VERSION 5.8 ;
BUSBITCHARS "[]" ;
DIVIDERCHAR "/" ;
UNITS
    DATABASE MICRONS 1000 ;
END UNITS

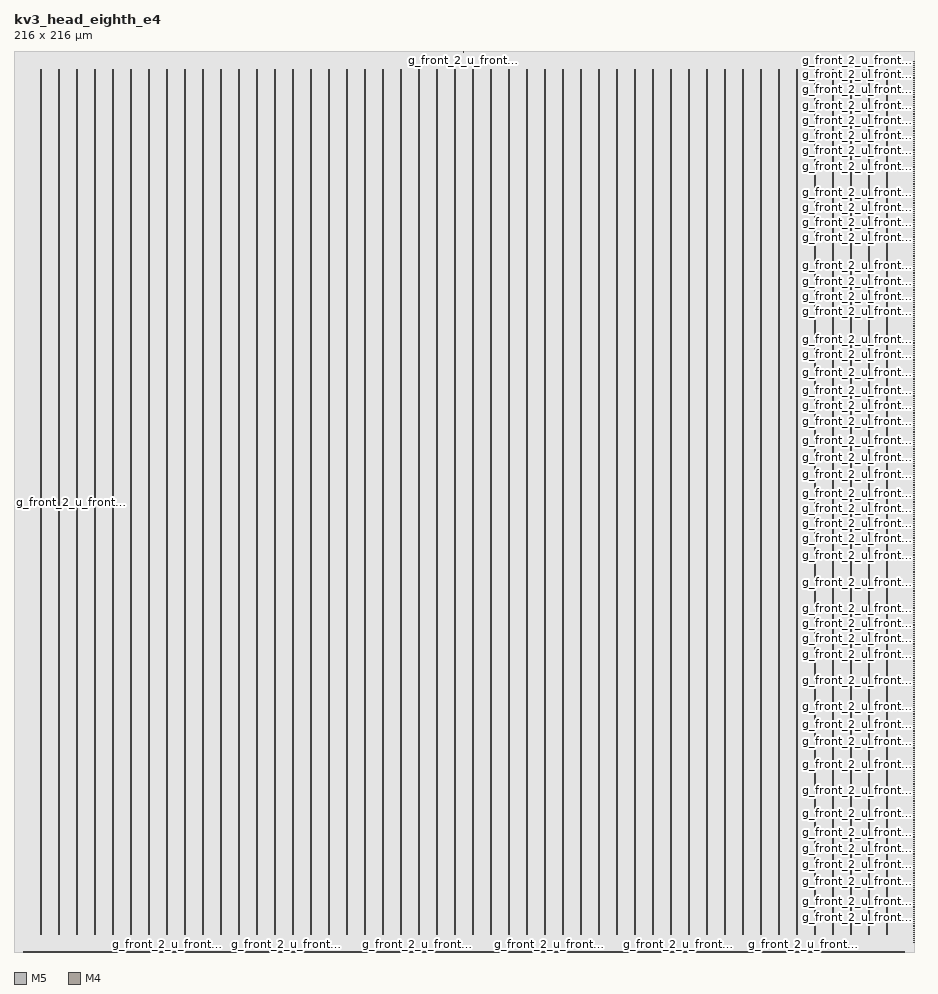
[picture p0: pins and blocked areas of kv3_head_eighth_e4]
MACRO kv3_head_eighth_e4
  FOREIGN kv3_head_eighth_e4 0 0 ;
  CLASS BLOCK ;
  SIZE 216 BY 216 ;
  PIN g_front_2_u_front__c_in[0]
    DIRECTION INPUT ;
    USE SIGNAL ;
    PORT
      LAYER M5 ;
        RECT  2.268 0 2.292 0.192 ;
    END
  END g_front_2_u_front__c_in[0]
  PIN g_front_2_u_front__c_in[1]
    DIRECTION INPUT ;
    USE SIGNAL ;
    PORT
      LAYER M5 ;
        RECT  2.508 0 2.532 0.192 ;
    END
  END g_front_2_u_front__c_in[1]
  PIN g_front_2_u_front__c_in[2]
    DIRECTION INPUT ;
    USE SIGNAL ;
    PORT
      LAYER M5 ;
        RECT  2.748 0 2.772 0.192 ;
    END
  END g_front_2_u_front__c_in[2]
  PIN g_front_2_u_front__c_in[3]
    DIRECTION INPUT ;
    USE SIGNAL ;
    PORT
      LAYER M5 ;
        RECT  2.988 0 3.012 0.192 ;
    END
  END g_front_2_u_front__c_in[3]
  PIN g_front_2_u_front__clk[0]
    DIRECTION INPUT ;
    USE SIGNAL ;
    PORT
      LAYER M5 ;
        RECT  3.228 0 3.252 0.192 ;
    END
  END g_front_2_u_front__clk[0]
  PIN g_front_2_u_front__e_in[0]
    DIRECTION INPUT ;
    USE SIGNAL ;
    PORT
      LAYER M5 ;
        RECT  3.468 0 3.492 0.192 ;
    END
  END g_front_2_u_front__e_in[0]
  PIN g_front_2_u_front__e_in[10]
    DIRECTION INPUT ;
    USE SIGNAL ;
    PORT
      LAYER M5 ;
        RECT  5.82 0 5.844 0.192 ;
    END
  END g_front_2_u_front__e_in[10]
  PIN g_front_2_u_front__e_in[11]
    DIRECTION INPUT ;
    USE SIGNAL ;
    PORT
      LAYER M5 ;
        RECT  6.06 0 6.084 0.192 ;
    END
  END g_front_2_u_front__e_in[11]
  PIN g_front_2_u_front__e_in[12]
    DIRECTION INPUT ;
    USE SIGNAL ;
    PORT
      LAYER M5 ;
        RECT  6.3 0 6.324 0.192 ;
    END
  END g_front_2_u_front__e_in[12]
  PIN g_front_2_u_front__e_in[13]
    DIRECTION INPUT ;
    USE SIGNAL ;
    PORT
      LAYER M5 ;
        RECT  6.54 0 6.564 0.192 ;
    END
  END g_front_2_u_front__e_in[13]
  PIN g_front_2_u_front__e_in[14]
    DIRECTION INPUT ;
    USE SIGNAL ;
    PORT
      LAYER M5 ;
        RECT  6.78 0 6.804 0.192 ;
    END
  END g_front_2_u_front__e_in[14]
  PIN g_front_2_u_front__e_in[15]
    DIRECTION INPUT ;
    USE SIGNAL ;
    PORT
      LAYER M5 ;
        RECT  7.02 0 7.044 0.192 ;
    END
  END g_front_2_u_front__e_in[15]
  PIN g_front_2_u_front__e_in[1]
    DIRECTION INPUT ;
    USE SIGNAL ;
    PORT
      LAYER M5 ;
        RECT  3.708 0 3.732 0.192 ;
    END
  END g_front_2_u_front__e_in[1]
  PIN g_front_2_u_front__e_in[2]
    DIRECTION INPUT ;
    USE SIGNAL ;
    PORT
      LAYER M5 ;
        RECT  3.948 0 3.972 0.192 ;
    END
  END g_front_2_u_front__e_in[2]
  PIN g_front_2_u_front__e_in[3]
    DIRECTION INPUT ;
    USE SIGNAL ;
    PORT
      LAYER M5 ;
        RECT  4.188 0 4.212 0.192 ;
    END
  END g_front_2_u_front__e_in[3]
  PIN g_front_2_u_front__e_in[4]
    DIRECTION INPUT ;
    USE SIGNAL ;
    PORT
      LAYER M5 ;
        RECT  4.428 0 4.452 0.192 ;
    END
  END g_front_2_u_front__e_in[4]
  PIN g_front_2_u_front__e_in[5]
    DIRECTION INPUT ;
    USE SIGNAL ;
    PORT
      LAYER M5 ;
        RECT  4.668 0 4.692 0.192 ;
    END
  END g_front_2_u_front__e_in[5]
  PIN g_front_2_u_front__e_in[6]
    DIRECTION INPUT ;
    USE SIGNAL ;
    PORT
      LAYER M5 ;
        RECT  4.908 0 4.932 0.192 ;
    END
  END g_front_2_u_front__e_in[6]
  PIN g_front_2_u_front__e_in[7]
    DIRECTION INPUT ;
    USE SIGNAL ;
    PORT
      LAYER M5 ;
        RECT  5.148 0 5.172 0.192 ;
    END
  END g_front_2_u_front__e_in[7]
  PIN g_front_2_u_front__e_in[8]
    DIRECTION INPUT ;
    USE SIGNAL ;
    PORT
      LAYER M5 ;
        RECT  5.388 0 5.412 0.192 ;
    END
  END g_front_2_u_front__e_in[8]
  PIN g_front_2_u_front__e_in[9]
    DIRECTION INPUT ;
    USE SIGNAL ;
    PORT
      LAYER M5 ;
        RECT  5.628 0 5.652 0.192 ;
    END
  END g_front_2_u_front__e_in[9]
  PIN g_front_2_u_front__f_t2[0]
    DIRECTION OUTPUT ;
    USE SIGNAL ;
    PORT
      LAYER M4 ;
        RECT  215.808 2.364 216 2.388 ;
    END
  END g_front_2_u_front__f_t2[0]
  PIN g_front_2_u_front__f_t2[100]
    DIRECTION OUTPUT ;
    USE SIGNAL ;
    PORT
      LAYER M4 ;
        RECT  215.808 47.82 216 47.844 ;
    END
  END g_front_2_u_front__f_t2[100]
  PIN g_front_2_u_front__f_t2[101]
    DIRECTION OUTPUT ;
    USE SIGNAL ;
    PORT
      LAYER M4 ;
        RECT  215.808 48.252 216 48.276 ;
    END
  END g_front_2_u_front__f_t2[101]
  PIN g_front_2_u_front__f_t2[102]
    DIRECTION OUTPUT ;
    USE SIGNAL ;
    PORT
      LAYER M4 ;
        RECT  215.808 48.732 216 48.756 ;
    END
  END g_front_2_u_front__f_t2[102]
  PIN g_front_2_u_front__f_t2[103]
    DIRECTION OUTPUT ;
    USE SIGNAL ;
    PORT
      LAYER M4 ;
        RECT  215.808 49.164 216 49.188 ;
    END
  END g_front_2_u_front__f_t2[103]
  PIN g_front_2_u_front__f_t2[104]
    DIRECTION OUTPUT ;
    USE SIGNAL ;
    PORT
      LAYER M4 ;
        RECT  215.808 49.596 216 49.62 ;
    END
  END g_front_2_u_front__f_t2[104]
  PIN g_front_2_u_front__f_t2[105]
    DIRECTION OUTPUT ;
    USE SIGNAL ;
    PORT
      LAYER M4 ;
        RECT  215.808 50.076 216 50.1 ;
    END
  END g_front_2_u_front__f_t2[105]
  PIN g_front_2_u_front__f_t2[106]
    DIRECTION OUTPUT ;
    USE SIGNAL ;
    PORT
      LAYER M4 ;
        RECT  215.808 50.508 216 50.532 ;
    END
  END g_front_2_u_front__f_t2[106]
  PIN g_front_2_u_front__f_t2[107]
    DIRECTION OUTPUT ;
    USE SIGNAL ;
    PORT
      LAYER M4 ;
        RECT  215.808 50.988 216 51.012 ;
    END
  END g_front_2_u_front__f_t2[107]
  PIN g_front_2_u_front__f_t2[108]
    DIRECTION OUTPUT ;
    USE SIGNAL ;
    PORT
      LAYER M4 ;
        RECT  215.808 51.42 216 51.444 ;
    END
  END g_front_2_u_front__f_t2[108]
  PIN g_front_2_u_front__f_t2[109]
    DIRECTION OUTPUT ;
    USE SIGNAL ;
    PORT
      LAYER M4 ;
        RECT  215.808 51.9 216 51.924 ;
    END
  END g_front_2_u_front__f_t2[109]
  PIN g_front_2_u_front__f_t2[10]
    DIRECTION OUTPUT ;
    USE SIGNAL ;
    PORT
      LAYER M4 ;
        RECT  215.808 6.924 216 6.948 ;
    END
  END g_front_2_u_front__f_t2[10]
  PIN g_front_2_u_front__f_t2[110]
    DIRECTION OUTPUT ;
    USE SIGNAL ;
    PORT
      LAYER M4 ;
        RECT  215.808 52.332 216 52.356 ;
    END
  END g_front_2_u_front__f_t2[110]
  PIN g_front_2_u_front__f_t2[111]
    DIRECTION OUTPUT ;
    USE SIGNAL ;
    PORT
      LAYER M4 ;
        RECT  215.808 52.812 216 52.836 ;
    END
  END g_front_2_u_front__f_t2[111]
  PIN g_front_2_u_front__f_t2[112]
    DIRECTION OUTPUT ;
    USE SIGNAL ;
    PORT
      LAYER M4 ;
        RECT  215.808 53.244 216 53.268 ;
    END
  END g_front_2_u_front__f_t2[112]
  PIN g_front_2_u_front__f_t2[113]
    DIRECTION OUTPUT ;
    USE SIGNAL ;
    PORT
      LAYER M4 ;
        RECT  215.808 53.724 216 53.748 ;
    END
  END g_front_2_u_front__f_t2[113]
  PIN g_front_2_u_front__f_t2[114]
    DIRECTION OUTPUT ;
    USE SIGNAL ;
    PORT
      LAYER M4 ;
        RECT  215.808 54.156 216 54.18 ;
    END
  END g_front_2_u_front__f_t2[114]
  PIN g_front_2_u_front__f_t2[115]
    DIRECTION OUTPUT ;
    USE SIGNAL ;
    PORT
      LAYER M4 ;
        RECT  215.808 54.636 216 54.66 ;
    END
  END g_front_2_u_front__f_t2[115]
  PIN g_front_2_u_front__f_t2[116]
    DIRECTION OUTPUT ;
    USE SIGNAL ;
    PORT
      LAYER M4 ;
        RECT  215.808 55.068 216 55.092 ;
    END
  END g_front_2_u_front__f_t2[116]
  PIN g_front_2_u_front__f_t2[117]
    DIRECTION OUTPUT ;
    USE SIGNAL ;
    PORT
      LAYER M4 ;
        RECT  215.808 55.5 216 55.524 ;
    END
  END g_front_2_u_front__f_t2[117]
  PIN g_front_2_u_front__f_t2[118]
    DIRECTION OUTPUT ;
    USE SIGNAL ;
    PORT
      LAYER M4 ;
        RECT  215.808 55.98 216 56.004 ;
    END
  END g_front_2_u_front__f_t2[118]
  PIN g_front_2_u_front__f_t2[119]
    DIRECTION OUTPUT ;
    USE SIGNAL ;
    PORT
      LAYER M4 ;
        RECT  215.808 56.412 216 56.436 ;
    END
  END g_front_2_u_front__f_t2[119]
  PIN g_front_2_u_front__f_t2[11]
    DIRECTION OUTPUT ;
    USE SIGNAL ;
    PORT
      LAYER M4 ;
        RECT  215.808 7.356 216 7.38 ;
    END
  END g_front_2_u_front__f_t2[11]
  PIN g_front_2_u_front__f_t2[120]
    DIRECTION OUTPUT ;
    USE SIGNAL ;
    PORT
      LAYER M4 ;
        RECT  215.808 56.892 216 56.916 ;
    END
  END g_front_2_u_front__f_t2[120]
  PIN g_front_2_u_front__f_t2[121]
    DIRECTION OUTPUT ;
    USE SIGNAL ;
    PORT
      LAYER M4 ;
        RECT  215.808 57.324 216 57.348 ;
    END
  END g_front_2_u_front__f_t2[121]
  PIN g_front_2_u_front__f_t2[122]
    DIRECTION OUTPUT ;
    USE SIGNAL ;
    PORT
      LAYER M4 ;
        RECT  215.808 57.804 216 57.828 ;
    END
  END g_front_2_u_front__f_t2[122]
  PIN g_front_2_u_front__f_t2[123]
    DIRECTION OUTPUT ;
    USE SIGNAL ;
    PORT
      LAYER M4 ;
        RECT  215.808 58.236 216 58.26 ;
    END
  END g_front_2_u_front__f_t2[123]
  PIN g_front_2_u_front__f_t2[124]
    DIRECTION OUTPUT ;
    USE SIGNAL ;
    PORT
      LAYER M4 ;
        RECT  215.808 58.716 216 58.74 ;
    END
  END g_front_2_u_front__f_t2[124]
  PIN g_front_2_u_front__f_t2[125]
    DIRECTION OUTPUT ;
    USE SIGNAL ;
    PORT
      LAYER M4 ;
        RECT  215.808 59.148 216 59.172 ;
    END
  END g_front_2_u_front__f_t2[125]
  PIN g_front_2_u_front__f_t2[126]
    DIRECTION OUTPUT ;
    USE SIGNAL ;
    PORT
      LAYER M4 ;
        RECT  215.808 59.628 216 59.652 ;
    END
  END g_front_2_u_front__f_t2[126]
  PIN g_front_2_u_front__f_t2[127]
    DIRECTION OUTPUT ;
    USE SIGNAL ;
    PORT
      LAYER M4 ;
        RECT  215.808 60.06 216 60.084 ;
    END
  END g_front_2_u_front__f_t2[127]
  PIN g_front_2_u_front__f_t2[128]
    DIRECTION OUTPUT ;
    USE SIGNAL ;
    PORT
      LAYER M4 ;
        RECT  215.808 60.54 216 60.564 ;
    END
  END g_front_2_u_front__f_t2[128]
  PIN g_front_2_u_front__f_t2[129]
    DIRECTION OUTPUT ;
    USE SIGNAL ;
    PORT
      LAYER M4 ;
        RECT  215.808 60.972 216 60.996 ;
    END
  END g_front_2_u_front__f_t2[129]
  PIN g_front_2_u_front__f_t2[12]
    DIRECTION OUTPUT ;
    USE SIGNAL ;
    PORT
      LAYER M4 ;
        RECT  215.808 7.836 216 7.86 ;
    END
  END g_front_2_u_front__f_t2[12]
  PIN g_front_2_u_front__f_t2[130]
    DIRECTION OUTPUT ;
    USE SIGNAL ;
    PORT
      LAYER M4 ;
        RECT  215.808 61.404 216 61.428 ;
    END
  END g_front_2_u_front__f_t2[130]
  PIN g_front_2_u_front__f_t2[131]
    DIRECTION OUTPUT ;
    USE SIGNAL ;
    PORT
      LAYER M4 ;
        RECT  215.808 61.884 216 61.908 ;
    END
  END g_front_2_u_front__f_t2[131]
  PIN g_front_2_u_front__f_t2[132]
    DIRECTION OUTPUT ;
    USE SIGNAL ;
    PORT
      LAYER M4 ;
        RECT  215.808 62.316 216 62.34 ;
    END
  END g_front_2_u_front__f_t2[132]
  PIN g_front_2_u_front__f_t2[133]
    DIRECTION OUTPUT ;
    USE SIGNAL ;
    PORT
      LAYER M4 ;
        RECT  215.808 62.796 216 62.82 ;
    END
  END g_front_2_u_front__f_t2[133]
  PIN g_front_2_u_front__f_t2[134]
    DIRECTION OUTPUT ;
    USE SIGNAL ;
    PORT
      LAYER M4 ;
        RECT  215.808 63.228 216 63.252 ;
    END
  END g_front_2_u_front__f_t2[134]
  PIN g_front_2_u_front__f_t2[135]
    DIRECTION OUTPUT ;
    USE SIGNAL ;
    PORT
      LAYER M4 ;
        RECT  215.808 63.708 216 63.732 ;
    END
  END g_front_2_u_front__f_t2[135]
  PIN g_front_2_u_front__f_t2[136]
    DIRECTION OUTPUT ;
    USE SIGNAL ;
    PORT
      LAYER M4 ;
        RECT  215.808 64.14 216 64.164 ;
    END
  END g_front_2_u_front__f_t2[136]
  PIN g_front_2_u_front__f_t2[137]
    DIRECTION OUTPUT ;
    USE SIGNAL ;
    PORT
      LAYER M4 ;
        RECT  215.808 64.62 216 64.644 ;
    END
  END g_front_2_u_front__f_t2[137]
  PIN g_front_2_u_front__f_t2[138]
    DIRECTION OUTPUT ;
    USE SIGNAL ;
    PORT
      LAYER M4 ;
        RECT  215.808 65.052 216 65.076 ;
    END
  END g_front_2_u_front__f_t2[138]
  PIN g_front_2_u_front__f_t2[139]
    DIRECTION OUTPUT ;
    USE SIGNAL ;
    PORT
      LAYER M4 ;
        RECT  215.808 65.532 216 65.556 ;
    END
  END g_front_2_u_front__f_t2[139]
  PIN g_front_2_u_front__f_t2[13]
    DIRECTION OUTPUT ;
    USE SIGNAL ;
    PORT
      LAYER M4 ;
        RECT  215.808 8.268 216 8.292 ;
    END
  END g_front_2_u_front__f_t2[13]
  PIN g_front_2_u_front__f_t2[140]
    DIRECTION OUTPUT ;
    USE SIGNAL ;
    PORT
      LAYER M4 ;
        RECT  215.808 65.964 216 65.988 ;
    END
  END g_front_2_u_front__f_t2[140]
  PIN g_front_2_u_front__f_t2[141]
    DIRECTION OUTPUT ;
    USE SIGNAL ;
    PORT
      LAYER M4 ;
        RECT  215.808 66.444 216 66.468 ;
    END
  END g_front_2_u_front__f_t2[141]
  PIN g_front_2_u_front__f_t2[142]
    DIRECTION OUTPUT ;
    USE SIGNAL ;
    PORT
      LAYER M4 ;
        RECT  215.808 66.876 216 66.9 ;
    END
  END g_front_2_u_front__f_t2[142]
  PIN g_front_2_u_front__f_t2[143]
    DIRECTION OUTPUT ;
    USE SIGNAL ;
    PORT
      LAYER M4 ;
        RECT  215.808 67.356 216 67.38 ;
    END
  END g_front_2_u_front__f_t2[143]
  PIN g_front_2_u_front__f_t2[144]
    DIRECTION OUTPUT ;
    USE SIGNAL ;
    PORT
      LAYER M4 ;
        RECT  215.808 67.788 216 67.812 ;
    END
  END g_front_2_u_front__f_t2[144]
  PIN g_front_2_u_front__f_t2[145]
    DIRECTION OUTPUT ;
    USE SIGNAL ;
    PORT
      LAYER M4 ;
        RECT  215.808 68.22 216 68.244 ;
    END
  END g_front_2_u_front__f_t2[145]
  PIN g_front_2_u_front__f_t2[146]
    DIRECTION OUTPUT ;
    USE SIGNAL ;
    PORT
      LAYER M4 ;
        RECT  215.808 68.7 216 68.724 ;
    END
  END g_front_2_u_front__f_t2[146]
  PIN g_front_2_u_front__f_t2[147]
    DIRECTION OUTPUT ;
    USE SIGNAL ;
    PORT
      LAYER M4 ;
        RECT  215.808 69.132 216 69.156 ;
    END
  END g_front_2_u_front__f_t2[147]
  PIN g_front_2_u_front__f_t2[148]
    DIRECTION OUTPUT ;
    USE SIGNAL ;
    PORT
      LAYER M4 ;
        RECT  215.808 69.612 216 69.636 ;
    END
  END g_front_2_u_front__f_t2[148]
  PIN g_front_2_u_front__f_t2[149]
    DIRECTION OUTPUT ;
    USE SIGNAL ;
    PORT
      LAYER M4 ;
        RECT  215.808 70.044 216 70.068 ;
    END
  END g_front_2_u_front__f_t2[149]
  PIN g_front_2_u_front__f_t2[14]
    DIRECTION OUTPUT ;
    USE SIGNAL ;
    PORT
      LAYER M4 ;
        RECT  215.808 8.748 216 8.772 ;
    END
  END g_front_2_u_front__f_t2[14]
  PIN g_front_2_u_front__f_t2[150]
    DIRECTION OUTPUT ;
    USE SIGNAL ;
    PORT
      LAYER M4 ;
        RECT  215.808 70.524 216 70.548 ;
    END
  END g_front_2_u_front__f_t2[150]
  PIN g_front_2_u_front__f_t2[151]
    DIRECTION OUTPUT ;
    USE SIGNAL ;
    PORT
      LAYER M4 ;
        RECT  215.808 70.956 216 70.98 ;
    END
  END g_front_2_u_front__f_t2[151]
  PIN g_front_2_u_front__f_t2[152]
    DIRECTION OUTPUT ;
    USE SIGNAL ;
    PORT
      LAYER M4 ;
        RECT  215.808 71.436 216 71.46 ;
    END
  END g_front_2_u_front__f_t2[152]
  PIN g_front_2_u_front__f_t2[153]
    DIRECTION OUTPUT ;
    USE SIGNAL ;
    PORT
      LAYER M4 ;
        RECT  215.808 71.868 216 71.892 ;
    END
  END g_front_2_u_front__f_t2[153]
  PIN g_front_2_u_front__f_t2[154]
    DIRECTION OUTPUT ;
    USE SIGNAL ;
    PORT
      LAYER M4 ;
        RECT  215.808 72.348 216 72.372 ;
    END
  END g_front_2_u_front__f_t2[154]
  PIN g_front_2_u_front__f_t2[155]
    DIRECTION OUTPUT ;
    USE SIGNAL ;
    PORT
      LAYER M4 ;
        RECT  215.808 72.78 216 72.804 ;
    END
  END g_front_2_u_front__f_t2[155]
  PIN g_front_2_u_front__f_t2[156]
    DIRECTION OUTPUT ;
    USE SIGNAL ;
    PORT
      LAYER M4 ;
        RECT  215.808 73.26 216 73.284 ;
    END
  END g_front_2_u_front__f_t2[156]
  PIN g_front_2_u_front__f_t2[157]
    DIRECTION OUTPUT ;
    USE SIGNAL ;
    PORT
      LAYER M4 ;
        RECT  215.808 73.692 216 73.716 ;
    END
  END g_front_2_u_front__f_t2[157]
  PIN g_front_2_u_front__f_t2[158]
    DIRECTION OUTPUT ;
    USE SIGNAL ;
    PORT
      LAYER M4 ;
        RECT  215.808 74.124 216 74.148 ;
    END
  END g_front_2_u_front__f_t2[158]
  PIN g_front_2_u_front__f_t2[159]
    DIRECTION OUTPUT ;
    USE SIGNAL ;
    PORT
      LAYER M4 ;
        RECT  215.808 74.604 216 74.628 ;
    END
  END g_front_2_u_front__f_t2[159]
  PIN g_front_2_u_front__f_t2[15]
    DIRECTION OUTPUT ;
    USE SIGNAL ;
    PORT
      LAYER M4 ;
        RECT  215.808 9.18 216 9.204 ;
    END
  END g_front_2_u_front__f_t2[15]
  PIN g_front_2_u_front__f_t2[160]
    DIRECTION OUTPUT ;
    USE SIGNAL ;
    PORT
      LAYER M4 ;
        RECT  215.808 75.036 216 75.06 ;
    END
  END g_front_2_u_front__f_t2[160]
  PIN g_front_2_u_front__f_t2[161]
    DIRECTION OUTPUT ;
    USE SIGNAL ;
    PORT
      LAYER M4 ;
        RECT  215.808 75.516 216 75.54 ;
    END
  END g_front_2_u_front__f_t2[161]
  PIN g_front_2_u_front__f_t2[162]
    DIRECTION OUTPUT ;
    USE SIGNAL ;
    PORT
      LAYER M4 ;
        RECT  215.808 75.948 216 75.972 ;
    END
  END g_front_2_u_front__f_t2[162]
  PIN g_front_2_u_front__f_t2[163]
    DIRECTION OUTPUT ;
    USE SIGNAL ;
    PORT
      LAYER M4 ;
        RECT  215.808 76.428 216 76.452 ;
    END
  END g_front_2_u_front__f_t2[163]
  PIN g_front_2_u_front__f_t2[164]
    DIRECTION OUTPUT ;
    USE SIGNAL ;
    PORT
      LAYER M4 ;
        RECT  215.808 76.86 216 76.884 ;
    END
  END g_front_2_u_front__f_t2[164]
  PIN g_front_2_u_front__f_t2[165]
    DIRECTION OUTPUT ;
    USE SIGNAL ;
    PORT
      LAYER M4 ;
        RECT  215.808 77.34 216 77.364 ;
    END
  END g_front_2_u_front__f_t2[165]
  PIN g_front_2_u_front__f_t2[166]
    DIRECTION OUTPUT ;
    USE SIGNAL ;
    PORT
      LAYER M4 ;
        RECT  215.808 77.772 216 77.796 ;
    END
  END g_front_2_u_front__f_t2[166]
  PIN g_front_2_u_front__f_t2[167]
    DIRECTION OUTPUT ;
    USE SIGNAL ;
    PORT
      LAYER M4 ;
        RECT  215.808 78.252 216 78.276 ;
    END
  END g_front_2_u_front__f_t2[167]
  PIN g_front_2_u_front__f_t2[168]
    DIRECTION OUTPUT ;
    USE SIGNAL ;
    PORT
      LAYER M4 ;
        RECT  215.808 78.684 216 78.708 ;
    END
  END g_front_2_u_front__f_t2[168]
  PIN g_front_2_u_front__f_t2[169]
    DIRECTION OUTPUT ;
    USE SIGNAL ;
    PORT
      LAYER M4 ;
        RECT  215.808 79.164 216 79.188 ;
    END
  END g_front_2_u_front__f_t2[169]
  PIN g_front_2_u_front__f_t2[16]
    DIRECTION OUTPUT ;
    USE SIGNAL ;
    PORT
      LAYER M4 ;
        RECT  215.808 9.66 216 9.684 ;
    END
  END g_front_2_u_front__f_t2[16]
  PIN g_front_2_u_front__f_t2[170]
    DIRECTION OUTPUT ;
    USE SIGNAL ;
    PORT
      LAYER M4 ;
        RECT  215.808 79.596 216 79.62 ;
    END
  END g_front_2_u_front__f_t2[170]
  PIN g_front_2_u_front__f_t2[171]
    DIRECTION OUTPUT ;
    USE SIGNAL ;
    PORT
      LAYER M4 ;
        RECT  215.808 80.028 216 80.052 ;
    END
  END g_front_2_u_front__f_t2[171]
  PIN g_front_2_u_front__f_t2[172]
    DIRECTION OUTPUT ;
    USE SIGNAL ;
    PORT
      LAYER M4 ;
        RECT  215.808 80.508 216 80.532 ;
    END
  END g_front_2_u_front__f_t2[172]
  PIN g_front_2_u_front__f_t2[173]
    DIRECTION OUTPUT ;
    USE SIGNAL ;
    PORT
      LAYER M4 ;
        RECT  215.808 80.94 216 80.964 ;
    END
  END g_front_2_u_front__f_t2[173]
  PIN g_front_2_u_front__f_t2[174]
    DIRECTION OUTPUT ;
    USE SIGNAL ;
    PORT
      LAYER M4 ;
        RECT  215.808 81.42 216 81.444 ;
    END
  END g_front_2_u_front__f_t2[174]
  PIN g_front_2_u_front__f_t2[175]
    DIRECTION OUTPUT ;
    USE SIGNAL ;
    PORT
      LAYER M4 ;
        RECT  215.808 81.852 216 81.876 ;
    END
  END g_front_2_u_front__f_t2[175]
  PIN g_front_2_u_front__f_t2[176]
    DIRECTION OUTPUT ;
    USE SIGNAL ;
    PORT
      LAYER M4 ;
        RECT  215.808 82.332 216 82.356 ;
    END
  END g_front_2_u_front__f_t2[176]
  PIN g_front_2_u_front__f_t2[177]
    DIRECTION OUTPUT ;
    USE SIGNAL ;
    PORT
      LAYER M4 ;
        RECT  215.808 82.764 216 82.788 ;
    END
  END g_front_2_u_front__f_t2[177]
  PIN g_front_2_u_front__f_t2[178]
    DIRECTION OUTPUT ;
    USE SIGNAL ;
    PORT
      LAYER M4 ;
        RECT  215.808 83.244 216 83.268 ;
    END
  END g_front_2_u_front__f_t2[178]
  PIN g_front_2_u_front__f_t2[179]
    DIRECTION OUTPUT ;
    USE SIGNAL ;
    PORT
      LAYER M4 ;
        RECT  215.808 83.676 216 83.7 ;
    END
  END g_front_2_u_front__f_t2[179]
  PIN g_front_2_u_front__f_t2[17]
    DIRECTION OUTPUT ;
    USE SIGNAL ;
    PORT
      LAYER M4 ;
        RECT  215.808 10.092 216 10.116 ;
    END
  END g_front_2_u_front__f_t2[17]
  PIN g_front_2_u_front__f_t2[180]
    DIRECTION OUTPUT ;
    USE SIGNAL ;
    PORT
      LAYER M4 ;
        RECT  215.808 84.156 216 84.18 ;
    END
  END g_front_2_u_front__f_t2[180]
  PIN g_front_2_u_front__f_t2[181]
    DIRECTION OUTPUT ;
    USE SIGNAL ;
    PORT
      LAYER M4 ;
        RECT  215.808 84.588 216 84.612 ;
    END
  END g_front_2_u_front__f_t2[181]
  PIN g_front_2_u_front__f_t2[182]
    DIRECTION OUTPUT ;
    USE SIGNAL ;
    PORT
      LAYER M4 ;
        RECT  215.808 85.068 216 85.092 ;
    END
  END g_front_2_u_front__f_t2[182]
  PIN g_front_2_u_front__f_t2[183]
    DIRECTION OUTPUT ;
    USE SIGNAL ;
    PORT
      LAYER M4 ;
        RECT  215.808 85.5 216 85.524 ;
    END
  END g_front_2_u_front__f_t2[183]
  PIN g_front_2_u_front__f_t2[184]
    DIRECTION OUTPUT ;
    USE SIGNAL ;
    PORT
      LAYER M4 ;
        RECT  215.808 85.98 216 86.004 ;
    END
  END g_front_2_u_front__f_t2[184]
  PIN g_front_2_u_front__f_t2[185]
    DIRECTION OUTPUT ;
    USE SIGNAL ;
    PORT
      LAYER M4 ;
        RECT  215.808 86.412 216 86.436 ;
    END
  END g_front_2_u_front__f_t2[185]
  PIN g_front_2_u_front__f_t2[186]
    DIRECTION OUTPUT ;
    USE SIGNAL ;
    PORT
      LAYER M4 ;
        RECT  215.808 86.844 216 86.868 ;
    END
  END g_front_2_u_front__f_t2[186]
  PIN g_front_2_u_front__f_t2[187]
    DIRECTION OUTPUT ;
    USE SIGNAL ;
    PORT
      LAYER M4 ;
        RECT  215.808 87.324 216 87.348 ;
    END
  END g_front_2_u_front__f_t2[187]
  PIN g_front_2_u_front__f_t2[188]
    DIRECTION OUTPUT ;
    USE SIGNAL ;
    PORT
      LAYER M4 ;
        RECT  215.808 87.756 216 87.78 ;
    END
  END g_front_2_u_front__f_t2[188]
  PIN g_front_2_u_front__f_t2[189]
    DIRECTION OUTPUT ;
    USE SIGNAL ;
    PORT
      LAYER M4 ;
        RECT  215.808 88.236 216 88.26 ;
    END
  END g_front_2_u_front__f_t2[189]
  PIN g_front_2_u_front__f_t2[18]
    DIRECTION OUTPUT ;
    USE SIGNAL ;
    PORT
      LAYER M4 ;
        RECT  215.808 10.572 216 10.596 ;
    END
  END g_front_2_u_front__f_t2[18]
  PIN g_front_2_u_front__f_t2[190]
    DIRECTION OUTPUT ;
    USE SIGNAL ;
    PORT
      LAYER M4 ;
        RECT  215.808 88.668 216 88.692 ;
    END
  END g_front_2_u_front__f_t2[190]
  PIN g_front_2_u_front__f_t2[191]
    DIRECTION OUTPUT ;
    USE SIGNAL ;
    PORT
      LAYER M4 ;
        RECT  215.808 89.148 216 89.172 ;
    END
  END g_front_2_u_front__f_t2[191]
  PIN g_front_2_u_front__f_t2[192]
    DIRECTION OUTPUT ;
    USE SIGNAL ;
    PORT
      LAYER M4 ;
        RECT  215.808 89.58 216 89.604 ;
    END
  END g_front_2_u_front__f_t2[192]
  PIN g_front_2_u_front__f_t2[193]
    DIRECTION OUTPUT ;
    USE SIGNAL ;
    PORT
      LAYER M4 ;
        RECT  215.808 90.06 216 90.084 ;
    END
  END g_front_2_u_front__f_t2[193]
  PIN g_front_2_u_front__f_t2[194]
    DIRECTION OUTPUT ;
    USE SIGNAL ;
    PORT
      LAYER M4 ;
        RECT  215.808 90.492 216 90.516 ;
    END
  END g_front_2_u_front__f_t2[194]
  PIN g_front_2_u_front__f_t2[195]
    DIRECTION OUTPUT ;
    USE SIGNAL ;
    PORT
      LAYER M4 ;
        RECT  215.808 90.972 216 90.996 ;
    END
  END g_front_2_u_front__f_t2[195]
  PIN g_front_2_u_front__f_t2[196]
    DIRECTION OUTPUT ;
    USE SIGNAL ;
    PORT
      LAYER M4 ;
        RECT  215.808 91.404 216 91.428 ;
    END
  END g_front_2_u_front__f_t2[196]
  PIN g_front_2_u_front__f_t2[197]
    DIRECTION OUTPUT ;
    USE SIGNAL ;
    PORT
      LAYER M4 ;
        RECT  215.808 91.884 216 91.908 ;
    END
  END g_front_2_u_front__f_t2[197]
  PIN g_front_2_u_front__f_t2[198]
    DIRECTION OUTPUT ;
    USE SIGNAL ;
    PORT
      LAYER M4 ;
        RECT  215.808 92.316 216 92.34 ;
    END
  END g_front_2_u_front__f_t2[198]
  PIN g_front_2_u_front__f_t2[199]
    DIRECTION OUTPUT ;
    USE SIGNAL ;
    PORT
      LAYER M4 ;
        RECT  215.808 92.748 216 92.772 ;
    END
  END g_front_2_u_front__f_t2[199]
  PIN g_front_2_u_front__f_t2[19]
    DIRECTION OUTPUT ;
    USE SIGNAL ;
    PORT
      LAYER M4 ;
        RECT  215.808 11.004 216 11.028 ;
    END
  END g_front_2_u_front__f_t2[19]
  PIN g_front_2_u_front__f_t2[1]
    DIRECTION OUTPUT ;
    USE SIGNAL ;
    PORT
      LAYER M4 ;
        RECT  215.808 2.844 216 2.868 ;
    END
  END g_front_2_u_front__f_t2[1]
  PIN g_front_2_u_front__f_t2[200]
    DIRECTION OUTPUT ;
    USE SIGNAL ;
    PORT
      LAYER M4 ;
        RECT  215.808 93.228 216 93.252 ;
    END
  END g_front_2_u_front__f_t2[200]
  PIN g_front_2_u_front__f_t2[201]
    DIRECTION OUTPUT ;
    USE SIGNAL ;
    PORT
      LAYER M4 ;
        RECT  215.808 93.66 216 93.684 ;
    END
  END g_front_2_u_front__f_t2[201]
  PIN g_front_2_u_front__f_t2[202]
    DIRECTION OUTPUT ;
    USE SIGNAL ;
    PORT
      LAYER M4 ;
        RECT  215.808 94.14 216 94.164 ;
    END
  END g_front_2_u_front__f_t2[202]
  PIN g_front_2_u_front__f_t2[203]
    DIRECTION OUTPUT ;
    USE SIGNAL ;
    PORT
      LAYER M4 ;
        RECT  215.808 94.572 216 94.596 ;
    END
  END g_front_2_u_front__f_t2[203]
  PIN g_front_2_u_front__f_t2[204]
    DIRECTION OUTPUT ;
    USE SIGNAL ;
    PORT
      LAYER M4 ;
        RECT  215.808 95.052 216 95.076 ;
    END
  END g_front_2_u_front__f_t2[204]
  PIN g_front_2_u_front__f_t2[205]
    DIRECTION OUTPUT ;
    USE SIGNAL ;
    PORT
      LAYER M4 ;
        RECT  215.808 95.484 216 95.508 ;
    END
  END g_front_2_u_front__f_t2[205]
  PIN g_front_2_u_front__f_t2[206]
    DIRECTION OUTPUT ;
    USE SIGNAL ;
    PORT
      LAYER M4 ;
        RECT  215.808 95.964 216 95.988 ;
    END
  END g_front_2_u_front__f_t2[206]
  PIN g_front_2_u_front__f_t2[207]
    DIRECTION OUTPUT ;
    USE SIGNAL ;
    PORT
      LAYER M4 ;
        RECT  215.808 96.396 216 96.42 ;
    END
  END g_front_2_u_front__f_t2[207]
  PIN g_front_2_u_front__f_t2[208]
    DIRECTION OUTPUT ;
    USE SIGNAL ;
    PORT
      LAYER M4 ;
        RECT  215.808 96.876 216 96.9 ;
    END
  END g_front_2_u_front__f_t2[208]
  PIN g_front_2_u_front__f_t2[209]
    DIRECTION OUTPUT ;
    USE SIGNAL ;
    PORT
      LAYER M4 ;
        RECT  215.808 97.308 216 97.332 ;
    END
  END g_front_2_u_front__f_t2[209]
  PIN g_front_2_u_front__f_t2[20]
    DIRECTION OUTPUT ;
    USE SIGNAL ;
    PORT
      LAYER M4 ;
        RECT  215.808 11.484 216 11.508 ;
    END
  END g_front_2_u_front__f_t2[20]
  PIN g_front_2_u_front__f_t2[210]
    DIRECTION OUTPUT ;
    USE SIGNAL ;
    PORT
      LAYER M4 ;
        RECT  215.808 97.788 216 97.812 ;
    END
  END g_front_2_u_front__f_t2[210]
  PIN g_front_2_u_front__f_t2[211]
    DIRECTION OUTPUT ;
    USE SIGNAL ;
    PORT
      LAYER M4 ;
        RECT  215.808 98.22 216 98.244 ;
    END
  END g_front_2_u_front__f_t2[211]
  PIN g_front_2_u_front__f_t2[212]
    DIRECTION OUTPUT ;
    USE SIGNAL ;
    PORT
      LAYER M4 ;
        RECT  215.808 98.652 216 98.676 ;
    END
  END g_front_2_u_front__f_t2[212]
  PIN g_front_2_u_front__f_t2[213]
    DIRECTION OUTPUT ;
    USE SIGNAL ;
    PORT
      LAYER M4 ;
        RECT  215.808 99.132 216 99.156 ;
    END
  END g_front_2_u_front__f_t2[213]
  PIN g_front_2_u_front__f_t2[214]
    DIRECTION OUTPUT ;
    USE SIGNAL ;
    PORT
      LAYER M4 ;
        RECT  215.808 99.564 216 99.588 ;
    END
  END g_front_2_u_front__f_t2[214]
  PIN g_front_2_u_front__f_t2[215]
    DIRECTION OUTPUT ;
    USE SIGNAL ;
    PORT
      LAYER M4 ;
        RECT  215.808 100.044 216 100.068 ;
    END
  END g_front_2_u_front__f_t2[215]
  PIN g_front_2_u_front__f_t2[216]
    DIRECTION OUTPUT ;
    USE SIGNAL ;
    PORT
      LAYER M4 ;
        RECT  215.808 100.476 216 100.5 ;
    END
  END g_front_2_u_front__f_t2[216]
  PIN g_front_2_u_front__f_t2[217]
    DIRECTION OUTPUT ;
    USE SIGNAL ;
    PORT
      LAYER M4 ;
        RECT  215.808 100.956 216 100.98 ;
    END
  END g_front_2_u_front__f_t2[217]
  PIN g_front_2_u_front__f_t2[218]
    DIRECTION OUTPUT ;
    USE SIGNAL ;
    PORT
      LAYER M4 ;
        RECT  215.808 101.388 216 101.412 ;
    END
  END g_front_2_u_front__f_t2[218]
  PIN g_front_2_u_front__f_t2[219]
    DIRECTION OUTPUT ;
    USE SIGNAL ;
    PORT
      LAYER M4 ;
        RECT  215.808 101.868 216 101.892 ;
    END
  END g_front_2_u_front__f_t2[219]
  PIN g_front_2_u_front__f_t2[21]
    DIRECTION OUTPUT ;
    USE SIGNAL ;
    PORT
      LAYER M4 ;
        RECT  215.808 11.916 216 11.94 ;
    END
  END g_front_2_u_front__f_t2[21]
  PIN g_front_2_u_front__f_t2[220]
    DIRECTION OUTPUT ;
    USE SIGNAL ;
    PORT
      LAYER M4 ;
        RECT  215.808 102.3 216 102.324 ;
    END
  END g_front_2_u_front__f_t2[220]
  PIN g_front_2_u_front__f_t2[221]
    DIRECTION OUTPUT ;
    USE SIGNAL ;
    PORT
      LAYER M4 ;
        RECT  215.808 102.78 216 102.804 ;
    END
  END g_front_2_u_front__f_t2[221]
  PIN g_front_2_u_front__f_t2[222]
    DIRECTION OUTPUT ;
    USE SIGNAL ;
    PORT
      LAYER M4 ;
        RECT  215.808 103.212 216 103.236 ;
    END
  END g_front_2_u_front__f_t2[222]
  PIN g_front_2_u_front__f_t2[223]
    DIRECTION OUTPUT ;
    USE SIGNAL ;
    PORT
      LAYER M4 ;
        RECT  215.808 103.692 216 103.716 ;
    END
  END g_front_2_u_front__f_t2[223]
  PIN g_front_2_u_front__f_t2[224]
    DIRECTION OUTPUT ;
    USE SIGNAL ;
    PORT
      LAYER M4 ;
        RECT  215.808 104.124 216 104.148 ;
    END
  END g_front_2_u_front__f_t2[224]
  PIN g_front_2_u_front__f_t2[225]
    DIRECTION OUTPUT ;
    USE SIGNAL ;
    PORT
      LAYER M4 ;
        RECT  215.808 104.604 216 104.628 ;
    END
  END g_front_2_u_front__f_t2[225]
  PIN g_front_2_u_front__f_t2[226]
    DIRECTION OUTPUT ;
    USE SIGNAL ;
    PORT
      LAYER M4 ;
        RECT  215.808 105.036 216 105.06 ;
    END
  END g_front_2_u_front__f_t2[226]
  PIN g_front_2_u_front__f_t2[227]
    DIRECTION OUTPUT ;
    USE SIGNAL ;
    PORT
      LAYER M4 ;
        RECT  215.808 105.468 216 105.492 ;
    END
  END g_front_2_u_front__f_t2[227]
  PIN g_front_2_u_front__f_t2[228]
    DIRECTION OUTPUT ;
    USE SIGNAL ;
    PORT
      LAYER M4 ;
        RECT  215.808 105.948 216 105.972 ;
    END
  END g_front_2_u_front__f_t2[228]
  PIN g_front_2_u_front__f_t2[229]
    DIRECTION OUTPUT ;
    USE SIGNAL ;
    PORT
      LAYER M4 ;
        RECT  215.808 106.38 216 106.404 ;
    END
  END g_front_2_u_front__f_t2[229]
  PIN g_front_2_u_front__f_t2[22]
    DIRECTION OUTPUT ;
    USE SIGNAL ;
    PORT
      LAYER M4 ;
        RECT  215.808 12.348 216 12.372 ;
    END
  END g_front_2_u_front__f_t2[22]
  PIN g_front_2_u_front__f_t2[230]
    DIRECTION OUTPUT ;
    USE SIGNAL ;
    PORT
      LAYER M4 ;
        RECT  215.808 106.86 216 106.884 ;
    END
  END g_front_2_u_front__f_t2[230]
  PIN g_front_2_u_front__f_t2[231]
    DIRECTION OUTPUT ;
    USE SIGNAL ;
    PORT
      LAYER M4 ;
        RECT  215.808 107.292 216 107.316 ;
    END
  END g_front_2_u_front__f_t2[231]
  PIN g_front_2_u_front__f_t2[232]
    DIRECTION OUTPUT ;
    USE SIGNAL ;
    PORT
      LAYER M4 ;
        RECT  215.808 107.772 216 107.796 ;
    END
  END g_front_2_u_front__f_t2[232]
  PIN g_front_2_u_front__f_t2[23]
    DIRECTION OUTPUT ;
    USE SIGNAL ;
    PORT
      LAYER M4 ;
        RECT  215.808 12.828 216 12.852 ;
    END
  END g_front_2_u_front__f_t2[23]
  PIN g_front_2_u_front__f_t2[24]
    DIRECTION OUTPUT ;
    USE SIGNAL ;
    PORT
      LAYER M4 ;
        RECT  215.808 13.26 216 13.284 ;
    END
  END g_front_2_u_front__f_t2[24]
  PIN g_front_2_u_front__f_t2[25]
    DIRECTION OUTPUT ;
    USE SIGNAL ;
    PORT
      LAYER M4 ;
        RECT  215.808 13.74 216 13.764 ;
    END
  END g_front_2_u_front__f_t2[25]
  PIN g_front_2_u_front__f_t2[26]
    DIRECTION OUTPUT ;
    USE SIGNAL ;
    PORT
      LAYER M4 ;
        RECT  215.808 14.172 216 14.196 ;
    END
  END g_front_2_u_front__f_t2[26]
  PIN g_front_2_u_front__f_t2[27]
    DIRECTION OUTPUT ;
    USE SIGNAL ;
    PORT
      LAYER M4 ;
        RECT  215.808 14.652 216 14.676 ;
    END
  END g_front_2_u_front__f_t2[27]
  PIN g_front_2_u_front__f_t2[28]
    DIRECTION OUTPUT ;
    USE SIGNAL ;
    PORT
      LAYER M4 ;
        RECT  215.808 15.084 216 15.108 ;
    END
  END g_front_2_u_front__f_t2[28]
  PIN g_front_2_u_front__f_t2[29]
    DIRECTION OUTPUT ;
    USE SIGNAL ;
    PORT
      LAYER M4 ;
        RECT  215.808 15.564 216 15.588 ;
    END
  END g_front_2_u_front__f_t2[29]
  PIN g_front_2_u_front__f_t2[2]
    DIRECTION OUTPUT ;
    USE SIGNAL ;
    PORT
      LAYER M4 ;
        RECT  215.808 3.276 216 3.3 ;
    END
  END g_front_2_u_front__f_t2[2]
  PIN g_front_2_u_front__f_t2[30]
    DIRECTION OUTPUT ;
    USE SIGNAL ;
    PORT
      LAYER M4 ;
        RECT  215.808 15.996 216 16.02 ;
    END
  END g_front_2_u_front__f_t2[30]
  PIN g_front_2_u_front__f_t2[31]
    DIRECTION OUTPUT ;
    USE SIGNAL ;
    PORT
      LAYER M4 ;
        RECT  215.808 16.476 216 16.5 ;
    END
  END g_front_2_u_front__f_t2[31]
  PIN g_front_2_u_front__f_t2[32]
    DIRECTION OUTPUT ;
    USE SIGNAL ;
    PORT
      LAYER M4 ;
        RECT  215.808 16.908 216 16.932 ;
    END
  END g_front_2_u_front__f_t2[32]
  PIN g_front_2_u_front__f_t2[33]
    DIRECTION OUTPUT ;
    USE SIGNAL ;
    PORT
      LAYER M4 ;
        RECT  215.808 17.388 216 17.412 ;
    END
  END g_front_2_u_front__f_t2[33]
  PIN g_front_2_u_front__f_t2[34]
    DIRECTION OUTPUT ;
    USE SIGNAL ;
    PORT
      LAYER M4 ;
        RECT  215.808 17.82 216 17.844 ;
    END
  END g_front_2_u_front__f_t2[34]
  PIN g_front_2_u_front__f_t2[35]
    DIRECTION OUTPUT ;
    USE SIGNAL ;
    PORT
      LAYER M4 ;
        RECT  215.808 18.252 216 18.276 ;
    END
  END g_front_2_u_front__f_t2[35]
  PIN g_front_2_u_front__f_t2[36]
    DIRECTION OUTPUT ;
    USE SIGNAL ;
    PORT
      LAYER M4 ;
        RECT  215.808 18.732 216 18.756 ;
    END
  END g_front_2_u_front__f_t2[36]
  PIN g_front_2_u_front__f_t2[37]
    DIRECTION OUTPUT ;
    USE SIGNAL ;
    PORT
      LAYER M4 ;
        RECT  215.808 19.164 216 19.188 ;
    END
  END g_front_2_u_front__f_t2[37]
  PIN g_front_2_u_front__f_t2[38]
    DIRECTION OUTPUT ;
    USE SIGNAL ;
    PORT
      LAYER M4 ;
        RECT  215.808 19.644 216 19.668 ;
    END
  END g_front_2_u_front__f_t2[38]
  PIN g_front_2_u_front__f_t2[39]
    DIRECTION OUTPUT ;
    USE SIGNAL ;
    PORT
      LAYER M4 ;
        RECT  215.808 20.076 216 20.1 ;
    END
  END g_front_2_u_front__f_t2[39]
  PIN g_front_2_u_front__f_t2[3]
    DIRECTION OUTPUT ;
    USE SIGNAL ;
    PORT
      LAYER M4 ;
        RECT  215.808 3.756 216 3.78 ;
    END
  END g_front_2_u_front__f_t2[3]
  PIN g_front_2_u_front__f_t2[40]
    DIRECTION OUTPUT ;
    USE SIGNAL ;
    PORT
      LAYER M4 ;
        RECT  215.808 20.556 216 20.58 ;
    END
  END g_front_2_u_front__f_t2[40]
  PIN g_front_2_u_front__f_t2[41]
    DIRECTION OUTPUT ;
    USE SIGNAL ;
    PORT
      LAYER M4 ;
        RECT  215.808 20.988 216 21.012 ;
    END
  END g_front_2_u_front__f_t2[41]
  PIN g_front_2_u_front__f_t2[42]
    DIRECTION OUTPUT ;
    USE SIGNAL ;
    PORT
      LAYER M4 ;
        RECT  215.808 21.468 216 21.492 ;
    END
  END g_front_2_u_front__f_t2[42]
  PIN g_front_2_u_front__f_t2[43]
    DIRECTION OUTPUT ;
    USE SIGNAL ;
    PORT
      LAYER M4 ;
        RECT  215.808 21.9 216 21.924 ;
    END
  END g_front_2_u_front__f_t2[43]
  PIN g_front_2_u_front__f_t2[44]
    DIRECTION OUTPUT ;
    USE SIGNAL ;
    PORT
      LAYER M4 ;
        RECT  215.808 22.38 216 22.404 ;
    END
  END g_front_2_u_front__f_t2[44]
  PIN g_front_2_u_front__f_t2[45]
    DIRECTION OUTPUT ;
    USE SIGNAL ;
    PORT
      LAYER M4 ;
        RECT  215.808 22.812 216 22.836 ;
    END
  END g_front_2_u_front__f_t2[45]
  PIN g_front_2_u_front__f_t2[46]
    DIRECTION OUTPUT ;
    USE SIGNAL ;
    PORT
      LAYER M4 ;
        RECT  215.808 23.292 216 23.316 ;
    END
  END g_front_2_u_front__f_t2[46]
  PIN g_front_2_u_front__f_t2[47]
    DIRECTION OUTPUT ;
    USE SIGNAL ;
    PORT
      LAYER M4 ;
        RECT  215.808 23.724 216 23.748 ;
    END
  END g_front_2_u_front__f_t2[47]
  PIN g_front_2_u_front__f_t2[48]
    DIRECTION OUTPUT ;
    USE SIGNAL ;
    PORT
      LAYER M4 ;
        RECT  215.808 24.156 216 24.18 ;
    END
  END g_front_2_u_front__f_t2[48]
  PIN g_front_2_u_front__f_t2[49]
    DIRECTION OUTPUT ;
    USE SIGNAL ;
    PORT
      LAYER M4 ;
        RECT  215.808 24.636 216 24.66 ;
    END
  END g_front_2_u_front__f_t2[49]
  PIN g_front_2_u_front__f_t2[4]
    DIRECTION OUTPUT ;
    USE SIGNAL ;
    PORT
      LAYER M4 ;
        RECT  215.808 4.188 216 4.212 ;
    END
  END g_front_2_u_front__f_t2[4]
  PIN g_front_2_u_front__f_t2[50]
    DIRECTION OUTPUT ;
    USE SIGNAL ;
    PORT
      LAYER M4 ;
        RECT  215.808 25.068 216 25.092 ;
    END
  END g_front_2_u_front__f_t2[50]
  PIN g_front_2_u_front__f_t2[51]
    DIRECTION OUTPUT ;
    USE SIGNAL ;
    PORT
      LAYER M4 ;
        RECT  215.808 25.548 216 25.572 ;
    END
  END g_front_2_u_front__f_t2[51]
  PIN g_front_2_u_front__f_t2[52]
    DIRECTION OUTPUT ;
    USE SIGNAL ;
    PORT
      LAYER M4 ;
        RECT  215.808 25.98 216 26.004 ;
    END
  END g_front_2_u_front__f_t2[52]
  PIN g_front_2_u_front__f_t2[53]
    DIRECTION OUTPUT ;
    USE SIGNAL ;
    PORT
      LAYER M4 ;
        RECT  215.808 26.46 216 26.484 ;
    END
  END g_front_2_u_front__f_t2[53]
  PIN g_front_2_u_front__f_t2[54]
    DIRECTION OUTPUT ;
    USE SIGNAL ;
    PORT
      LAYER M4 ;
        RECT  215.808 26.892 216 26.916 ;
    END
  END g_front_2_u_front__f_t2[54]
  PIN g_front_2_u_front__f_t2[55]
    DIRECTION OUTPUT ;
    USE SIGNAL ;
    PORT
      LAYER M4 ;
        RECT  215.808 27.372 216 27.396 ;
    END
  END g_front_2_u_front__f_t2[55]
  PIN g_front_2_u_front__f_t2[56]
    DIRECTION OUTPUT ;
    USE SIGNAL ;
    PORT
      LAYER M4 ;
        RECT  215.808 27.804 216 27.828 ;
    END
  END g_front_2_u_front__f_t2[56]
  PIN g_front_2_u_front__f_t2[57]
    DIRECTION OUTPUT ;
    USE SIGNAL ;
    PORT
      LAYER M4 ;
        RECT  215.808 28.284 216 28.308 ;
    END
  END g_front_2_u_front__f_t2[57]
  PIN g_front_2_u_front__f_t2[58]
    DIRECTION OUTPUT ;
    USE SIGNAL ;
    PORT
      LAYER M4 ;
        RECT  215.808 28.716 216 28.74 ;
    END
  END g_front_2_u_front__f_t2[58]
  PIN g_front_2_u_front__f_t2[59]
    DIRECTION OUTPUT ;
    USE SIGNAL ;
    PORT
      LAYER M4 ;
        RECT  215.808 29.196 216 29.22 ;
    END
  END g_front_2_u_front__f_t2[59]
  PIN g_front_2_u_front__f_t2[5]
    DIRECTION OUTPUT ;
    USE SIGNAL ;
    PORT
      LAYER M4 ;
        RECT  215.808 4.668 216 4.692 ;
    END
  END g_front_2_u_front__f_t2[5]
  PIN g_front_2_u_front__f_t2[60]
    DIRECTION OUTPUT ;
    USE SIGNAL ;
    PORT
      LAYER M4 ;
        RECT  215.808 29.628 216 29.652 ;
    END
  END g_front_2_u_front__f_t2[60]
  PIN g_front_2_u_front__f_t2[61]
    DIRECTION OUTPUT ;
    USE SIGNAL ;
    PORT
      LAYER M4 ;
        RECT  215.808 30.108 216 30.132 ;
    END
  END g_front_2_u_front__f_t2[61]
  PIN g_front_2_u_front__f_t2[62]
    DIRECTION OUTPUT ;
    USE SIGNAL ;
    PORT
      LAYER M4 ;
        RECT  215.808 30.54 216 30.564 ;
    END
  END g_front_2_u_front__f_t2[62]
  PIN g_front_2_u_front__f_t2[63]
    DIRECTION OUTPUT ;
    USE SIGNAL ;
    PORT
      LAYER M4 ;
        RECT  215.808 30.972 216 30.996 ;
    END
  END g_front_2_u_front__f_t2[63]
  PIN g_front_2_u_front__f_t2[64]
    DIRECTION OUTPUT ;
    USE SIGNAL ;
    PORT
      LAYER M4 ;
        RECT  215.808 31.452 216 31.476 ;
    END
  END g_front_2_u_front__f_t2[64]
  PIN g_front_2_u_front__f_t2[65]
    DIRECTION OUTPUT ;
    USE SIGNAL ;
    PORT
      LAYER M4 ;
        RECT  215.808 31.884 216 31.908 ;
    END
  END g_front_2_u_front__f_t2[65]
  PIN g_front_2_u_front__f_t2[66]
    DIRECTION OUTPUT ;
    USE SIGNAL ;
    PORT
      LAYER M4 ;
        RECT  215.808 32.364 216 32.388 ;
    END
  END g_front_2_u_front__f_t2[66]
  PIN g_front_2_u_front__f_t2[67]
    DIRECTION OUTPUT ;
    USE SIGNAL ;
    PORT
      LAYER M4 ;
        RECT  215.808 32.796 216 32.82 ;
    END
  END g_front_2_u_front__f_t2[67]
  PIN g_front_2_u_front__f_t2[68]
    DIRECTION OUTPUT ;
    USE SIGNAL ;
    PORT
      LAYER M4 ;
        RECT  215.808 33.276 216 33.3 ;
    END
  END g_front_2_u_front__f_t2[68]
  PIN g_front_2_u_front__f_t2[69]
    DIRECTION OUTPUT ;
    USE SIGNAL ;
    PORT
      LAYER M4 ;
        RECT  215.808 33.708 216 33.732 ;
    END
  END g_front_2_u_front__f_t2[69]
  PIN g_front_2_u_front__f_t2[6]
    DIRECTION OUTPUT ;
    USE SIGNAL ;
    PORT
      LAYER M4 ;
        RECT  215.808 5.1 216 5.124 ;
    END
  END g_front_2_u_front__f_t2[6]
  PIN g_front_2_u_front__f_t2[70]
    DIRECTION OUTPUT ;
    USE SIGNAL ;
    PORT
      LAYER M4 ;
        RECT  215.808 34.188 216 34.212 ;
    END
  END g_front_2_u_front__f_t2[70]
  PIN g_front_2_u_front__f_t2[71]
    DIRECTION OUTPUT ;
    USE SIGNAL ;
    PORT
      LAYER M4 ;
        RECT  215.808 34.62 216 34.644 ;
    END
  END g_front_2_u_front__f_t2[71]
  PIN g_front_2_u_front__f_t2[72]
    DIRECTION OUTPUT ;
    USE SIGNAL ;
    PORT
      LAYER M4 ;
        RECT  215.808 35.1 216 35.124 ;
    END
  END g_front_2_u_front__f_t2[72]
  PIN g_front_2_u_front__f_t2[73]
    DIRECTION OUTPUT ;
    USE SIGNAL ;
    PORT
      LAYER M4 ;
        RECT  215.808 35.532 216 35.556 ;
    END
  END g_front_2_u_front__f_t2[73]
  PIN g_front_2_u_front__f_t2[74]
    DIRECTION OUTPUT ;
    USE SIGNAL ;
    PORT
      LAYER M4 ;
        RECT  215.808 36.012 216 36.036 ;
    END
  END g_front_2_u_front__f_t2[74]
  PIN g_front_2_u_front__f_t2[75]
    DIRECTION OUTPUT ;
    USE SIGNAL ;
    PORT
      LAYER M4 ;
        RECT  215.808 36.444 216 36.468 ;
    END
  END g_front_2_u_front__f_t2[75]
  PIN g_front_2_u_front__f_t2[76]
    DIRECTION OUTPUT ;
    USE SIGNAL ;
    PORT
      LAYER M4 ;
        RECT  215.808 36.876 216 36.9 ;
    END
  END g_front_2_u_front__f_t2[76]
  PIN g_front_2_u_front__f_t2[77]
    DIRECTION OUTPUT ;
    USE SIGNAL ;
    PORT
      LAYER M4 ;
        RECT  215.808 37.356 216 37.38 ;
    END
  END g_front_2_u_front__f_t2[77]
  PIN g_front_2_u_front__f_t2[78]
    DIRECTION OUTPUT ;
    USE SIGNAL ;
    PORT
      LAYER M4 ;
        RECT  215.808 37.788 216 37.812 ;
    END
  END g_front_2_u_front__f_t2[78]
  PIN g_front_2_u_front__f_t2[79]
    DIRECTION OUTPUT ;
    USE SIGNAL ;
    PORT
      LAYER M4 ;
        RECT  215.808 38.268 216 38.292 ;
    END
  END g_front_2_u_front__f_t2[79]
  PIN g_front_2_u_front__f_t2[7]
    DIRECTION OUTPUT ;
    USE SIGNAL ;
    PORT
      LAYER M4 ;
        RECT  215.808 5.532 216 5.556 ;
    END
  END g_front_2_u_front__f_t2[7]
  PIN g_front_2_u_front__f_t2[80]
    DIRECTION OUTPUT ;
    USE SIGNAL ;
    PORT
      LAYER M4 ;
        RECT  215.808 38.7 216 38.724 ;
    END
  END g_front_2_u_front__f_t2[80]
  PIN g_front_2_u_front__f_t2[81]
    DIRECTION OUTPUT ;
    USE SIGNAL ;
    PORT
      LAYER M4 ;
        RECT  215.808 39.18 216 39.204 ;
    END
  END g_front_2_u_front__f_t2[81]
  PIN g_front_2_u_front__f_t2[82]
    DIRECTION OUTPUT ;
    USE SIGNAL ;
    PORT
      LAYER M4 ;
        RECT  215.808 39.612 216 39.636 ;
    END
  END g_front_2_u_front__f_t2[82]
  PIN g_front_2_u_front__f_t2[83]
    DIRECTION OUTPUT ;
    USE SIGNAL ;
    PORT
      LAYER M4 ;
        RECT  215.808 40.092 216 40.116 ;
    END
  END g_front_2_u_front__f_t2[83]
  PIN g_front_2_u_front__f_t2[84]
    DIRECTION OUTPUT ;
    USE SIGNAL ;
    PORT
      LAYER M4 ;
        RECT  215.808 40.524 216 40.548 ;
    END
  END g_front_2_u_front__f_t2[84]
  PIN g_front_2_u_front__f_t2[85]
    DIRECTION OUTPUT ;
    USE SIGNAL ;
    PORT
      LAYER M4 ;
        RECT  215.808 41.004 216 41.028 ;
    END
  END g_front_2_u_front__f_t2[85]
  PIN g_front_2_u_front__f_t2[86]
    DIRECTION OUTPUT ;
    USE SIGNAL ;
    PORT
      LAYER M4 ;
        RECT  215.808 41.436 216 41.46 ;
    END
  END g_front_2_u_front__f_t2[86]
  PIN g_front_2_u_front__f_t2[87]
    DIRECTION OUTPUT ;
    USE SIGNAL ;
    PORT
      LAYER M4 ;
        RECT  215.808 41.916 216 41.94 ;
    END
  END g_front_2_u_front__f_t2[87]
  PIN g_front_2_u_front__f_t2[88]
    DIRECTION OUTPUT ;
    USE SIGNAL ;
    PORT
      LAYER M4 ;
        RECT  215.808 42.348 216 42.372 ;
    END
  END g_front_2_u_front__f_t2[88]
  PIN g_front_2_u_front__f_t2[89]
    DIRECTION OUTPUT ;
    USE SIGNAL ;
    PORT
      LAYER M4 ;
        RECT  215.808 42.78 216 42.804 ;
    END
  END g_front_2_u_front__f_t2[89]
  PIN g_front_2_u_front__f_t2[8]
    DIRECTION OUTPUT ;
    USE SIGNAL ;
    PORT
      LAYER M4 ;
        RECT  215.808 6.012 216 6.036 ;
    END
  END g_front_2_u_front__f_t2[8]
  PIN g_front_2_u_front__f_t2[90]
    DIRECTION OUTPUT ;
    USE SIGNAL ;
    PORT
      LAYER M4 ;
        RECT  215.808 43.26 216 43.284 ;
    END
  END g_front_2_u_front__f_t2[90]
  PIN g_front_2_u_front__f_t2[91]
    DIRECTION OUTPUT ;
    USE SIGNAL ;
    PORT
      LAYER M4 ;
        RECT  215.808 43.692 216 43.716 ;
    END
  END g_front_2_u_front__f_t2[91]
  PIN g_front_2_u_front__f_t2[92]
    DIRECTION OUTPUT ;
    USE SIGNAL ;
    PORT
      LAYER M4 ;
        RECT  215.808 44.172 216 44.196 ;
    END
  END g_front_2_u_front__f_t2[92]
  PIN g_front_2_u_front__f_t2[93]
    DIRECTION OUTPUT ;
    USE SIGNAL ;
    PORT
      LAYER M4 ;
        RECT  215.808 44.604 216 44.628 ;
    END
  END g_front_2_u_front__f_t2[93]
  PIN g_front_2_u_front__f_t2[94]
    DIRECTION OUTPUT ;
    USE SIGNAL ;
    PORT
      LAYER M4 ;
        RECT  215.808 45.084 216 45.108 ;
    END
  END g_front_2_u_front__f_t2[94]
  PIN g_front_2_u_front__f_t2[95]
    DIRECTION OUTPUT ;
    USE SIGNAL ;
    PORT
      LAYER M4 ;
        RECT  215.808 45.516 216 45.54 ;
    END
  END g_front_2_u_front__f_t2[95]
  PIN g_front_2_u_front__f_t2[96]
    DIRECTION OUTPUT ;
    USE SIGNAL ;
    PORT
      LAYER M4 ;
        RECT  215.808 45.996 216 46.02 ;
    END
  END g_front_2_u_front__f_t2[96]
  PIN g_front_2_u_front__f_t2[97]
    DIRECTION OUTPUT ;
    USE SIGNAL ;
    PORT
      LAYER M4 ;
        RECT  215.808 46.428 216 46.452 ;
    END
  END g_front_2_u_front__f_t2[97]
  PIN g_front_2_u_front__f_t2[98]
    DIRECTION OUTPUT ;
    USE SIGNAL ;
    PORT
      LAYER M4 ;
        RECT  215.808 46.908 216 46.932 ;
    END
  END g_front_2_u_front__f_t2[98]
  PIN g_front_2_u_front__f_t2[99]
    DIRECTION OUTPUT ;
    USE SIGNAL ;
    PORT
      LAYER M4 ;
        RECT  215.808 47.34 216 47.364 ;
    END
  END g_front_2_u_front__f_t2[99]
  PIN g_front_2_u_front__f_t2[9]
    DIRECTION OUTPUT ;
    USE SIGNAL ;
    PORT
      LAYER M4 ;
        RECT  215.808 6.444 216 6.468 ;
    END
  END g_front_2_u_front__f_t2[9]
  PIN g_front_2_u_front__f_t3[0]
    DIRECTION OUTPUT ;
    USE SIGNAL ;
    PORT
      LAYER M4 ;
        RECT  215.808 108.204 216 108.228 ;
    END
  END g_front_2_u_front__f_t3[0]
  PIN g_front_2_u_front__f_t3[100]
    DIRECTION OUTPUT ;
    USE SIGNAL ;
    PORT
      LAYER M4 ;
        RECT  215.808 153.66 216 153.684 ;
    END
  END g_front_2_u_front__f_t3[100]
  PIN g_front_2_u_front__f_t3[101]
    DIRECTION OUTPUT ;
    USE SIGNAL ;
    PORT
      LAYER M4 ;
        RECT  215.808 154.092 216 154.116 ;
    END
  END g_front_2_u_front__f_t3[101]
  PIN g_front_2_u_front__f_t3[102]
    DIRECTION OUTPUT ;
    USE SIGNAL ;
    PORT
      LAYER M4 ;
        RECT  215.808 154.572 216 154.596 ;
    END
  END g_front_2_u_front__f_t3[102]
  PIN g_front_2_u_front__f_t3[103]
    DIRECTION OUTPUT ;
    USE SIGNAL ;
    PORT
      LAYER M4 ;
        RECT  215.808 155.004 216 155.028 ;
    END
  END g_front_2_u_front__f_t3[103]
  PIN g_front_2_u_front__f_t3[104]
    DIRECTION OUTPUT ;
    USE SIGNAL ;
    PORT
      LAYER M4 ;
        RECT  215.808 155.436 216 155.46 ;
    END
  END g_front_2_u_front__f_t3[104]
  PIN g_front_2_u_front__f_t3[105]
    DIRECTION OUTPUT ;
    USE SIGNAL ;
    PORT
      LAYER M4 ;
        RECT  215.808 155.916 216 155.94 ;
    END
  END g_front_2_u_front__f_t3[105]
  PIN g_front_2_u_front__f_t3[106]
    DIRECTION OUTPUT ;
    USE SIGNAL ;
    PORT
      LAYER M4 ;
        RECT  215.808 156.348 216 156.372 ;
    END
  END g_front_2_u_front__f_t3[106]
  PIN g_front_2_u_front__f_t3[107]
    DIRECTION OUTPUT ;
    USE SIGNAL ;
    PORT
      LAYER M4 ;
        RECT  215.808 156.828 216 156.852 ;
    END
  END g_front_2_u_front__f_t3[107]
  PIN g_front_2_u_front__f_t3[108]
    DIRECTION OUTPUT ;
    USE SIGNAL ;
    PORT
      LAYER M4 ;
        RECT  215.808 157.26 216 157.284 ;
    END
  END g_front_2_u_front__f_t3[108]
  PIN g_front_2_u_front__f_t3[109]
    DIRECTION OUTPUT ;
    USE SIGNAL ;
    PORT
      LAYER M4 ;
        RECT  215.808 157.74 216 157.764 ;
    END
  END g_front_2_u_front__f_t3[109]
  PIN g_front_2_u_front__f_t3[10]
    DIRECTION OUTPUT ;
    USE SIGNAL ;
    PORT
      LAYER M4 ;
        RECT  215.808 112.764 216 112.788 ;
    END
  END g_front_2_u_front__f_t3[10]
  PIN g_front_2_u_front__f_t3[110]
    DIRECTION OUTPUT ;
    USE SIGNAL ;
    PORT
      LAYER M4 ;
        RECT  215.808 158.172 216 158.196 ;
    END
  END g_front_2_u_front__f_t3[110]
  PIN g_front_2_u_front__f_t3[111]
    DIRECTION OUTPUT ;
    USE SIGNAL ;
    PORT
      LAYER M4 ;
        RECT  215.808 158.652 216 158.676 ;
    END
  END g_front_2_u_front__f_t3[111]
  PIN g_front_2_u_front__f_t3[112]
    DIRECTION OUTPUT ;
    USE SIGNAL ;
    PORT
      LAYER M4 ;
        RECT  215.808 159.084 216 159.108 ;
    END
  END g_front_2_u_front__f_t3[112]
  PIN g_front_2_u_front__f_t3[113]
    DIRECTION OUTPUT ;
    USE SIGNAL ;
    PORT
      LAYER M4 ;
        RECT  215.808 159.564 216 159.588 ;
    END
  END g_front_2_u_front__f_t3[113]
  PIN g_front_2_u_front__f_t3[114]
    DIRECTION OUTPUT ;
    USE SIGNAL ;
    PORT
      LAYER M4 ;
        RECT  215.808 159.996 216 160.02 ;
    END
  END g_front_2_u_front__f_t3[114]
  PIN g_front_2_u_front__f_t3[115]
    DIRECTION OUTPUT ;
    USE SIGNAL ;
    PORT
      LAYER M4 ;
        RECT  215.808 160.476 216 160.5 ;
    END
  END g_front_2_u_front__f_t3[115]
  PIN g_front_2_u_front__f_t3[116]
    DIRECTION OUTPUT ;
    USE SIGNAL ;
    PORT
      LAYER M4 ;
        RECT  215.808 160.908 216 160.932 ;
    END
  END g_front_2_u_front__f_t3[116]
  PIN g_front_2_u_front__f_t3[117]
    DIRECTION OUTPUT ;
    USE SIGNAL ;
    PORT
      LAYER M4 ;
        RECT  215.808 161.34 216 161.364 ;
    END
  END g_front_2_u_front__f_t3[117]
  PIN g_front_2_u_front__f_t3[118]
    DIRECTION OUTPUT ;
    USE SIGNAL ;
    PORT
      LAYER M4 ;
        RECT  215.808 161.82 216 161.844 ;
    END
  END g_front_2_u_front__f_t3[118]
  PIN g_front_2_u_front__f_t3[119]
    DIRECTION OUTPUT ;
    USE SIGNAL ;
    PORT
      LAYER M4 ;
        RECT  215.808 162.252 216 162.276 ;
    END
  END g_front_2_u_front__f_t3[119]
  PIN g_front_2_u_front__f_t3[11]
    DIRECTION OUTPUT ;
    USE SIGNAL ;
    PORT
      LAYER M4 ;
        RECT  215.808 113.196 216 113.22 ;
    END
  END g_front_2_u_front__f_t3[11]
  PIN g_front_2_u_front__f_t3[120]
    DIRECTION OUTPUT ;
    USE SIGNAL ;
    PORT
      LAYER M4 ;
        RECT  215.808 162.732 216 162.756 ;
    END
  END g_front_2_u_front__f_t3[120]
  PIN g_front_2_u_front__f_t3[121]
    DIRECTION OUTPUT ;
    USE SIGNAL ;
    PORT
      LAYER M4 ;
        RECT  215.808 163.164 216 163.188 ;
    END
  END g_front_2_u_front__f_t3[121]
  PIN g_front_2_u_front__f_t3[122]
    DIRECTION OUTPUT ;
    USE SIGNAL ;
    PORT
      LAYER M4 ;
        RECT  215.808 163.644 216 163.668 ;
    END
  END g_front_2_u_front__f_t3[122]
  PIN g_front_2_u_front__f_t3[123]
    DIRECTION OUTPUT ;
    USE SIGNAL ;
    PORT
      LAYER M4 ;
        RECT  215.808 164.076 216 164.1 ;
    END
  END g_front_2_u_front__f_t3[123]
  PIN g_front_2_u_front__f_t3[124]
    DIRECTION OUTPUT ;
    USE SIGNAL ;
    PORT
      LAYER M4 ;
        RECT  215.808 164.556 216 164.58 ;
    END
  END g_front_2_u_front__f_t3[124]
  PIN g_front_2_u_front__f_t3[125]
    DIRECTION OUTPUT ;
    USE SIGNAL ;
    PORT
      LAYER M4 ;
        RECT  215.808 164.988 216 165.012 ;
    END
  END g_front_2_u_front__f_t3[125]
  PIN g_front_2_u_front__f_t3[126]
    DIRECTION OUTPUT ;
    USE SIGNAL ;
    PORT
      LAYER M4 ;
        RECT  215.808 165.468 216 165.492 ;
    END
  END g_front_2_u_front__f_t3[126]
  PIN g_front_2_u_front__f_t3[127]
    DIRECTION OUTPUT ;
    USE SIGNAL ;
    PORT
      LAYER M4 ;
        RECT  215.808 165.9 216 165.924 ;
    END
  END g_front_2_u_front__f_t3[127]
  PIN g_front_2_u_front__f_t3[128]
    DIRECTION OUTPUT ;
    USE SIGNAL ;
    PORT
      LAYER M4 ;
        RECT  215.808 166.38 216 166.404 ;
    END
  END g_front_2_u_front__f_t3[128]
  PIN g_front_2_u_front__f_t3[129]
    DIRECTION OUTPUT ;
    USE SIGNAL ;
    PORT
      LAYER M4 ;
        RECT  215.808 166.812 216 166.836 ;
    END
  END g_front_2_u_front__f_t3[129]
  PIN g_front_2_u_front__f_t3[12]
    DIRECTION OUTPUT ;
    USE SIGNAL ;
    PORT
      LAYER M4 ;
        RECT  215.808 113.676 216 113.7 ;
    END
  END g_front_2_u_front__f_t3[12]
  PIN g_front_2_u_front__f_t3[130]
    DIRECTION OUTPUT ;
    USE SIGNAL ;
    PORT
      LAYER M4 ;
        RECT  215.808 167.244 216 167.268 ;
    END
  END g_front_2_u_front__f_t3[130]
  PIN g_front_2_u_front__f_t3[131]
    DIRECTION OUTPUT ;
    USE SIGNAL ;
    PORT
      LAYER M4 ;
        RECT  215.808 167.724 216 167.748 ;
    END
  END g_front_2_u_front__f_t3[131]
  PIN g_front_2_u_front__f_t3[132]
    DIRECTION OUTPUT ;
    USE SIGNAL ;
    PORT
      LAYER M4 ;
        RECT  215.808 168.156 216 168.18 ;
    END
  END g_front_2_u_front__f_t3[132]
  PIN g_front_2_u_front__f_t3[133]
    DIRECTION OUTPUT ;
    USE SIGNAL ;
    PORT
      LAYER M4 ;
        RECT  215.808 168.636 216 168.66 ;
    END
  END g_front_2_u_front__f_t3[133]
  PIN g_front_2_u_front__f_t3[134]
    DIRECTION OUTPUT ;
    USE SIGNAL ;
    PORT
      LAYER M4 ;
        RECT  215.808 169.068 216 169.092 ;
    END
  END g_front_2_u_front__f_t3[134]
  PIN g_front_2_u_front__f_t3[135]
    DIRECTION OUTPUT ;
    USE SIGNAL ;
    PORT
      LAYER M4 ;
        RECT  215.808 169.548 216 169.572 ;
    END
  END g_front_2_u_front__f_t3[135]
  PIN g_front_2_u_front__f_t3[136]
    DIRECTION OUTPUT ;
    USE SIGNAL ;
    PORT
      LAYER M4 ;
        RECT  215.808 169.98 216 170.004 ;
    END
  END g_front_2_u_front__f_t3[136]
  PIN g_front_2_u_front__f_t3[137]
    DIRECTION OUTPUT ;
    USE SIGNAL ;
    PORT
      LAYER M4 ;
        RECT  215.808 170.46 216 170.484 ;
    END
  END g_front_2_u_front__f_t3[137]
  PIN g_front_2_u_front__f_t3[138]
    DIRECTION OUTPUT ;
    USE SIGNAL ;
    PORT
      LAYER M4 ;
        RECT  215.808 170.892 216 170.916 ;
    END
  END g_front_2_u_front__f_t3[138]
  PIN g_front_2_u_front__f_t3[139]
    DIRECTION OUTPUT ;
    USE SIGNAL ;
    PORT
      LAYER M4 ;
        RECT  215.808 171.372 216 171.396 ;
    END
  END g_front_2_u_front__f_t3[139]
  PIN g_front_2_u_front__f_t3[13]
    DIRECTION OUTPUT ;
    USE SIGNAL ;
    PORT
      LAYER M4 ;
        RECT  215.808 114.108 216 114.132 ;
    END
  END g_front_2_u_front__f_t3[13]
  PIN g_front_2_u_front__f_t3[140]
    DIRECTION OUTPUT ;
    USE SIGNAL ;
    PORT
      LAYER M4 ;
        RECT  215.808 171.804 216 171.828 ;
    END
  END g_front_2_u_front__f_t3[140]
  PIN g_front_2_u_front__f_t3[141]
    DIRECTION OUTPUT ;
    USE SIGNAL ;
    PORT
      LAYER M4 ;
        RECT  215.808 172.284 216 172.308 ;
    END
  END g_front_2_u_front__f_t3[141]
  PIN g_front_2_u_front__f_t3[142]
    DIRECTION OUTPUT ;
    USE SIGNAL ;
    PORT
      LAYER M4 ;
        RECT  215.808 172.716 216 172.74 ;
    END
  END g_front_2_u_front__f_t3[142]
  PIN g_front_2_u_front__f_t3[143]
    DIRECTION OUTPUT ;
    USE SIGNAL ;
    PORT
      LAYER M4 ;
        RECT  215.808 173.196 216 173.22 ;
    END
  END g_front_2_u_front__f_t3[143]
  PIN g_front_2_u_front__f_t3[144]
    DIRECTION OUTPUT ;
    USE SIGNAL ;
    PORT
      LAYER M4 ;
        RECT  215.808 173.628 216 173.652 ;
    END
  END g_front_2_u_front__f_t3[144]
  PIN g_front_2_u_front__f_t3[145]
    DIRECTION OUTPUT ;
    USE SIGNAL ;
    PORT
      LAYER M4 ;
        RECT  215.808 174.06 216 174.084 ;
    END
  END g_front_2_u_front__f_t3[145]
  PIN g_front_2_u_front__f_t3[146]
    DIRECTION OUTPUT ;
    USE SIGNAL ;
    PORT
      LAYER M4 ;
        RECT  215.808 174.54 216 174.564 ;
    END
  END g_front_2_u_front__f_t3[146]
  PIN g_front_2_u_front__f_t3[147]
    DIRECTION OUTPUT ;
    USE SIGNAL ;
    PORT
      LAYER M4 ;
        RECT  215.808 174.972 216 174.996 ;
    END
  END g_front_2_u_front__f_t3[147]
  PIN g_front_2_u_front__f_t3[148]
    DIRECTION OUTPUT ;
    USE SIGNAL ;
    PORT
      LAYER M4 ;
        RECT  215.808 175.452 216 175.476 ;
    END
  END g_front_2_u_front__f_t3[148]
  PIN g_front_2_u_front__f_t3[149]
    DIRECTION OUTPUT ;
    USE SIGNAL ;
    PORT
      LAYER M4 ;
        RECT  215.808 175.884 216 175.908 ;
    END
  END g_front_2_u_front__f_t3[149]
  PIN g_front_2_u_front__f_t3[14]
    DIRECTION OUTPUT ;
    USE SIGNAL ;
    PORT
      LAYER M4 ;
        RECT  215.808 114.588 216 114.612 ;
    END
  END g_front_2_u_front__f_t3[14]
  PIN g_front_2_u_front__f_t3[150]
    DIRECTION OUTPUT ;
    USE SIGNAL ;
    PORT
      LAYER M4 ;
        RECT  215.808 176.364 216 176.388 ;
    END
  END g_front_2_u_front__f_t3[150]
  PIN g_front_2_u_front__f_t3[151]
    DIRECTION OUTPUT ;
    USE SIGNAL ;
    PORT
      LAYER M4 ;
        RECT  215.808 176.796 216 176.82 ;
    END
  END g_front_2_u_front__f_t3[151]
  PIN g_front_2_u_front__f_t3[152]
    DIRECTION OUTPUT ;
    USE SIGNAL ;
    PORT
      LAYER M4 ;
        RECT  215.808 177.276 216 177.3 ;
    END
  END g_front_2_u_front__f_t3[152]
  PIN g_front_2_u_front__f_t3[153]
    DIRECTION OUTPUT ;
    USE SIGNAL ;
    PORT
      LAYER M4 ;
        RECT  215.808 177.708 216 177.732 ;
    END
  END g_front_2_u_front__f_t3[153]
  PIN g_front_2_u_front__f_t3[154]
    DIRECTION OUTPUT ;
    USE SIGNAL ;
    PORT
      LAYER M4 ;
        RECT  215.808 178.188 216 178.212 ;
    END
  END g_front_2_u_front__f_t3[154]
  PIN g_front_2_u_front__f_t3[155]
    DIRECTION OUTPUT ;
    USE SIGNAL ;
    PORT
      LAYER M4 ;
        RECT  215.808 178.62 216 178.644 ;
    END
  END g_front_2_u_front__f_t3[155]
  PIN g_front_2_u_front__f_t3[156]
    DIRECTION OUTPUT ;
    USE SIGNAL ;
    PORT
      LAYER M4 ;
        RECT  215.808 179.1 216 179.124 ;
    END
  END g_front_2_u_front__f_t3[156]
  PIN g_front_2_u_front__f_t3[157]
    DIRECTION OUTPUT ;
    USE SIGNAL ;
    PORT
      LAYER M4 ;
        RECT  215.808 179.532 216 179.556 ;
    END
  END g_front_2_u_front__f_t3[157]
  PIN g_front_2_u_front__f_t3[158]
    DIRECTION OUTPUT ;
    USE SIGNAL ;
    PORT
      LAYER M4 ;
        RECT  215.808 179.964 216 179.988 ;
    END
  END g_front_2_u_front__f_t3[158]
  PIN g_front_2_u_front__f_t3[159]
    DIRECTION OUTPUT ;
    USE SIGNAL ;
    PORT
      LAYER M4 ;
        RECT  215.808 180.444 216 180.468 ;
    END
  END g_front_2_u_front__f_t3[159]
  PIN g_front_2_u_front__f_t3[15]
    DIRECTION OUTPUT ;
    USE SIGNAL ;
    PORT
      LAYER M4 ;
        RECT  215.808 115.02 216 115.044 ;
    END
  END g_front_2_u_front__f_t3[15]
  PIN g_front_2_u_front__f_t3[160]
    DIRECTION OUTPUT ;
    USE SIGNAL ;
    PORT
      LAYER M4 ;
        RECT  215.808 180.876 216 180.9 ;
    END
  END g_front_2_u_front__f_t3[160]
  PIN g_front_2_u_front__f_t3[161]
    DIRECTION OUTPUT ;
    USE SIGNAL ;
    PORT
      LAYER M4 ;
        RECT  215.808 181.356 216 181.38 ;
    END
  END g_front_2_u_front__f_t3[161]
  PIN g_front_2_u_front__f_t3[162]
    DIRECTION OUTPUT ;
    USE SIGNAL ;
    PORT
      LAYER M4 ;
        RECT  215.808 181.788 216 181.812 ;
    END
  END g_front_2_u_front__f_t3[162]
  PIN g_front_2_u_front__f_t3[163]
    DIRECTION OUTPUT ;
    USE SIGNAL ;
    PORT
      LAYER M4 ;
        RECT  215.808 182.268 216 182.292 ;
    END
  END g_front_2_u_front__f_t3[163]
  PIN g_front_2_u_front__f_t3[164]
    DIRECTION OUTPUT ;
    USE SIGNAL ;
    PORT
      LAYER M4 ;
        RECT  215.808 182.7 216 182.724 ;
    END
  END g_front_2_u_front__f_t3[164]
  PIN g_front_2_u_front__f_t3[165]
    DIRECTION OUTPUT ;
    USE SIGNAL ;
    PORT
      LAYER M4 ;
        RECT  215.808 183.18 216 183.204 ;
    END
  END g_front_2_u_front__f_t3[165]
  PIN g_front_2_u_front__f_t3[166]
    DIRECTION OUTPUT ;
    USE SIGNAL ;
    PORT
      LAYER M4 ;
        RECT  215.808 183.612 216 183.636 ;
    END
  END g_front_2_u_front__f_t3[166]
  PIN g_front_2_u_front__f_t3[167]
    DIRECTION OUTPUT ;
    USE SIGNAL ;
    PORT
      LAYER M4 ;
        RECT  215.808 184.092 216 184.116 ;
    END
  END g_front_2_u_front__f_t3[167]
  PIN g_front_2_u_front__f_t3[168]
    DIRECTION OUTPUT ;
    USE SIGNAL ;
    PORT
      LAYER M4 ;
        RECT  215.808 184.524 216 184.548 ;
    END
  END g_front_2_u_front__f_t3[168]
  PIN g_front_2_u_front__f_t3[169]
    DIRECTION OUTPUT ;
    USE SIGNAL ;
    PORT
      LAYER M4 ;
        RECT  215.808 185.004 216 185.028 ;
    END
  END g_front_2_u_front__f_t3[169]
  PIN g_front_2_u_front__f_t3[16]
    DIRECTION OUTPUT ;
    USE SIGNAL ;
    PORT
      LAYER M4 ;
        RECT  215.808 115.5 216 115.524 ;
    END
  END g_front_2_u_front__f_t3[16]
  PIN g_front_2_u_front__f_t3[170]
    DIRECTION OUTPUT ;
    USE SIGNAL ;
    PORT
      LAYER M4 ;
        RECT  215.808 185.436 216 185.46 ;
    END
  END g_front_2_u_front__f_t3[170]
  PIN g_front_2_u_front__f_t3[171]
    DIRECTION OUTPUT ;
    USE SIGNAL ;
    PORT
      LAYER M4 ;
        RECT  215.808 185.868 216 185.892 ;
    END
  END g_front_2_u_front__f_t3[171]
  PIN g_front_2_u_front__f_t3[172]
    DIRECTION OUTPUT ;
    USE SIGNAL ;
    PORT
      LAYER M4 ;
        RECT  215.808 186.348 216 186.372 ;
    END
  END g_front_2_u_front__f_t3[172]
  PIN g_front_2_u_front__f_t3[173]
    DIRECTION OUTPUT ;
    USE SIGNAL ;
    PORT
      LAYER M4 ;
        RECT  215.808 186.78 216 186.804 ;
    END
  END g_front_2_u_front__f_t3[173]
  PIN g_front_2_u_front__f_t3[174]
    DIRECTION OUTPUT ;
    USE SIGNAL ;
    PORT
      LAYER M4 ;
        RECT  215.808 187.26 216 187.284 ;
    END
  END g_front_2_u_front__f_t3[174]
  PIN g_front_2_u_front__f_t3[175]
    DIRECTION OUTPUT ;
    USE SIGNAL ;
    PORT
      LAYER M4 ;
        RECT  215.808 187.692 216 187.716 ;
    END
  END g_front_2_u_front__f_t3[175]
  PIN g_front_2_u_front__f_t3[176]
    DIRECTION OUTPUT ;
    USE SIGNAL ;
    PORT
      LAYER M4 ;
        RECT  215.808 188.172 216 188.196 ;
    END
  END g_front_2_u_front__f_t3[176]
  PIN g_front_2_u_front__f_t3[177]
    DIRECTION OUTPUT ;
    USE SIGNAL ;
    PORT
      LAYER M4 ;
        RECT  215.808 188.604 216 188.628 ;
    END
  END g_front_2_u_front__f_t3[177]
  PIN g_front_2_u_front__f_t3[178]
    DIRECTION OUTPUT ;
    USE SIGNAL ;
    PORT
      LAYER M4 ;
        RECT  215.808 189.084 216 189.108 ;
    END
  END g_front_2_u_front__f_t3[178]
  PIN g_front_2_u_front__f_t3[179]
    DIRECTION OUTPUT ;
    USE SIGNAL ;
    PORT
      LAYER M4 ;
        RECT  215.808 189.516 216 189.54 ;
    END
  END g_front_2_u_front__f_t3[179]
  PIN g_front_2_u_front__f_t3[17]
    DIRECTION OUTPUT ;
    USE SIGNAL ;
    PORT
      LAYER M4 ;
        RECT  215.808 115.932 216 115.956 ;
    END
  END g_front_2_u_front__f_t3[17]
  PIN g_front_2_u_front__f_t3[180]
    DIRECTION OUTPUT ;
    USE SIGNAL ;
    PORT
      LAYER M4 ;
        RECT  215.808 189.996 216 190.02 ;
    END
  END g_front_2_u_front__f_t3[180]
  PIN g_front_2_u_front__f_t3[181]
    DIRECTION OUTPUT ;
    USE SIGNAL ;
    PORT
      LAYER M4 ;
        RECT  215.808 190.428 216 190.452 ;
    END
  END g_front_2_u_front__f_t3[181]
  PIN g_front_2_u_front__f_t3[182]
    DIRECTION OUTPUT ;
    USE SIGNAL ;
    PORT
      LAYER M4 ;
        RECT  215.808 190.908 216 190.932 ;
    END
  END g_front_2_u_front__f_t3[182]
  PIN g_front_2_u_front__f_t3[183]
    DIRECTION OUTPUT ;
    USE SIGNAL ;
    PORT
      LAYER M4 ;
        RECT  215.808 191.34 216 191.364 ;
    END
  END g_front_2_u_front__f_t3[183]
  PIN g_front_2_u_front__f_t3[184]
    DIRECTION OUTPUT ;
    USE SIGNAL ;
    PORT
      LAYER M4 ;
        RECT  215.808 191.82 216 191.844 ;
    END
  END g_front_2_u_front__f_t3[184]
  PIN g_front_2_u_front__f_t3[185]
    DIRECTION OUTPUT ;
    USE SIGNAL ;
    PORT
      LAYER M4 ;
        RECT  215.808 192.252 216 192.276 ;
    END
  END g_front_2_u_front__f_t3[185]
  PIN g_front_2_u_front__f_t3[186]
    DIRECTION OUTPUT ;
    USE SIGNAL ;
    PORT
      LAYER M4 ;
        RECT  215.808 192.684 216 192.708 ;
    END
  END g_front_2_u_front__f_t3[186]
  PIN g_front_2_u_front__f_t3[187]
    DIRECTION OUTPUT ;
    USE SIGNAL ;
    PORT
      LAYER M4 ;
        RECT  215.808 193.164 216 193.188 ;
    END
  END g_front_2_u_front__f_t3[187]
  PIN g_front_2_u_front__f_t3[188]
    DIRECTION OUTPUT ;
    USE SIGNAL ;
    PORT
      LAYER M4 ;
        RECT  215.808 193.596 216 193.62 ;
    END
  END g_front_2_u_front__f_t3[188]
  PIN g_front_2_u_front__f_t3[189]
    DIRECTION OUTPUT ;
    USE SIGNAL ;
    PORT
      LAYER M4 ;
        RECT  215.808 194.076 216 194.1 ;
    END
  END g_front_2_u_front__f_t3[189]
  PIN g_front_2_u_front__f_t3[18]
    DIRECTION OUTPUT ;
    USE SIGNAL ;
    PORT
      LAYER M4 ;
        RECT  215.808 116.412 216 116.436 ;
    END
  END g_front_2_u_front__f_t3[18]
  PIN g_front_2_u_front__f_t3[190]
    DIRECTION OUTPUT ;
    USE SIGNAL ;
    PORT
      LAYER M4 ;
        RECT  215.808 194.508 216 194.532 ;
    END
  END g_front_2_u_front__f_t3[190]
  PIN g_front_2_u_front__f_t3[191]
    DIRECTION OUTPUT ;
    USE SIGNAL ;
    PORT
      LAYER M4 ;
        RECT  215.808 194.988 216 195.012 ;
    END
  END g_front_2_u_front__f_t3[191]
  PIN g_front_2_u_front__f_t3[192]
    DIRECTION OUTPUT ;
    USE SIGNAL ;
    PORT
      LAYER M4 ;
        RECT  215.808 195.42 216 195.444 ;
    END
  END g_front_2_u_front__f_t3[192]
  PIN g_front_2_u_front__f_t3[193]
    DIRECTION OUTPUT ;
    USE SIGNAL ;
    PORT
      LAYER M4 ;
        RECT  215.808 195.9 216 195.924 ;
    END
  END g_front_2_u_front__f_t3[193]
  PIN g_front_2_u_front__f_t3[194]
    DIRECTION OUTPUT ;
    USE SIGNAL ;
    PORT
      LAYER M4 ;
        RECT  215.808 196.332 216 196.356 ;
    END
  END g_front_2_u_front__f_t3[194]
  PIN g_front_2_u_front__f_t3[195]
    DIRECTION OUTPUT ;
    USE SIGNAL ;
    PORT
      LAYER M4 ;
        RECT  215.808 196.812 216 196.836 ;
    END
  END g_front_2_u_front__f_t3[195]
  PIN g_front_2_u_front__f_t3[196]
    DIRECTION OUTPUT ;
    USE SIGNAL ;
    PORT
      LAYER M4 ;
        RECT  215.808 197.244 216 197.268 ;
    END
  END g_front_2_u_front__f_t3[196]
  PIN g_front_2_u_front__f_t3[197]
    DIRECTION OUTPUT ;
    USE SIGNAL ;
    PORT
      LAYER M4 ;
        RECT  215.808 197.724 216 197.748 ;
    END
  END g_front_2_u_front__f_t3[197]
  PIN g_front_2_u_front__f_t3[198]
    DIRECTION OUTPUT ;
    USE SIGNAL ;
    PORT
      LAYER M4 ;
        RECT  215.808 198.156 216 198.18 ;
    END
  END g_front_2_u_front__f_t3[198]
  PIN g_front_2_u_front__f_t3[199]
    DIRECTION OUTPUT ;
    USE SIGNAL ;
    PORT
      LAYER M4 ;
        RECT  215.808 198.588 216 198.612 ;
    END
  END g_front_2_u_front__f_t3[199]
  PIN g_front_2_u_front__f_t3[19]
    DIRECTION OUTPUT ;
    USE SIGNAL ;
    PORT
      LAYER M4 ;
        RECT  215.808 116.844 216 116.868 ;
    END
  END g_front_2_u_front__f_t3[19]
  PIN g_front_2_u_front__f_t3[1]
    DIRECTION OUTPUT ;
    USE SIGNAL ;
    PORT
      LAYER M4 ;
        RECT  215.808 108.684 216 108.708 ;
    END
  END g_front_2_u_front__f_t3[1]
  PIN g_front_2_u_front__f_t3[200]
    DIRECTION OUTPUT ;
    USE SIGNAL ;
    PORT
      LAYER M4 ;
        RECT  215.808 199.068 216 199.092 ;
    END
  END g_front_2_u_front__f_t3[200]
  PIN g_front_2_u_front__f_t3[201]
    DIRECTION OUTPUT ;
    USE SIGNAL ;
    PORT
      LAYER M4 ;
        RECT  215.808 199.5 216 199.524 ;
    END
  END g_front_2_u_front__f_t3[201]
  PIN g_front_2_u_front__f_t3[202]
    DIRECTION OUTPUT ;
    USE SIGNAL ;
    PORT
      LAYER M4 ;
        RECT  215.808 199.98 216 200.004 ;
    END
  END g_front_2_u_front__f_t3[202]
  PIN g_front_2_u_front__f_t3[203]
    DIRECTION OUTPUT ;
    USE SIGNAL ;
    PORT
      LAYER M4 ;
        RECT  215.808 200.412 216 200.436 ;
    END
  END g_front_2_u_front__f_t3[203]
  PIN g_front_2_u_front__f_t3[204]
    DIRECTION OUTPUT ;
    USE SIGNAL ;
    PORT
      LAYER M4 ;
        RECT  215.808 200.892 216 200.916 ;
    END
  END g_front_2_u_front__f_t3[204]
  PIN g_front_2_u_front__f_t3[205]
    DIRECTION OUTPUT ;
    USE SIGNAL ;
    PORT
      LAYER M4 ;
        RECT  215.808 201.324 216 201.348 ;
    END
  END g_front_2_u_front__f_t3[205]
  PIN g_front_2_u_front__f_t3[206]
    DIRECTION OUTPUT ;
    USE SIGNAL ;
    PORT
      LAYER M4 ;
        RECT  215.808 201.804 216 201.828 ;
    END
  END g_front_2_u_front__f_t3[206]
  PIN g_front_2_u_front__f_t3[207]
    DIRECTION OUTPUT ;
    USE SIGNAL ;
    PORT
      LAYER M4 ;
        RECT  215.808 202.236 216 202.26 ;
    END
  END g_front_2_u_front__f_t3[207]
  PIN g_front_2_u_front__f_t3[208]
    DIRECTION OUTPUT ;
    USE SIGNAL ;
    PORT
      LAYER M4 ;
        RECT  215.808 202.716 216 202.74 ;
    END
  END g_front_2_u_front__f_t3[208]
  PIN g_front_2_u_front__f_t3[209]
    DIRECTION OUTPUT ;
    USE SIGNAL ;
    PORT
      LAYER M4 ;
        RECT  215.808 203.148 216 203.172 ;
    END
  END g_front_2_u_front__f_t3[209]
  PIN g_front_2_u_front__f_t3[20]
    DIRECTION OUTPUT ;
    USE SIGNAL ;
    PORT
      LAYER M4 ;
        RECT  215.808 117.324 216 117.348 ;
    END
  END g_front_2_u_front__f_t3[20]
  PIN g_front_2_u_front__f_t3[210]
    DIRECTION OUTPUT ;
    USE SIGNAL ;
    PORT
      LAYER M4 ;
        RECT  215.808 203.628 216 203.652 ;
    END
  END g_front_2_u_front__f_t3[210]
  PIN g_front_2_u_front__f_t3[211]
    DIRECTION OUTPUT ;
    USE SIGNAL ;
    PORT
      LAYER M4 ;
        RECT  215.808 204.06 216 204.084 ;
    END
  END g_front_2_u_front__f_t3[211]
  PIN g_front_2_u_front__f_t3[212]
    DIRECTION OUTPUT ;
    USE SIGNAL ;
    PORT
      LAYER M4 ;
        RECT  215.808 204.492 216 204.516 ;
    END
  END g_front_2_u_front__f_t3[212]
  PIN g_front_2_u_front__f_t3[213]
    DIRECTION OUTPUT ;
    USE SIGNAL ;
    PORT
      LAYER M4 ;
        RECT  215.808 204.972 216 204.996 ;
    END
  END g_front_2_u_front__f_t3[213]
  PIN g_front_2_u_front__f_t3[214]
    DIRECTION OUTPUT ;
    USE SIGNAL ;
    PORT
      LAYER M4 ;
        RECT  215.808 205.404 216 205.428 ;
    END
  END g_front_2_u_front__f_t3[214]
  PIN g_front_2_u_front__f_t3[215]
    DIRECTION OUTPUT ;
    USE SIGNAL ;
    PORT
      LAYER M4 ;
        RECT  215.808 205.884 216 205.908 ;
    END
  END g_front_2_u_front__f_t3[215]
  PIN g_front_2_u_front__f_t3[216]
    DIRECTION OUTPUT ;
    USE SIGNAL ;
    PORT
      LAYER M4 ;
        RECT  215.808 206.316 216 206.34 ;
    END
  END g_front_2_u_front__f_t3[216]
  PIN g_front_2_u_front__f_t3[217]
    DIRECTION OUTPUT ;
    USE SIGNAL ;
    PORT
      LAYER M4 ;
        RECT  215.808 206.796 216 206.82 ;
    END
  END g_front_2_u_front__f_t3[217]
  PIN g_front_2_u_front__f_t3[218]
    DIRECTION OUTPUT ;
    USE SIGNAL ;
    PORT
      LAYER M4 ;
        RECT  215.808 207.228 216 207.252 ;
    END
  END g_front_2_u_front__f_t3[218]
  PIN g_front_2_u_front__f_t3[219]
    DIRECTION OUTPUT ;
    USE SIGNAL ;
    PORT
      LAYER M4 ;
        RECT  215.808 207.708 216 207.732 ;
    END
  END g_front_2_u_front__f_t3[219]
  PIN g_front_2_u_front__f_t3[21]
    DIRECTION OUTPUT ;
    USE SIGNAL ;
    PORT
      LAYER M4 ;
        RECT  215.808 117.756 216 117.78 ;
    END
  END g_front_2_u_front__f_t3[21]
  PIN g_front_2_u_front__f_t3[220]
    DIRECTION OUTPUT ;
    USE SIGNAL ;
    PORT
      LAYER M4 ;
        RECT  215.808 208.14 216 208.164 ;
    END
  END g_front_2_u_front__f_t3[220]
  PIN g_front_2_u_front__f_t3[221]
    DIRECTION OUTPUT ;
    USE SIGNAL ;
    PORT
      LAYER M4 ;
        RECT  215.808 208.62 216 208.644 ;
    END
  END g_front_2_u_front__f_t3[221]
  PIN g_front_2_u_front__f_t3[222]
    DIRECTION OUTPUT ;
    USE SIGNAL ;
    PORT
      LAYER M4 ;
        RECT  215.808 209.052 216 209.076 ;
    END
  END g_front_2_u_front__f_t3[222]
  PIN g_front_2_u_front__f_t3[223]
    DIRECTION OUTPUT ;
    USE SIGNAL ;
    PORT
      LAYER M4 ;
        RECT  215.808 209.532 216 209.556 ;
    END
  END g_front_2_u_front__f_t3[223]
  PIN g_front_2_u_front__f_t3[224]
    DIRECTION OUTPUT ;
    USE SIGNAL ;
    PORT
      LAYER M4 ;
        RECT  215.808 209.964 216 209.988 ;
    END
  END g_front_2_u_front__f_t3[224]
  PIN g_front_2_u_front__f_t3[225]
    DIRECTION OUTPUT ;
    USE SIGNAL ;
    PORT
      LAYER M4 ;
        RECT  215.808 210.444 216 210.468 ;
    END
  END g_front_2_u_front__f_t3[225]
  PIN g_front_2_u_front__f_t3[226]
    DIRECTION OUTPUT ;
    USE SIGNAL ;
    PORT
      LAYER M4 ;
        RECT  215.808 210.876 216 210.9 ;
    END
  END g_front_2_u_front__f_t3[226]
  PIN g_front_2_u_front__f_t3[227]
    DIRECTION OUTPUT ;
    USE SIGNAL ;
    PORT
      LAYER M4 ;
        RECT  215.808 211.308 216 211.332 ;
    END
  END g_front_2_u_front__f_t3[227]
  PIN g_front_2_u_front__f_t3[228]
    DIRECTION OUTPUT ;
    USE SIGNAL ;
    PORT
      LAYER M4 ;
        RECT  215.808 211.788 216 211.812 ;
    END
  END g_front_2_u_front__f_t3[228]
  PIN g_front_2_u_front__f_t3[229]
    DIRECTION OUTPUT ;
    USE SIGNAL ;
    PORT
      LAYER M4 ;
        RECT  215.808 212.22 216 212.244 ;
    END
  END g_front_2_u_front__f_t3[229]
  PIN g_front_2_u_front__f_t3[22]
    DIRECTION OUTPUT ;
    USE SIGNAL ;
    PORT
      LAYER M4 ;
        RECT  215.808 118.188 216 118.212 ;
    END
  END g_front_2_u_front__f_t3[22]
  PIN g_front_2_u_front__f_t3[230]
    DIRECTION OUTPUT ;
    USE SIGNAL ;
    PORT
      LAYER M4 ;
        RECT  215.808 212.7 216 212.724 ;
    END
  END g_front_2_u_front__f_t3[230]
  PIN g_front_2_u_front__f_t3[231]
    DIRECTION OUTPUT ;
    USE SIGNAL ;
    PORT
      LAYER M4 ;
        RECT  215.808 213.132 216 213.156 ;
    END
  END g_front_2_u_front__f_t3[231]
  PIN g_front_2_u_front__f_t3[232]
    DIRECTION OUTPUT ;
    USE SIGNAL ;
    PORT
      LAYER M4 ;
        RECT  215.808 213.612 216 213.636 ;
    END
  END g_front_2_u_front__f_t3[232]
  PIN g_front_2_u_front__f_t3[23]
    DIRECTION OUTPUT ;
    USE SIGNAL ;
    PORT
      LAYER M4 ;
        RECT  215.808 118.668 216 118.692 ;
    END
  END g_front_2_u_front__f_t3[23]
  PIN g_front_2_u_front__f_t3[24]
    DIRECTION OUTPUT ;
    USE SIGNAL ;
    PORT
      LAYER M4 ;
        RECT  215.808 119.1 216 119.124 ;
    END
  END g_front_2_u_front__f_t3[24]
  PIN g_front_2_u_front__f_t3[25]
    DIRECTION OUTPUT ;
    USE SIGNAL ;
    PORT
      LAYER M4 ;
        RECT  215.808 119.58 216 119.604 ;
    END
  END g_front_2_u_front__f_t3[25]
  PIN g_front_2_u_front__f_t3[26]
    DIRECTION OUTPUT ;
    USE SIGNAL ;
    PORT
      LAYER M4 ;
        RECT  215.808 120.012 216 120.036 ;
    END
  END g_front_2_u_front__f_t3[26]
  PIN g_front_2_u_front__f_t3[27]
    DIRECTION OUTPUT ;
    USE SIGNAL ;
    PORT
      LAYER M4 ;
        RECT  215.808 120.492 216 120.516 ;
    END
  END g_front_2_u_front__f_t3[27]
  PIN g_front_2_u_front__f_t3[28]
    DIRECTION OUTPUT ;
    USE SIGNAL ;
    PORT
      LAYER M4 ;
        RECT  215.808 120.924 216 120.948 ;
    END
  END g_front_2_u_front__f_t3[28]
  PIN g_front_2_u_front__f_t3[29]
    DIRECTION OUTPUT ;
    USE SIGNAL ;
    PORT
      LAYER M4 ;
        RECT  215.808 121.404 216 121.428 ;
    END
  END g_front_2_u_front__f_t3[29]
  PIN g_front_2_u_front__f_t3[2]
    DIRECTION OUTPUT ;
    USE SIGNAL ;
    PORT
      LAYER M4 ;
        RECT  215.808 109.116 216 109.14 ;
    END
  END g_front_2_u_front__f_t3[2]
  PIN g_front_2_u_front__f_t3[30]
    DIRECTION OUTPUT ;
    USE SIGNAL ;
    PORT
      LAYER M4 ;
        RECT  215.808 121.836 216 121.86 ;
    END
  END g_front_2_u_front__f_t3[30]
  PIN g_front_2_u_front__f_t3[31]
    DIRECTION OUTPUT ;
    USE SIGNAL ;
    PORT
      LAYER M4 ;
        RECT  215.808 122.316 216 122.34 ;
    END
  END g_front_2_u_front__f_t3[31]
  PIN g_front_2_u_front__f_t3[32]
    DIRECTION OUTPUT ;
    USE SIGNAL ;
    PORT
      LAYER M4 ;
        RECT  215.808 122.748 216 122.772 ;
    END
  END g_front_2_u_front__f_t3[32]
  PIN g_front_2_u_front__f_t3[33]
    DIRECTION OUTPUT ;
    USE SIGNAL ;
    PORT
      LAYER M4 ;
        RECT  215.808 123.228 216 123.252 ;
    END
  END g_front_2_u_front__f_t3[33]
  PIN g_front_2_u_front__f_t3[34]
    DIRECTION OUTPUT ;
    USE SIGNAL ;
    PORT
      LAYER M4 ;
        RECT  215.808 123.66 216 123.684 ;
    END
  END g_front_2_u_front__f_t3[34]
  PIN g_front_2_u_front__f_t3[35]
    DIRECTION OUTPUT ;
    USE SIGNAL ;
    PORT
      LAYER M4 ;
        RECT  215.808 124.092 216 124.116 ;
    END
  END g_front_2_u_front__f_t3[35]
  PIN g_front_2_u_front__f_t3[36]
    DIRECTION OUTPUT ;
    USE SIGNAL ;
    PORT
      LAYER M4 ;
        RECT  215.808 124.572 216 124.596 ;
    END
  END g_front_2_u_front__f_t3[36]
  PIN g_front_2_u_front__f_t3[37]
    DIRECTION OUTPUT ;
    USE SIGNAL ;
    PORT
      LAYER M4 ;
        RECT  215.808 125.004 216 125.028 ;
    END
  END g_front_2_u_front__f_t3[37]
  PIN g_front_2_u_front__f_t3[38]
    DIRECTION OUTPUT ;
    USE SIGNAL ;
    PORT
      LAYER M4 ;
        RECT  215.808 125.484 216 125.508 ;
    END
  END g_front_2_u_front__f_t3[38]
  PIN g_front_2_u_front__f_t3[39]
    DIRECTION OUTPUT ;
    USE SIGNAL ;
    PORT
      LAYER M4 ;
        RECT  215.808 125.916 216 125.94 ;
    END
  END g_front_2_u_front__f_t3[39]
  PIN g_front_2_u_front__f_t3[3]
    DIRECTION OUTPUT ;
    USE SIGNAL ;
    PORT
      LAYER M4 ;
        RECT  215.808 109.596 216 109.62 ;
    END
  END g_front_2_u_front__f_t3[3]
  PIN g_front_2_u_front__f_t3[40]
    DIRECTION OUTPUT ;
    USE SIGNAL ;
    PORT
      LAYER M4 ;
        RECT  215.808 126.396 216 126.42 ;
    END
  END g_front_2_u_front__f_t3[40]
  PIN g_front_2_u_front__f_t3[41]
    DIRECTION OUTPUT ;
    USE SIGNAL ;
    PORT
      LAYER M4 ;
        RECT  215.808 126.828 216 126.852 ;
    END
  END g_front_2_u_front__f_t3[41]
  PIN g_front_2_u_front__f_t3[42]
    DIRECTION OUTPUT ;
    USE SIGNAL ;
    PORT
      LAYER M4 ;
        RECT  215.808 127.308 216 127.332 ;
    END
  END g_front_2_u_front__f_t3[42]
  PIN g_front_2_u_front__f_t3[43]
    DIRECTION OUTPUT ;
    USE SIGNAL ;
    PORT
      LAYER M4 ;
        RECT  215.808 127.74 216 127.764 ;
    END
  END g_front_2_u_front__f_t3[43]
  PIN g_front_2_u_front__f_t3[44]
    DIRECTION OUTPUT ;
    USE SIGNAL ;
    PORT
      LAYER M4 ;
        RECT  215.808 128.22 216 128.244 ;
    END
  END g_front_2_u_front__f_t3[44]
  PIN g_front_2_u_front__f_t3[45]
    DIRECTION OUTPUT ;
    USE SIGNAL ;
    PORT
      LAYER M4 ;
        RECT  215.808 128.652 216 128.676 ;
    END
  END g_front_2_u_front__f_t3[45]
  PIN g_front_2_u_front__f_t3[46]
    DIRECTION OUTPUT ;
    USE SIGNAL ;
    PORT
      LAYER M4 ;
        RECT  215.808 129.132 216 129.156 ;
    END
  END g_front_2_u_front__f_t3[46]
  PIN g_front_2_u_front__f_t3[47]
    DIRECTION OUTPUT ;
    USE SIGNAL ;
    PORT
      LAYER M4 ;
        RECT  215.808 129.564 216 129.588 ;
    END
  END g_front_2_u_front__f_t3[47]
  PIN g_front_2_u_front__f_t3[48]
    DIRECTION OUTPUT ;
    USE SIGNAL ;
    PORT
      LAYER M4 ;
        RECT  215.808 129.996 216 130.02 ;
    END
  END g_front_2_u_front__f_t3[48]
  PIN g_front_2_u_front__f_t3[49]
    DIRECTION OUTPUT ;
    USE SIGNAL ;
    PORT
      LAYER M4 ;
        RECT  215.808 130.476 216 130.5 ;
    END
  END g_front_2_u_front__f_t3[49]
  PIN g_front_2_u_front__f_t3[4]
    DIRECTION OUTPUT ;
    USE SIGNAL ;
    PORT
      LAYER M4 ;
        RECT  215.808 110.028 216 110.052 ;
    END
  END g_front_2_u_front__f_t3[4]
  PIN g_front_2_u_front__f_t3[50]
    DIRECTION OUTPUT ;
    USE SIGNAL ;
    PORT
      LAYER M4 ;
        RECT  215.808 130.908 216 130.932 ;
    END
  END g_front_2_u_front__f_t3[50]
  PIN g_front_2_u_front__f_t3[51]
    DIRECTION OUTPUT ;
    USE SIGNAL ;
    PORT
      LAYER M4 ;
        RECT  215.808 131.388 216 131.412 ;
    END
  END g_front_2_u_front__f_t3[51]
  PIN g_front_2_u_front__f_t3[52]
    DIRECTION OUTPUT ;
    USE SIGNAL ;
    PORT
      LAYER M4 ;
        RECT  215.808 131.82 216 131.844 ;
    END
  END g_front_2_u_front__f_t3[52]
  PIN g_front_2_u_front__f_t3[53]
    DIRECTION OUTPUT ;
    USE SIGNAL ;
    PORT
      LAYER M4 ;
        RECT  215.808 132.3 216 132.324 ;
    END
  END g_front_2_u_front__f_t3[53]
  PIN g_front_2_u_front__f_t3[54]
    DIRECTION OUTPUT ;
    USE SIGNAL ;
    PORT
      LAYER M4 ;
        RECT  215.808 132.732 216 132.756 ;
    END
  END g_front_2_u_front__f_t3[54]
  PIN g_front_2_u_front__f_t3[55]
    DIRECTION OUTPUT ;
    USE SIGNAL ;
    PORT
      LAYER M4 ;
        RECT  215.808 133.212 216 133.236 ;
    END
  END g_front_2_u_front__f_t3[55]
  PIN g_front_2_u_front__f_t3[56]
    DIRECTION OUTPUT ;
    USE SIGNAL ;
    PORT
      LAYER M4 ;
        RECT  215.808 133.644 216 133.668 ;
    END
  END g_front_2_u_front__f_t3[56]
  PIN g_front_2_u_front__f_t3[57]
    DIRECTION OUTPUT ;
    USE SIGNAL ;
    PORT
      LAYER M4 ;
        RECT  215.808 134.124 216 134.148 ;
    END
  END g_front_2_u_front__f_t3[57]
  PIN g_front_2_u_front__f_t3[58]
    DIRECTION OUTPUT ;
    USE SIGNAL ;
    PORT
      LAYER M4 ;
        RECT  215.808 134.556 216 134.58 ;
    END
  END g_front_2_u_front__f_t3[58]
  PIN g_front_2_u_front__f_t3[59]
    DIRECTION OUTPUT ;
    USE SIGNAL ;
    PORT
      LAYER M4 ;
        RECT  215.808 135.036 216 135.06 ;
    END
  END g_front_2_u_front__f_t3[59]
  PIN g_front_2_u_front__f_t3[5]
    DIRECTION OUTPUT ;
    USE SIGNAL ;
    PORT
      LAYER M4 ;
        RECT  215.808 110.508 216 110.532 ;
    END
  END g_front_2_u_front__f_t3[5]
  PIN g_front_2_u_front__f_t3[60]
    DIRECTION OUTPUT ;
    USE SIGNAL ;
    PORT
      LAYER M4 ;
        RECT  215.808 135.468 216 135.492 ;
    END
  END g_front_2_u_front__f_t3[60]
  PIN g_front_2_u_front__f_t3[61]
    DIRECTION OUTPUT ;
    USE SIGNAL ;
    PORT
      LAYER M4 ;
        RECT  215.808 135.948 216 135.972 ;
    END
  END g_front_2_u_front__f_t3[61]
  PIN g_front_2_u_front__f_t3[62]
    DIRECTION OUTPUT ;
    USE SIGNAL ;
    PORT
      LAYER M4 ;
        RECT  215.808 136.38 216 136.404 ;
    END
  END g_front_2_u_front__f_t3[62]
  PIN g_front_2_u_front__f_t3[63]
    DIRECTION OUTPUT ;
    USE SIGNAL ;
    PORT
      LAYER M4 ;
        RECT  215.808 136.812 216 136.836 ;
    END
  END g_front_2_u_front__f_t3[63]
  PIN g_front_2_u_front__f_t3[64]
    DIRECTION OUTPUT ;
    USE SIGNAL ;
    PORT
      LAYER M4 ;
        RECT  215.808 137.292 216 137.316 ;
    END
  END g_front_2_u_front__f_t3[64]
  PIN g_front_2_u_front__f_t3[65]
    DIRECTION OUTPUT ;
    USE SIGNAL ;
    PORT
      LAYER M4 ;
        RECT  215.808 137.724 216 137.748 ;
    END
  END g_front_2_u_front__f_t3[65]
  PIN g_front_2_u_front__f_t3[66]
    DIRECTION OUTPUT ;
    USE SIGNAL ;
    PORT
      LAYER M4 ;
        RECT  215.808 138.204 216 138.228 ;
    END
  END g_front_2_u_front__f_t3[66]
  PIN g_front_2_u_front__f_t3[67]
    DIRECTION OUTPUT ;
    USE SIGNAL ;
    PORT
      LAYER M4 ;
        RECT  215.808 138.636 216 138.66 ;
    END
  END g_front_2_u_front__f_t3[67]
  PIN g_front_2_u_front__f_t3[68]
    DIRECTION OUTPUT ;
    USE SIGNAL ;
    PORT
      LAYER M4 ;
        RECT  215.808 139.116 216 139.14 ;
    END
  END g_front_2_u_front__f_t3[68]
  PIN g_front_2_u_front__f_t3[69]
    DIRECTION OUTPUT ;
    USE SIGNAL ;
    PORT
      LAYER M4 ;
        RECT  215.808 139.548 216 139.572 ;
    END
  END g_front_2_u_front__f_t3[69]
  PIN g_front_2_u_front__f_t3[6]
    DIRECTION OUTPUT ;
    USE SIGNAL ;
    PORT
      LAYER M4 ;
        RECT  215.808 110.94 216 110.964 ;
    END
  END g_front_2_u_front__f_t3[6]
  PIN g_front_2_u_front__f_t3[70]
    DIRECTION OUTPUT ;
    USE SIGNAL ;
    PORT
      LAYER M4 ;
        RECT  215.808 140.028 216 140.052 ;
    END
  END g_front_2_u_front__f_t3[70]
  PIN g_front_2_u_front__f_t3[71]
    DIRECTION OUTPUT ;
    USE SIGNAL ;
    PORT
      LAYER M4 ;
        RECT  215.808 140.46 216 140.484 ;
    END
  END g_front_2_u_front__f_t3[71]
  PIN g_front_2_u_front__f_t3[72]
    DIRECTION OUTPUT ;
    USE SIGNAL ;
    PORT
      LAYER M4 ;
        RECT  215.808 140.94 216 140.964 ;
    END
  END g_front_2_u_front__f_t3[72]
  PIN g_front_2_u_front__f_t3[73]
    DIRECTION OUTPUT ;
    USE SIGNAL ;
    PORT
      LAYER M4 ;
        RECT  215.808 141.372 216 141.396 ;
    END
  END g_front_2_u_front__f_t3[73]
  PIN g_front_2_u_front__f_t3[74]
    DIRECTION OUTPUT ;
    USE SIGNAL ;
    PORT
      LAYER M4 ;
        RECT  215.808 141.852 216 141.876 ;
    END
  END g_front_2_u_front__f_t3[74]
  PIN g_front_2_u_front__f_t3[75]
    DIRECTION OUTPUT ;
    USE SIGNAL ;
    PORT
      LAYER M4 ;
        RECT  215.808 142.284 216 142.308 ;
    END
  END g_front_2_u_front__f_t3[75]
  PIN g_front_2_u_front__f_t3[76]
    DIRECTION OUTPUT ;
    USE SIGNAL ;
    PORT
      LAYER M4 ;
        RECT  215.808 142.716 216 142.74 ;
    END
  END g_front_2_u_front__f_t3[76]
  PIN g_front_2_u_front__f_t3[77]
    DIRECTION OUTPUT ;
    USE SIGNAL ;
    PORT
      LAYER M4 ;
        RECT  215.808 143.196 216 143.22 ;
    END
  END g_front_2_u_front__f_t3[77]
  PIN g_front_2_u_front__f_t3[78]
    DIRECTION OUTPUT ;
    USE SIGNAL ;
    PORT
      LAYER M4 ;
        RECT  215.808 143.628 216 143.652 ;
    END
  END g_front_2_u_front__f_t3[78]
  PIN g_front_2_u_front__f_t3[79]
    DIRECTION OUTPUT ;
    USE SIGNAL ;
    PORT
      LAYER M4 ;
        RECT  215.808 144.108 216 144.132 ;
    END
  END g_front_2_u_front__f_t3[79]
  PIN g_front_2_u_front__f_t3[7]
    DIRECTION OUTPUT ;
    USE SIGNAL ;
    PORT
      LAYER M4 ;
        RECT  215.808 111.372 216 111.396 ;
    END
  END g_front_2_u_front__f_t3[7]
  PIN g_front_2_u_front__f_t3[80]
    DIRECTION OUTPUT ;
    USE SIGNAL ;
    PORT
      LAYER M4 ;
        RECT  215.808 144.54 216 144.564 ;
    END
  END g_front_2_u_front__f_t3[80]
  PIN g_front_2_u_front__f_t3[81]
    DIRECTION OUTPUT ;
    USE SIGNAL ;
    PORT
      LAYER M4 ;
        RECT  215.808 145.02 216 145.044 ;
    END
  END g_front_2_u_front__f_t3[81]
  PIN g_front_2_u_front__f_t3[82]
    DIRECTION OUTPUT ;
    USE SIGNAL ;
    PORT
      LAYER M4 ;
        RECT  215.808 145.452 216 145.476 ;
    END
  END g_front_2_u_front__f_t3[82]
  PIN g_front_2_u_front__f_t3[83]
    DIRECTION OUTPUT ;
    USE SIGNAL ;
    PORT
      LAYER M4 ;
        RECT  215.808 145.932 216 145.956 ;
    END
  END g_front_2_u_front__f_t3[83]
  PIN g_front_2_u_front__f_t3[84]
    DIRECTION OUTPUT ;
    USE SIGNAL ;
    PORT
      LAYER M4 ;
        RECT  215.808 146.364 216 146.388 ;
    END
  END g_front_2_u_front__f_t3[84]
  PIN g_front_2_u_front__f_t3[85]
    DIRECTION OUTPUT ;
    USE SIGNAL ;
    PORT
      LAYER M4 ;
        RECT  215.808 146.844 216 146.868 ;
    END
  END g_front_2_u_front__f_t3[85]
  PIN g_front_2_u_front__f_t3[86]
    DIRECTION OUTPUT ;
    USE SIGNAL ;
    PORT
      LAYER M4 ;
        RECT  215.808 147.276 216 147.3 ;
    END
  END g_front_2_u_front__f_t3[86]
  PIN g_front_2_u_front__f_t3[87]
    DIRECTION OUTPUT ;
    USE SIGNAL ;
    PORT
      LAYER M4 ;
        RECT  215.808 147.756 216 147.78 ;
    END
  END g_front_2_u_front__f_t3[87]
  PIN g_front_2_u_front__f_t3[88]
    DIRECTION OUTPUT ;
    USE SIGNAL ;
    PORT
      LAYER M4 ;
        RECT  215.808 148.188 216 148.212 ;
    END
  END g_front_2_u_front__f_t3[88]
  PIN g_front_2_u_front__f_t3[89]
    DIRECTION OUTPUT ;
    USE SIGNAL ;
    PORT
      LAYER M4 ;
        RECT  215.808 148.62 216 148.644 ;
    END
  END g_front_2_u_front__f_t3[89]
  PIN g_front_2_u_front__f_t3[8]
    DIRECTION OUTPUT ;
    USE SIGNAL ;
    PORT
      LAYER M4 ;
        RECT  215.808 111.852 216 111.876 ;
    END
  END g_front_2_u_front__f_t3[8]
  PIN g_front_2_u_front__f_t3[90]
    DIRECTION OUTPUT ;
    USE SIGNAL ;
    PORT
      LAYER M4 ;
        RECT  215.808 149.1 216 149.124 ;
    END
  END g_front_2_u_front__f_t3[90]
  PIN g_front_2_u_front__f_t3[91]
    DIRECTION OUTPUT ;
    USE SIGNAL ;
    PORT
      LAYER M4 ;
        RECT  215.808 149.532 216 149.556 ;
    END
  END g_front_2_u_front__f_t3[91]
  PIN g_front_2_u_front__f_t3[92]
    DIRECTION OUTPUT ;
    USE SIGNAL ;
    PORT
      LAYER M4 ;
        RECT  215.808 150.012 216 150.036 ;
    END
  END g_front_2_u_front__f_t3[92]
  PIN g_front_2_u_front__f_t3[93]
    DIRECTION OUTPUT ;
    USE SIGNAL ;
    PORT
      LAYER M4 ;
        RECT  215.808 150.444 216 150.468 ;
    END
  END g_front_2_u_front__f_t3[93]
  PIN g_front_2_u_front__f_t3[94]
    DIRECTION OUTPUT ;
    USE SIGNAL ;
    PORT
      LAYER M4 ;
        RECT  215.808 150.924 216 150.948 ;
    END
  END g_front_2_u_front__f_t3[94]
  PIN g_front_2_u_front__f_t3[95]
    DIRECTION OUTPUT ;
    USE SIGNAL ;
    PORT
      LAYER M4 ;
        RECT  215.808 151.356 216 151.38 ;
    END
  END g_front_2_u_front__f_t3[95]
  PIN g_front_2_u_front__f_t3[96]
    DIRECTION OUTPUT ;
    USE SIGNAL ;
    PORT
      LAYER M4 ;
        RECT  215.808 151.836 216 151.86 ;
    END
  END g_front_2_u_front__f_t3[96]
  PIN g_front_2_u_front__f_t3[97]
    DIRECTION OUTPUT ;
    USE SIGNAL ;
    PORT
      LAYER M4 ;
        RECT  215.808 152.268 216 152.292 ;
    END
  END g_front_2_u_front__f_t3[97]
  PIN g_front_2_u_front__f_t3[98]
    DIRECTION OUTPUT ;
    USE SIGNAL ;
    PORT
      LAYER M4 ;
        RECT  215.808 152.748 216 152.772 ;
    END
  END g_front_2_u_front__f_t3[98]
  PIN g_front_2_u_front__f_t3[99]
    DIRECTION OUTPUT ;
    USE SIGNAL ;
    PORT
      LAYER M4 ;
        RECT  215.808 153.18 216 153.204 ;
    END
  END g_front_2_u_front__f_t3[99]
  PIN g_front_2_u_front__f_t3[9]
    DIRECTION OUTPUT ;
    USE SIGNAL ;
    PORT
      LAYER M4 ;
        RECT  215.808 112.284 216 112.308 ;
    END
  END g_front_2_u_front__f_t3[9]
  PIN g_front_2_u_front__hid[0]
    DIRECTION INPUT ;
    USE SIGNAL ;
    PORT
      LAYER M4 ;
        RECT  0 107.964 0.192 107.988 ;
    END
  END g_front_2_u_front__hid[0]
  PIN g_front_2_u_front__hid[1]
    DIRECTION INPUT ;
    USE SIGNAL ;
    PORT
      LAYER M5 ;
        RECT  107.964 215.808 107.988 216 ;
    END
  END g_front_2_u_front__hid[1]
  PIN g_front_2_u_front__lt_in[0]
    DIRECTION INPUT ;
    USE SIGNAL ;
    PORT
      LAYER M5 ;
        RECT  7.26 0 7.284 0.192 ;
    END
  END g_front_2_u_front__lt_in[0]
  PIN g_front_2_u_front__lt_in[10]
    DIRECTION INPUT ;
    USE SIGNAL ;
    PORT
      LAYER M5 ;
        RECT  9.66 0 9.684 0.192 ;
    END
  END g_front_2_u_front__lt_in[10]
  PIN g_front_2_u_front__lt_in[11]
    DIRECTION INPUT ;
    USE SIGNAL ;
    PORT
      LAYER M5 ;
        RECT  9.9 0 9.924 0.192 ;
    END
  END g_front_2_u_front__lt_in[11]
  PIN g_front_2_u_front__lt_in[1]
    DIRECTION INPUT ;
    USE SIGNAL ;
    PORT
      LAYER M5 ;
        RECT  7.5 0 7.524 0.192 ;
    END
  END g_front_2_u_front__lt_in[1]
  PIN g_front_2_u_front__lt_in[2]
    DIRECTION INPUT ;
    USE SIGNAL ;
    PORT
      LAYER M5 ;
        RECT  7.74 0 7.764 0.192 ;
    END
  END g_front_2_u_front__lt_in[2]
  PIN g_front_2_u_front__lt_in[3]
    DIRECTION INPUT ;
    USE SIGNAL ;
    PORT
      LAYER M5 ;
        RECT  7.98 0 8.004 0.192 ;
    END
  END g_front_2_u_front__lt_in[3]
  PIN g_front_2_u_front__lt_in[4]
    DIRECTION INPUT ;
    USE SIGNAL ;
    PORT
      LAYER M5 ;
        RECT  8.22 0 8.244 0.192 ;
    END
  END g_front_2_u_front__lt_in[4]
  PIN g_front_2_u_front__lt_in[5]
    DIRECTION INPUT ;
    USE SIGNAL ;
    PORT
      LAYER M5 ;
        RECT  8.46 0 8.484 0.192 ;
    END
  END g_front_2_u_front__lt_in[5]
  PIN g_front_2_u_front__lt_in[6]
    DIRECTION INPUT ;
    USE SIGNAL ;
    PORT
      LAYER M5 ;
        RECT  8.7 0 8.724 0.192 ;
    END
  END g_front_2_u_front__lt_in[6]
  PIN g_front_2_u_front__lt_in[7]
    DIRECTION INPUT ;
    USE SIGNAL ;
    PORT
      LAYER M5 ;
        RECT  8.94 0 8.964 0.192 ;
    END
  END g_front_2_u_front__lt_in[7]
  PIN g_front_2_u_front__lt_in[8]
    DIRECTION INPUT ;
    USE SIGNAL ;
    PORT
      LAYER M5 ;
        RECT  9.18 0 9.204 0.192 ;
    END
  END g_front_2_u_front__lt_in[8]
  PIN g_front_2_u_front__lt_in[9]
    DIRECTION INPUT ;
    USE SIGNAL ;
    PORT
      LAYER M5 ;
        RECT  9.42 0 9.444 0.192 ;
    END
  END g_front_2_u_front__lt_in[9]
  PIN g_front_2_u_front__pack_fault[0]
    DIRECTION OUTPUT ;
    USE SIGNAL ;
    PORT
      LAYER M5 ;
        RECT  10.14 0 10.164 0.192 ;
    END
  END g_front_2_u_front__pack_fault[0]
  PIN g_front_2_u_front__q_beat_in[0]
    DIRECTION INPUT ;
    USE SIGNAL ;
    PORT
      LAYER M5 ;
        RECT  10.38 0 10.404 0.192 ;
    END
  END g_front_2_u_front__q_beat_in[0]
  PIN g_front_2_u_front__q_beat_in[1]
    DIRECTION INPUT ;
    USE SIGNAL ;
    PORT
      LAYER M5 ;
        RECT  10.62 0 10.644 0.192 ;
    END
  END g_front_2_u_front__q_beat_in[1]
  PIN g_front_2_u_front__q_beat_in[2]
    DIRECTION INPUT ;
    USE SIGNAL ;
    PORT
      LAYER M5 ;
        RECT  10.86 0 10.884 0.192 ;
    END
  END g_front_2_u_front__q_beat_in[2]
  PIN g_front_2_u_front__q_beat_in[3]
    DIRECTION INPUT ;
    USE SIGNAL ;
    PORT
      LAYER M5 ;
        RECT  11.1 0 11.124 0.192 ;
    END
  END g_front_2_u_front__q_beat_in[3]
  PIN g_front_2_u_front__q_beat_in[4]
    DIRECTION INPUT ;
    USE SIGNAL ;
    PORT
      LAYER M5 ;
        RECT  11.34 0 11.364 0.192 ;
    END
  END g_front_2_u_front__q_beat_in[4]
  PIN g_front_2_u_front__q_beat_in[5]
    DIRECTION INPUT ;
    USE SIGNAL ;
    PORT
      LAYER M5 ;
        RECT  11.58 0 11.604 0.192 ;
    END
  END g_front_2_u_front__q_beat_in[5]
  PIN g_front_2_u_front__q_data_in[0]
    DIRECTION INPUT ;
    USE SIGNAL ;
    PORT
      LAYER M5 ;
        RECT  11.82 0 11.844 0.192 ;
    END
  END g_front_2_u_front__q_data_in[0]
  PIN g_front_2_u_front__q_data_in[100]
    DIRECTION INPUT ;
    USE SIGNAL ;
    PORT
      LAYER M5 ;
        RECT  35.628 0 35.652 0.192 ;
    END
  END g_front_2_u_front__q_data_in[100]
  PIN g_front_2_u_front__q_data_in[101]
    DIRECTION INPUT ;
    USE SIGNAL ;
    PORT
      LAYER M5 ;
        RECT  35.868 0 35.892 0.192 ;
    END
  END g_front_2_u_front__q_data_in[101]
  PIN g_front_2_u_front__q_data_in[102]
    DIRECTION INPUT ;
    USE SIGNAL ;
    PORT
      LAYER M5 ;
        RECT  36.108 0 36.132 0.192 ;
    END
  END g_front_2_u_front__q_data_in[102]
  PIN g_front_2_u_front__q_data_in[103]
    DIRECTION INPUT ;
    USE SIGNAL ;
    PORT
      LAYER M5 ;
        RECT  36.348 0 36.372 0.192 ;
    END
  END g_front_2_u_front__q_data_in[103]
  PIN g_front_2_u_front__q_data_in[104]
    DIRECTION INPUT ;
    USE SIGNAL ;
    PORT
      LAYER M5 ;
        RECT  36.588 0 36.612 0.192 ;
    END
  END g_front_2_u_front__q_data_in[104]
  PIN g_front_2_u_front__q_data_in[105]
    DIRECTION INPUT ;
    USE SIGNAL ;
    PORT
      LAYER M5 ;
        RECT  36.828 0 36.852 0.192 ;
    END
  END g_front_2_u_front__q_data_in[105]
  PIN g_front_2_u_front__q_data_in[106]
    DIRECTION INPUT ;
    USE SIGNAL ;
    PORT
      LAYER M5 ;
        RECT  37.068 0 37.092 0.192 ;
    END
  END g_front_2_u_front__q_data_in[106]
  PIN g_front_2_u_front__q_data_in[107]
    DIRECTION INPUT ;
    USE SIGNAL ;
    PORT
      LAYER M5 ;
        RECT  37.308 0 37.332 0.192 ;
    END
  END g_front_2_u_front__q_data_in[107]
  PIN g_front_2_u_front__q_data_in[108]
    DIRECTION INPUT ;
    USE SIGNAL ;
    PORT
      LAYER M5 ;
        RECT  37.548 0 37.572 0.192 ;
    END
  END g_front_2_u_front__q_data_in[108]
  PIN g_front_2_u_front__q_data_in[109]
    DIRECTION INPUT ;
    USE SIGNAL ;
    PORT
      LAYER M5 ;
        RECT  37.788 0 37.812 0.192 ;
    END
  END g_front_2_u_front__q_data_in[109]
  PIN g_front_2_u_front__q_data_in[10]
    DIRECTION INPUT ;
    USE SIGNAL ;
    PORT
      LAYER M5 ;
        RECT  14.172 0 14.196 0.192 ;
    END
  END g_front_2_u_front__q_data_in[10]
  PIN g_front_2_u_front__q_data_in[110]
    DIRECTION INPUT ;
    USE SIGNAL ;
    PORT
      LAYER M5 ;
        RECT  38.028 0 38.052 0.192 ;
    END
  END g_front_2_u_front__q_data_in[110]
  PIN g_front_2_u_front__q_data_in[111]
    DIRECTION INPUT ;
    USE SIGNAL ;
    PORT
      LAYER M5 ;
        RECT  38.268 0 38.292 0.192 ;
    END
  END g_front_2_u_front__q_data_in[111]
  PIN g_front_2_u_front__q_data_in[112]
    DIRECTION INPUT ;
    USE SIGNAL ;
    PORT
      LAYER M5 ;
        RECT  38.508 0 38.532 0.192 ;
    END
  END g_front_2_u_front__q_data_in[112]
  PIN g_front_2_u_front__q_data_in[113]
    DIRECTION INPUT ;
    USE SIGNAL ;
    PORT
      LAYER M5 ;
        RECT  38.748 0 38.772 0.192 ;
    END
  END g_front_2_u_front__q_data_in[113]
  PIN g_front_2_u_front__q_data_in[114]
    DIRECTION INPUT ;
    USE SIGNAL ;
    PORT
      LAYER M5 ;
        RECT  38.988 0 39.012 0.192 ;
    END
  END g_front_2_u_front__q_data_in[114]
  PIN g_front_2_u_front__q_data_in[115]
    DIRECTION INPUT ;
    USE SIGNAL ;
    PORT
      LAYER M5 ;
        RECT  39.228 0 39.252 0.192 ;
    END
  END g_front_2_u_front__q_data_in[115]
  PIN g_front_2_u_front__q_data_in[116]
    DIRECTION INPUT ;
    USE SIGNAL ;
    PORT
      LAYER M5 ;
        RECT  39.468 0 39.492 0.192 ;
    END
  END g_front_2_u_front__q_data_in[116]
  PIN g_front_2_u_front__q_data_in[117]
    DIRECTION INPUT ;
    USE SIGNAL ;
    PORT
      LAYER M5 ;
        RECT  39.708 0 39.732 0.192 ;
    END
  END g_front_2_u_front__q_data_in[117]
  PIN g_front_2_u_front__q_data_in[118]
    DIRECTION INPUT ;
    USE SIGNAL ;
    PORT
      LAYER M5 ;
        RECT  39.948 0 39.972 0.192 ;
    END
  END g_front_2_u_front__q_data_in[118]
  PIN g_front_2_u_front__q_data_in[119]
    DIRECTION INPUT ;
    USE SIGNAL ;
    PORT
      LAYER M5 ;
        RECT  40.188 0 40.212 0.192 ;
    END
  END g_front_2_u_front__q_data_in[119]
  PIN g_front_2_u_front__q_data_in[11]
    DIRECTION INPUT ;
    USE SIGNAL ;
    PORT
      LAYER M5 ;
        RECT  14.412 0 14.436 0.192 ;
    END
  END g_front_2_u_front__q_data_in[11]
  PIN g_front_2_u_front__q_data_in[120]
    DIRECTION INPUT ;
    USE SIGNAL ;
    PORT
      LAYER M5 ;
        RECT  40.428 0 40.452 0.192 ;
    END
  END g_front_2_u_front__q_data_in[120]
  PIN g_front_2_u_front__q_data_in[121]
    DIRECTION INPUT ;
    USE SIGNAL ;
    PORT
      LAYER M5 ;
        RECT  40.668 0 40.692 0.192 ;
    END
  END g_front_2_u_front__q_data_in[121]
  PIN g_front_2_u_front__q_data_in[122]
    DIRECTION INPUT ;
    USE SIGNAL ;
    PORT
      LAYER M5 ;
        RECT  40.908 0 40.932 0.192 ;
    END
  END g_front_2_u_front__q_data_in[122]
  PIN g_front_2_u_front__q_data_in[123]
    DIRECTION INPUT ;
    USE SIGNAL ;
    PORT
      LAYER M5 ;
        RECT  41.1 0 41.124 0.192 ;
    END
  END g_front_2_u_front__q_data_in[123]
  PIN g_front_2_u_front__q_data_in[124]
    DIRECTION INPUT ;
    USE SIGNAL ;
    PORT
      LAYER M5 ;
        RECT  41.34 0 41.364 0.192 ;
    END
  END g_front_2_u_front__q_data_in[124]
  PIN g_front_2_u_front__q_data_in[125]
    DIRECTION INPUT ;
    USE SIGNAL ;
    PORT
      LAYER M5 ;
        RECT  41.58 0 41.604 0.192 ;
    END
  END g_front_2_u_front__q_data_in[125]
  PIN g_front_2_u_front__q_data_in[126]
    DIRECTION INPUT ;
    USE SIGNAL ;
    PORT
      LAYER M5 ;
        RECT  41.82 0 41.844 0.192 ;
    END
  END g_front_2_u_front__q_data_in[126]
  PIN g_front_2_u_front__q_data_in[127]
    DIRECTION INPUT ;
    USE SIGNAL ;
    PORT
      LAYER M5 ;
        RECT  42.06 0 42.084 0.192 ;
    END
  END g_front_2_u_front__q_data_in[127]
  PIN g_front_2_u_front__q_data_in[128]
    DIRECTION INPUT ;
    USE SIGNAL ;
    PORT
      LAYER M5 ;
        RECT  42.3 0 42.324 0.192 ;
    END
  END g_front_2_u_front__q_data_in[128]
  PIN g_front_2_u_front__q_data_in[129]
    DIRECTION INPUT ;
    USE SIGNAL ;
    PORT
      LAYER M5 ;
        RECT  42.54 0 42.564 0.192 ;
    END
  END g_front_2_u_front__q_data_in[129]
  PIN g_front_2_u_front__q_data_in[12]
    DIRECTION INPUT ;
    USE SIGNAL ;
    PORT
      LAYER M5 ;
        RECT  14.652 0 14.676 0.192 ;
    END
  END g_front_2_u_front__q_data_in[12]
  PIN g_front_2_u_front__q_data_in[130]
    DIRECTION INPUT ;
    USE SIGNAL ;
    PORT
      LAYER M5 ;
        RECT  42.78 0 42.804 0.192 ;
    END
  END g_front_2_u_front__q_data_in[130]
  PIN g_front_2_u_front__q_data_in[131]
    DIRECTION INPUT ;
    USE SIGNAL ;
    PORT
      LAYER M5 ;
        RECT  43.02 0 43.044 0.192 ;
    END
  END g_front_2_u_front__q_data_in[131]
  PIN g_front_2_u_front__q_data_in[132]
    DIRECTION INPUT ;
    USE SIGNAL ;
    PORT
      LAYER M5 ;
        RECT  43.26 0 43.284 0.192 ;
    END
  END g_front_2_u_front__q_data_in[132]
  PIN g_front_2_u_front__q_data_in[133]
    DIRECTION INPUT ;
    USE SIGNAL ;
    PORT
      LAYER M5 ;
        RECT  43.5 0 43.524 0.192 ;
    END
  END g_front_2_u_front__q_data_in[133]
  PIN g_front_2_u_front__q_data_in[134]
    DIRECTION INPUT ;
    USE SIGNAL ;
    PORT
      LAYER M5 ;
        RECT  43.74 0 43.764 0.192 ;
    END
  END g_front_2_u_front__q_data_in[134]
  PIN g_front_2_u_front__q_data_in[135]
    DIRECTION INPUT ;
    USE SIGNAL ;
    PORT
      LAYER M5 ;
        RECT  43.98 0 44.004 0.192 ;
    END
  END g_front_2_u_front__q_data_in[135]
  PIN g_front_2_u_front__q_data_in[136]
    DIRECTION INPUT ;
    USE SIGNAL ;
    PORT
      LAYER M5 ;
        RECT  44.22 0 44.244 0.192 ;
    END
  END g_front_2_u_front__q_data_in[136]
  PIN g_front_2_u_front__q_data_in[137]
    DIRECTION INPUT ;
    USE SIGNAL ;
    PORT
      LAYER M5 ;
        RECT  44.46 0 44.484 0.192 ;
    END
  END g_front_2_u_front__q_data_in[137]
  PIN g_front_2_u_front__q_data_in[138]
    DIRECTION INPUT ;
    USE SIGNAL ;
    PORT
      LAYER M5 ;
        RECT  44.7 0 44.724 0.192 ;
    END
  END g_front_2_u_front__q_data_in[138]
  PIN g_front_2_u_front__q_data_in[139]
    DIRECTION INPUT ;
    USE SIGNAL ;
    PORT
      LAYER M5 ;
        RECT  44.94 0 44.964 0.192 ;
    END
  END g_front_2_u_front__q_data_in[139]
  PIN g_front_2_u_front__q_data_in[13]
    DIRECTION INPUT ;
    USE SIGNAL ;
    PORT
      LAYER M5 ;
        RECT  14.892 0 14.916 0.192 ;
    END
  END g_front_2_u_front__q_data_in[13]
  PIN g_front_2_u_front__q_data_in[140]
    DIRECTION INPUT ;
    USE SIGNAL ;
    PORT
      LAYER M5 ;
        RECT  45.18 0 45.204 0.192 ;
    END
  END g_front_2_u_front__q_data_in[140]
  PIN g_front_2_u_front__q_data_in[141]
    DIRECTION INPUT ;
    USE SIGNAL ;
    PORT
      LAYER M5 ;
        RECT  45.42 0 45.444 0.192 ;
    END
  END g_front_2_u_front__q_data_in[141]
  PIN g_front_2_u_front__q_data_in[142]
    DIRECTION INPUT ;
    USE SIGNAL ;
    PORT
      LAYER M5 ;
        RECT  45.66 0 45.684 0.192 ;
    END
  END g_front_2_u_front__q_data_in[142]
  PIN g_front_2_u_front__q_data_in[143]
    DIRECTION INPUT ;
    USE SIGNAL ;
    PORT
      LAYER M5 ;
        RECT  45.9 0 45.924 0.192 ;
    END
  END g_front_2_u_front__q_data_in[143]
  PIN g_front_2_u_front__q_data_in[144]
    DIRECTION INPUT ;
    USE SIGNAL ;
    PORT
      LAYER M5 ;
        RECT  46.14 0 46.164 0.192 ;
    END
  END g_front_2_u_front__q_data_in[144]
  PIN g_front_2_u_front__q_data_in[145]
    DIRECTION INPUT ;
    USE SIGNAL ;
    PORT
      LAYER M5 ;
        RECT  46.38 0 46.404 0.192 ;
    END
  END g_front_2_u_front__q_data_in[145]
  PIN g_front_2_u_front__q_data_in[146]
    DIRECTION INPUT ;
    USE SIGNAL ;
    PORT
      LAYER M5 ;
        RECT  46.62 0 46.644 0.192 ;
    END
  END g_front_2_u_front__q_data_in[146]
  PIN g_front_2_u_front__q_data_in[147]
    DIRECTION INPUT ;
    USE SIGNAL ;
    PORT
      LAYER M5 ;
        RECT  46.86 0 46.884 0.192 ;
    END
  END g_front_2_u_front__q_data_in[147]
  PIN g_front_2_u_front__q_data_in[148]
    DIRECTION INPUT ;
    USE SIGNAL ;
    PORT
      LAYER M5 ;
        RECT  47.1 0 47.124 0.192 ;
    END
  END g_front_2_u_front__q_data_in[148]
  PIN g_front_2_u_front__q_data_in[149]
    DIRECTION INPUT ;
    USE SIGNAL ;
    PORT
      LAYER M5 ;
        RECT  47.34 0 47.364 0.192 ;
    END
  END g_front_2_u_front__q_data_in[149]
  PIN g_front_2_u_front__q_data_in[14]
    DIRECTION INPUT ;
    USE SIGNAL ;
    PORT
      LAYER M5 ;
        RECT  15.132 0 15.156 0.192 ;
    END
  END g_front_2_u_front__q_data_in[14]
  PIN g_front_2_u_front__q_data_in[150]
    DIRECTION INPUT ;
    USE SIGNAL ;
    PORT
      LAYER M5 ;
        RECT  47.58 0 47.604 0.192 ;
    END
  END g_front_2_u_front__q_data_in[150]
  PIN g_front_2_u_front__q_data_in[151]
    DIRECTION INPUT ;
    USE SIGNAL ;
    PORT
      LAYER M5 ;
        RECT  47.82 0 47.844 0.192 ;
    END
  END g_front_2_u_front__q_data_in[151]
  PIN g_front_2_u_front__q_data_in[152]
    DIRECTION INPUT ;
    USE SIGNAL ;
    PORT
      LAYER M5 ;
        RECT  48.012 0 48.036 0.192 ;
    END
  END g_front_2_u_front__q_data_in[152]
  PIN g_front_2_u_front__q_data_in[153]
    DIRECTION INPUT ;
    USE SIGNAL ;
    PORT
      LAYER M5 ;
        RECT  48.252 0 48.276 0.192 ;
    END
  END g_front_2_u_front__q_data_in[153]
  PIN g_front_2_u_front__q_data_in[154]
    DIRECTION INPUT ;
    USE SIGNAL ;
    PORT
      LAYER M5 ;
        RECT  48.492 0 48.516 0.192 ;
    END
  END g_front_2_u_front__q_data_in[154]
  PIN g_front_2_u_front__q_data_in[155]
    DIRECTION INPUT ;
    USE SIGNAL ;
    PORT
      LAYER M5 ;
        RECT  48.732 0 48.756 0.192 ;
    END
  END g_front_2_u_front__q_data_in[155]
  PIN g_front_2_u_front__q_data_in[156]
    DIRECTION INPUT ;
    USE SIGNAL ;
    PORT
      LAYER M5 ;
        RECT  48.972 0 48.996 0.192 ;
    END
  END g_front_2_u_front__q_data_in[156]
  PIN g_front_2_u_front__q_data_in[157]
    DIRECTION INPUT ;
    USE SIGNAL ;
    PORT
      LAYER M5 ;
        RECT  49.212 0 49.236 0.192 ;
    END
  END g_front_2_u_front__q_data_in[157]
  PIN g_front_2_u_front__q_data_in[158]
    DIRECTION INPUT ;
    USE SIGNAL ;
    PORT
      LAYER M5 ;
        RECT  49.452 0 49.476 0.192 ;
    END
  END g_front_2_u_front__q_data_in[158]
  PIN g_front_2_u_front__q_data_in[159]
    DIRECTION INPUT ;
    USE SIGNAL ;
    PORT
      LAYER M5 ;
        RECT  49.692 0 49.716 0.192 ;
    END
  END g_front_2_u_front__q_data_in[159]
  PIN g_front_2_u_front__q_data_in[15]
    DIRECTION INPUT ;
    USE SIGNAL ;
    PORT
      LAYER M5 ;
        RECT  15.372 0 15.396 0.192 ;
    END
  END g_front_2_u_front__q_data_in[15]
  PIN g_front_2_u_front__q_data_in[160]
    DIRECTION INPUT ;
    USE SIGNAL ;
    PORT
      LAYER M5 ;
        RECT  49.932 0 49.956 0.192 ;
    END
  END g_front_2_u_front__q_data_in[160]
  PIN g_front_2_u_front__q_data_in[161]
    DIRECTION INPUT ;
    USE SIGNAL ;
    PORT
      LAYER M5 ;
        RECT  50.172 0 50.196 0.192 ;
    END
  END g_front_2_u_front__q_data_in[161]
  PIN g_front_2_u_front__q_data_in[162]
    DIRECTION INPUT ;
    USE SIGNAL ;
    PORT
      LAYER M5 ;
        RECT  50.412 0 50.436 0.192 ;
    END
  END g_front_2_u_front__q_data_in[162]
  PIN g_front_2_u_front__q_data_in[163]
    DIRECTION INPUT ;
    USE SIGNAL ;
    PORT
      LAYER M5 ;
        RECT  50.652 0 50.676 0.192 ;
    END
  END g_front_2_u_front__q_data_in[163]
  PIN g_front_2_u_front__q_data_in[164]
    DIRECTION INPUT ;
    USE SIGNAL ;
    PORT
      LAYER M5 ;
        RECT  50.892 0 50.916 0.192 ;
    END
  END g_front_2_u_front__q_data_in[164]
  PIN g_front_2_u_front__q_data_in[165]
    DIRECTION INPUT ;
    USE SIGNAL ;
    PORT
      LAYER M5 ;
        RECT  51.132 0 51.156 0.192 ;
    END
  END g_front_2_u_front__q_data_in[165]
  PIN g_front_2_u_front__q_data_in[166]
    DIRECTION INPUT ;
    USE SIGNAL ;
    PORT
      LAYER M5 ;
        RECT  51.372 0 51.396 0.192 ;
    END
  END g_front_2_u_front__q_data_in[166]
  PIN g_front_2_u_front__q_data_in[167]
    DIRECTION INPUT ;
    USE SIGNAL ;
    PORT
      LAYER M5 ;
        RECT  51.612 0 51.636 0.192 ;
    END
  END g_front_2_u_front__q_data_in[167]
  PIN g_front_2_u_front__q_data_in[168]
    DIRECTION INPUT ;
    USE SIGNAL ;
    PORT
      LAYER M5 ;
        RECT  51.852 0 51.876 0.192 ;
    END
  END g_front_2_u_front__q_data_in[168]
  PIN g_front_2_u_front__q_data_in[169]
    DIRECTION INPUT ;
    USE SIGNAL ;
    PORT
      LAYER M5 ;
        RECT  52.092 0 52.116 0.192 ;
    END
  END g_front_2_u_front__q_data_in[169]
  PIN g_front_2_u_front__q_data_in[16]
    DIRECTION INPUT ;
    USE SIGNAL ;
    PORT
      LAYER M5 ;
        RECT  15.612 0 15.636 0.192 ;
    END
  END g_front_2_u_front__q_data_in[16]
  PIN g_front_2_u_front__q_data_in[170]
    DIRECTION INPUT ;
    USE SIGNAL ;
    PORT
      LAYER M5 ;
        RECT  52.332 0 52.356 0.192 ;
    END
  END g_front_2_u_front__q_data_in[170]
  PIN g_front_2_u_front__q_data_in[171]
    DIRECTION INPUT ;
    USE SIGNAL ;
    PORT
      LAYER M5 ;
        RECT  52.572 0 52.596 0.192 ;
    END
  END g_front_2_u_front__q_data_in[171]
  PIN g_front_2_u_front__q_data_in[172]
    DIRECTION INPUT ;
    USE SIGNAL ;
    PORT
      LAYER M5 ;
        RECT  52.812 0 52.836 0.192 ;
    END
  END g_front_2_u_front__q_data_in[172]
  PIN g_front_2_u_front__q_data_in[173]
    DIRECTION INPUT ;
    USE SIGNAL ;
    PORT
      LAYER M5 ;
        RECT  53.052 0 53.076 0.192 ;
    END
  END g_front_2_u_front__q_data_in[173]
  PIN g_front_2_u_front__q_data_in[174]
    DIRECTION INPUT ;
    USE SIGNAL ;
    PORT
      LAYER M5 ;
        RECT  53.292 0 53.316 0.192 ;
    END
  END g_front_2_u_front__q_data_in[174]
  PIN g_front_2_u_front__q_data_in[175]
    DIRECTION INPUT ;
    USE SIGNAL ;
    PORT
      LAYER M5 ;
        RECT  53.532 0 53.556 0.192 ;
    END
  END g_front_2_u_front__q_data_in[175]
  PIN g_front_2_u_front__q_data_in[176]
    DIRECTION INPUT ;
    USE SIGNAL ;
    PORT
      LAYER M5 ;
        RECT  53.772 0 53.796 0.192 ;
    END
  END g_front_2_u_front__q_data_in[176]
  PIN g_front_2_u_front__q_data_in[177]
    DIRECTION INPUT ;
    USE SIGNAL ;
    PORT
      LAYER M5 ;
        RECT  54.012 0 54.036 0.192 ;
    END
  END g_front_2_u_front__q_data_in[177]
  PIN g_front_2_u_front__q_data_in[178]
    DIRECTION INPUT ;
    USE SIGNAL ;
    PORT
      LAYER M5 ;
        RECT  54.252 0 54.276 0.192 ;
    END
  END g_front_2_u_front__q_data_in[178]
  PIN g_front_2_u_front__q_data_in[179]
    DIRECTION INPUT ;
    USE SIGNAL ;
    PORT
      LAYER M5 ;
        RECT  54.492 0 54.516 0.192 ;
    END
  END g_front_2_u_front__q_data_in[179]
  PIN g_front_2_u_front__q_data_in[17]
    DIRECTION INPUT ;
    USE SIGNAL ;
    PORT
      LAYER M5 ;
        RECT  15.852 0 15.876 0.192 ;
    END
  END g_front_2_u_front__q_data_in[17]
  PIN g_front_2_u_front__q_data_in[180]
    DIRECTION INPUT ;
    USE SIGNAL ;
    PORT
      LAYER M5 ;
        RECT  54.732 0 54.756 0.192 ;
    END
  END g_front_2_u_front__q_data_in[180]
  PIN g_front_2_u_front__q_data_in[181]
    DIRECTION INPUT ;
    USE SIGNAL ;
    PORT
      LAYER M5 ;
        RECT  54.972 0 54.996 0.192 ;
    END
  END g_front_2_u_front__q_data_in[181]
  PIN g_front_2_u_front__q_data_in[182]
    DIRECTION INPUT ;
    USE SIGNAL ;
    PORT
      LAYER M5 ;
        RECT  55.164 0 55.188 0.192 ;
    END
  END g_front_2_u_front__q_data_in[182]
  PIN g_front_2_u_front__q_data_in[183]
    DIRECTION INPUT ;
    USE SIGNAL ;
    PORT
      LAYER M5 ;
        RECT  55.404 0 55.428 0.192 ;
    END
  END g_front_2_u_front__q_data_in[183]
  PIN g_front_2_u_front__q_data_in[184]
    DIRECTION INPUT ;
    USE SIGNAL ;
    PORT
      LAYER M5 ;
        RECT  55.644 0 55.668 0.192 ;
    END
  END g_front_2_u_front__q_data_in[184]
  PIN g_front_2_u_front__q_data_in[185]
    DIRECTION INPUT ;
    USE SIGNAL ;
    PORT
      LAYER M5 ;
        RECT  55.884 0 55.908 0.192 ;
    END
  END g_front_2_u_front__q_data_in[185]
  PIN g_front_2_u_front__q_data_in[186]
    DIRECTION INPUT ;
    USE SIGNAL ;
    PORT
      LAYER M5 ;
        RECT  56.124 0 56.148 0.192 ;
    END
  END g_front_2_u_front__q_data_in[186]
  PIN g_front_2_u_front__q_data_in[187]
    DIRECTION INPUT ;
    USE SIGNAL ;
    PORT
      LAYER M5 ;
        RECT  56.364 0 56.388 0.192 ;
    END
  END g_front_2_u_front__q_data_in[187]
  PIN g_front_2_u_front__q_data_in[188]
    DIRECTION INPUT ;
    USE SIGNAL ;
    PORT
      LAYER M5 ;
        RECT  56.604 0 56.628 0.192 ;
    END
  END g_front_2_u_front__q_data_in[188]
  PIN g_front_2_u_front__q_data_in[189]
    DIRECTION INPUT ;
    USE SIGNAL ;
    PORT
      LAYER M5 ;
        RECT  56.844 0 56.868 0.192 ;
    END
  END g_front_2_u_front__q_data_in[189]
  PIN g_front_2_u_front__q_data_in[18]
    DIRECTION INPUT ;
    USE SIGNAL ;
    PORT
      LAYER M5 ;
        RECT  16.092 0 16.116 0.192 ;
    END
  END g_front_2_u_front__q_data_in[18]
  PIN g_front_2_u_front__q_data_in[190]
    DIRECTION INPUT ;
    USE SIGNAL ;
    PORT
      LAYER M5 ;
        RECT  57.084 0 57.108 0.192 ;
    END
  END g_front_2_u_front__q_data_in[190]
  PIN g_front_2_u_front__q_data_in[191]
    DIRECTION INPUT ;
    USE SIGNAL ;
    PORT
      LAYER M5 ;
        RECT  57.324 0 57.348 0.192 ;
    END
  END g_front_2_u_front__q_data_in[191]
  PIN g_front_2_u_front__q_data_in[192]
    DIRECTION INPUT ;
    USE SIGNAL ;
    PORT
      LAYER M5 ;
        RECT  57.564 0 57.588 0.192 ;
    END
  END g_front_2_u_front__q_data_in[192]
  PIN g_front_2_u_front__q_data_in[193]
    DIRECTION INPUT ;
    USE SIGNAL ;
    PORT
      LAYER M5 ;
        RECT  57.804 0 57.828 0.192 ;
    END
  END g_front_2_u_front__q_data_in[193]
  PIN g_front_2_u_front__q_data_in[194]
    DIRECTION INPUT ;
    USE SIGNAL ;
    PORT
      LAYER M5 ;
        RECT  58.044 0 58.068 0.192 ;
    END
  END g_front_2_u_front__q_data_in[194]
  PIN g_front_2_u_front__q_data_in[195]
    DIRECTION INPUT ;
    USE SIGNAL ;
    PORT
      LAYER M5 ;
        RECT  58.284 0 58.308 0.192 ;
    END
  END g_front_2_u_front__q_data_in[195]
  PIN g_front_2_u_front__q_data_in[196]
    DIRECTION INPUT ;
    USE SIGNAL ;
    PORT
      LAYER M5 ;
        RECT  58.524 0 58.548 0.192 ;
    END
  END g_front_2_u_front__q_data_in[196]
  PIN g_front_2_u_front__q_data_in[197]
    DIRECTION INPUT ;
    USE SIGNAL ;
    PORT
      LAYER M5 ;
        RECT  58.764 0 58.788 0.192 ;
    END
  END g_front_2_u_front__q_data_in[197]
  PIN g_front_2_u_front__q_data_in[198]
    DIRECTION INPUT ;
    USE SIGNAL ;
    PORT
      LAYER M5 ;
        RECT  59.004 0 59.028 0.192 ;
    END
  END g_front_2_u_front__q_data_in[198]
  PIN g_front_2_u_front__q_data_in[199]
    DIRECTION INPUT ;
    USE SIGNAL ;
    PORT
      LAYER M5 ;
        RECT  59.244 0 59.268 0.192 ;
    END
  END g_front_2_u_front__q_data_in[199]
  PIN g_front_2_u_front__q_data_in[19]
    DIRECTION INPUT ;
    USE SIGNAL ;
    PORT
      LAYER M5 ;
        RECT  16.332 0 16.356 0.192 ;
    END
  END g_front_2_u_front__q_data_in[19]
  PIN g_front_2_u_front__q_data_in[1]
    DIRECTION INPUT ;
    USE SIGNAL ;
    PORT
      LAYER M5 ;
        RECT  12.06 0 12.084 0.192 ;
    END
  END g_front_2_u_front__q_data_in[1]
  PIN g_front_2_u_front__q_data_in[200]
    DIRECTION INPUT ;
    USE SIGNAL ;
    PORT
      LAYER M5 ;
        RECT  59.484 0 59.508 0.192 ;
    END
  END g_front_2_u_front__q_data_in[200]
  PIN g_front_2_u_front__q_data_in[201]
    DIRECTION INPUT ;
    USE SIGNAL ;
    PORT
      LAYER M5 ;
        RECT  59.724 0 59.748 0.192 ;
    END
  END g_front_2_u_front__q_data_in[201]
  PIN g_front_2_u_front__q_data_in[202]
    DIRECTION INPUT ;
    USE SIGNAL ;
    PORT
      LAYER M5 ;
        RECT  59.964 0 59.988 0.192 ;
    END
  END g_front_2_u_front__q_data_in[202]
  PIN g_front_2_u_front__q_data_in[203]
    DIRECTION INPUT ;
    USE SIGNAL ;
    PORT
      LAYER M5 ;
        RECT  60.204 0 60.228 0.192 ;
    END
  END g_front_2_u_front__q_data_in[203]
  PIN g_front_2_u_front__q_data_in[204]
    DIRECTION INPUT ;
    USE SIGNAL ;
    PORT
      LAYER M5 ;
        RECT  60.444 0 60.468 0.192 ;
    END
  END g_front_2_u_front__q_data_in[204]
  PIN g_front_2_u_front__q_data_in[205]
    DIRECTION INPUT ;
    USE SIGNAL ;
    PORT
      LAYER M5 ;
        RECT  60.684 0 60.708 0.192 ;
    END
  END g_front_2_u_front__q_data_in[205]
  PIN g_front_2_u_front__q_data_in[206]
    DIRECTION INPUT ;
    USE SIGNAL ;
    PORT
      LAYER M5 ;
        RECT  60.924 0 60.948 0.192 ;
    END
  END g_front_2_u_front__q_data_in[206]
  PIN g_front_2_u_front__q_data_in[207]
    DIRECTION INPUT ;
    USE SIGNAL ;
    PORT
      LAYER M5 ;
        RECT  61.164 0 61.188 0.192 ;
    END
  END g_front_2_u_front__q_data_in[207]
  PIN g_front_2_u_front__q_data_in[208]
    DIRECTION INPUT ;
    USE SIGNAL ;
    PORT
      LAYER M5 ;
        RECT  61.404 0 61.428 0.192 ;
    END
  END g_front_2_u_front__q_data_in[208]
  PIN g_front_2_u_front__q_data_in[209]
    DIRECTION INPUT ;
    USE SIGNAL ;
    PORT
      LAYER M5 ;
        RECT  61.644 0 61.668 0.192 ;
    END
  END g_front_2_u_front__q_data_in[209]
  PIN g_front_2_u_front__q_data_in[20]
    DIRECTION INPUT ;
    USE SIGNAL ;
    PORT
      LAYER M5 ;
        RECT  16.572 0 16.596 0.192 ;
    END
  END g_front_2_u_front__q_data_in[20]
  PIN g_front_2_u_front__q_data_in[210]
    DIRECTION INPUT ;
    USE SIGNAL ;
    PORT
      LAYER M5 ;
        RECT  61.884 0 61.908 0.192 ;
    END
  END g_front_2_u_front__q_data_in[210]
  PIN g_front_2_u_front__q_data_in[211]
    DIRECTION INPUT ;
    USE SIGNAL ;
    PORT
      LAYER M5 ;
        RECT  62.124 0 62.148 0.192 ;
    END
  END g_front_2_u_front__q_data_in[211]
  PIN g_front_2_u_front__q_data_in[212]
    DIRECTION INPUT ;
    USE SIGNAL ;
    PORT
      LAYER M5 ;
        RECT  62.316 0 62.34 0.192 ;
    END
  END g_front_2_u_front__q_data_in[212]
  PIN g_front_2_u_front__q_data_in[213]
    DIRECTION INPUT ;
    USE SIGNAL ;
    PORT
      LAYER M5 ;
        RECT  62.556 0 62.58 0.192 ;
    END
  END g_front_2_u_front__q_data_in[213]
  PIN g_front_2_u_front__q_data_in[214]
    DIRECTION INPUT ;
    USE SIGNAL ;
    PORT
      LAYER M5 ;
        RECT  62.796 0 62.82 0.192 ;
    END
  END g_front_2_u_front__q_data_in[214]
  PIN g_front_2_u_front__q_data_in[215]
    DIRECTION INPUT ;
    USE SIGNAL ;
    PORT
      LAYER M5 ;
        RECT  63.036 0 63.06 0.192 ;
    END
  END g_front_2_u_front__q_data_in[215]
  PIN g_front_2_u_front__q_data_in[216]
    DIRECTION INPUT ;
    USE SIGNAL ;
    PORT
      LAYER M5 ;
        RECT  63.276 0 63.3 0.192 ;
    END
  END g_front_2_u_front__q_data_in[216]
  PIN g_front_2_u_front__q_data_in[217]
    DIRECTION INPUT ;
    USE SIGNAL ;
    PORT
      LAYER M5 ;
        RECT  63.516 0 63.54 0.192 ;
    END
  END g_front_2_u_front__q_data_in[217]
  PIN g_front_2_u_front__q_data_in[218]
    DIRECTION INPUT ;
    USE SIGNAL ;
    PORT
      LAYER M5 ;
        RECT  63.756 0 63.78 0.192 ;
    END
  END g_front_2_u_front__q_data_in[218]
  PIN g_front_2_u_front__q_data_in[219]
    DIRECTION INPUT ;
    USE SIGNAL ;
    PORT
      LAYER M5 ;
        RECT  63.996 0 64.02 0.192 ;
    END
  END g_front_2_u_front__q_data_in[219]
  PIN g_front_2_u_front__q_data_in[21]
    DIRECTION INPUT ;
    USE SIGNAL ;
    PORT
      LAYER M5 ;
        RECT  16.812 0 16.836 0.192 ;
    END
  END g_front_2_u_front__q_data_in[21]
  PIN g_front_2_u_front__q_data_in[220]
    DIRECTION INPUT ;
    USE SIGNAL ;
    PORT
      LAYER M5 ;
        RECT  64.236 0 64.26 0.192 ;
    END
  END g_front_2_u_front__q_data_in[220]
  PIN g_front_2_u_front__q_data_in[221]
    DIRECTION INPUT ;
    USE SIGNAL ;
    PORT
      LAYER M5 ;
        RECT  64.476 0 64.5 0.192 ;
    END
  END g_front_2_u_front__q_data_in[221]
  PIN g_front_2_u_front__q_data_in[222]
    DIRECTION INPUT ;
    USE SIGNAL ;
    PORT
      LAYER M5 ;
        RECT  64.716 0 64.74 0.192 ;
    END
  END g_front_2_u_front__q_data_in[222]
  PIN g_front_2_u_front__q_data_in[223]
    DIRECTION INPUT ;
    USE SIGNAL ;
    PORT
      LAYER M5 ;
        RECT  64.956 0 64.98 0.192 ;
    END
  END g_front_2_u_front__q_data_in[223]
  PIN g_front_2_u_front__q_data_in[224]
    DIRECTION INPUT ;
    USE SIGNAL ;
    PORT
      LAYER M5 ;
        RECT  65.196 0 65.22 0.192 ;
    END
  END g_front_2_u_front__q_data_in[224]
  PIN g_front_2_u_front__q_data_in[225]
    DIRECTION INPUT ;
    USE SIGNAL ;
    PORT
      LAYER M5 ;
        RECT  65.436 0 65.46 0.192 ;
    END
  END g_front_2_u_front__q_data_in[225]
  PIN g_front_2_u_front__q_data_in[226]
    DIRECTION INPUT ;
    USE SIGNAL ;
    PORT
      LAYER M5 ;
        RECT  65.676 0 65.7 0.192 ;
    END
  END g_front_2_u_front__q_data_in[226]
  PIN g_front_2_u_front__q_data_in[227]
    DIRECTION INPUT ;
    USE SIGNAL ;
    PORT
      LAYER M5 ;
        RECT  65.916 0 65.94 0.192 ;
    END
  END g_front_2_u_front__q_data_in[227]
  PIN g_front_2_u_front__q_data_in[228]
    DIRECTION INPUT ;
    USE SIGNAL ;
    PORT
      LAYER M5 ;
        RECT  66.156 0 66.18 0.192 ;
    END
  END g_front_2_u_front__q_data_in[228]
  PIN g_front_2_u_front__q_data_in[229]
    DIRECTION INPUT ;
    USE SIGNAL ;
    PORT
      LAYER M5 ;
        RECT  66.396 0 66.42 0.192 ;
    END
  END g_front_2_u_front__q_data_in[229]
  PIN g_front_2_u_front__q_data_in[22]
    DIRECTION INPUT ;
    USE SIGNAL ;
    PORT
      LAYER M5 ;
        RECT  17.052 0 17.076 0.192 ;
    END
  END g_front_2_u_front__q_data_in[22]
  PIN g_front_2_u_front__q_data_in[230]
    DIRECTION INPUT ;
    USE SIGNAL ;
    PORT
      LAYER M5 ;
        RECT  66.636 0 66.66 0.192 ;
    END
  END g_front_2_u_front__q_data_in[230]
  PIN g_front_2_u_front__q_data_in[231]
    DIRECTION INPUT ;
    USE SIGNAL ;
    PORT
      LAYER M5 ;
        RECT  66.876 0 66.9 0.192 ;
    END
  END g_front_2_u_front__q_data_in[231]
  PIN g_front_2_u_front__q_data_in[232]
    DIRECTION INPUT ;
    USE SIGNAL ;
    PORT
      LAYER M5 ;
        RECT  67.116 0 67.14 0.192 ;
    END
  END g_front_2_u_front__q_data_in[232]
  PIN g_front_2_u_front__q_data_in[233]
    DIRECTION INPUT ;
    USE SIGNAL ;
    PORT
      LAYER M5 ;
        RECT  67.356 0 67.38 0.192 ;
    END
  END g_front_2_u_front__q_data_in[233]
  PIN g_front_2_u_front__q_data_in[234]
    DIRECTION INPUT ;
    USE SIGNAL ;
    PORT
      LAYER M5 ;
        RECT  67.596 0 67.62 0.192 ;
    END
  END g_front_2_u_front__q_data_in[234]
  PIN g_front_2_u_front__q_data_in[235]
    DIRECTION INPUT ;
    USE SIGNAL ;
    PORT
      LAYER M5 ;
        RECT  67.836 0 67.86 0.192 ;
    END
  END g_front_2_u_front__q_data_in[235]
  PIN g_front_2_u_front__q_data_in[236]
    DIRECTION INPUT ;
    USE SIGNAL ;
    PORT
      LAYER M5 ;
        RECT  68.076 0 68.1 0.192 ;
    END
  END g_front_2_u_front__q_data_in[236]
  PIN g_front_2_u_front__q_data_in[237]
    DIRECTION INPUT ;
    USE SIGNAL ;
    PORT
      LAYER M5 ;
        RECT  68.316 0 68.34 0.192 ;
    END
  END g_front_2_u_front__q_data_in[237]
  PIN g_front_2_u_front__q_data_in[238]
    DIRECTION INPUT ;
    USE SIGNAL ;
    PORT
      LAYER M5 ;
        RECT  68.556 0 68.58 0.192 ;
    END
  END g_front_2_u_front__q_data_in[238]
  PIN g_front_2_u_front__q_data_in[239]
    DIRECTION INPUT ;
    USE SIGNAL ;
    PORT
      LAYER M5 ;
        RECT  68.796 0 68.82 0.192 ;
    END
  END g_front_2_u_front__q_data_in[239]
  PIN g_front_2_u_front__q_data_in[23]
    DIRECTION INPUT ;
    USE SIGNAL ;
    PORT
      LAYER M5 ;
        RECT  17.292 0 17.316 0.192 ;
    END
  END g_front_2_u_front__q_data_in[23]
  PIN g_front_2_u_front__q_data_in[240]
    DIRECTION INPUT ;
    USE SIGNAL ;
    PORT
      LAYER M5 ;
        RECT  69.036 0 69.06 0.192 ;
    END
  END g_front_2_u_front__q_data_in[240]
  PIN g_front_2_u_front__q_data_in[241]
    DIRECTION INPUT ;
    USE SIGNAL ;
    PORT
      LAYER M5 ;
        RECT  69.228 0 69.252 0.192 ;
    END
  END g_front_2_u_front__q_data_in[241]
  PIN g_front_2_u_front__q_data_in[242]
    DIRECTION INPUT ;
    USE SIGNAL ;
    PORT
      LAYER M5 ;
        RECT  69.468 0 69.492 0.192 ;
    END
  END g_front_2_u_front__q_data_in[242]
  PIN g_front_2_u_front__q_data_in[243]
    DIRECTION INPUT ;
    USE SIGNAL ;
    PORT
      LAYER M5 ;
        RECT  69.708 0 69.732 0.192 ;
    END
  END g_front_2_u_front__q_data_in[243]
  PIN g_front_2_u_front__q_data_in[244]
    DIRECTION INPUT ;
    USE SIGNAL ;
    PORT
      LAYER M5 ;
        RECT  69.948 0 69.972 0.192 ;
    END
  END g_front_2_u_front__q_data_in[244]
  PIN g_front_2_u_front__q_data_in[245]
    DIRECTION INPUT ;
    USE SIGNAL ;
    PORT
      LAYER M5 ;
        RECT  70.188 0 70.212 0.192 ;
    END
  END g_front_2_u_front__q_data_in[245]
  PIN g_front_2_u_front__q_data_in[246]
    DIRECTION INPUT ;
    USE SIGNAL ;
    PORT
      LAYER M5 ;
        RECT  70.428 0 70.452 0.192 ;
    END
  END g_front_2_u_front__q_data_in[246]
  PIN g_front_2_u_front__q_data_in[247]
    DIRECTION INPUT ;
    USE SIGNAL ;
    PORT
      LAYER M5 ;
        RECT  70.668 0 70.692 0.192 ;
    END
  END g_front_2_u_front__q_data_in[247]
  PIN g_front_2_u_front__q_data_in[248]
    DIRECTION INPUT ;
    USE SIGNAL ;
    PORT
      LAYER M5 ;
        RECT  70.908 0 70.932 0.192 ;
    END
  END g_front_2_u_front__q_data_in[248]
  PIN g_front_2_u_front__q_data_in[249]
    DIRECTION INPUT ;
    USE SIGNAL ;
    PORT
      LAYER M5 ;
        RECT  71.148 0 71.172 0.192 ;
    END
  END g_front_2_u_front__q_data_in[249]
  PIN g_front_2_u_front__q_data_in[24]
    DIRECTION INPUT ;
    USE SIGNAL ;
    PORT
      LAYER M5 ;
        RECT  17.532 0 17.556 0.192 ;
    END
  END g_front_2_u_front__q_data_in[24]
  PIN g_front_2_u_front__q_data_in[250]
    DIRECTION INPUT ;
    USE SIGNAL ;
    PORT
      LAYER M5 ;
        RECT  71.388 0 71.412 0.192 ;
    END
  END g_front_2_u_front__q_data_in[250]
  PIN g_front_2_u_front__q_data_in[251]
    DIRECTION INPUT ;
    USE SIGNAL ;
    PORT
      LAYER M5 ;
        RECT  71.628 0 71.652 0.192 ;
    END
  END g_front_2_u_front__q_data_in[251]
  PIN g_front_2_u_front__q_data_in[252]
    DIRECTION INPUT ;
    USE SIGNAL ;
    PORT
      LAYER M5 ;
        RECT  71.868 0 71.892 0.192 ;
    END
  END g_front_2_u_front__q_data_in[252]
  PIN g_front_2_u_front__q_data_in[253]
    DIRECTION INPUT ;
    USE SIGNAL ;
    PORT
      LAYER M5 ;
        RECT  72.108 0 72.132 0.192 ;
    END
  END g_front_2_u_front__q_data_in[253]
  PIN g_front_2_u_front__q_data_in[254]
    DIRECTION INPUT ;
    USE SIGNAL ;
    PORT
      LAYER M5 ;
        RECT  72.348 0 72.372 0.192 ;
    END
  END g_front_2_u_front__q_data_in[254]
  PIN g_front_2_u_front__q_data_in[255]
    DIRECTION INPUT ;
    USE SIGNAL ;
    PORT
      LAYER M5 ;
        RECT  72.588 0 72.612 0.192 ;
    END
  END g_front_2_u_front__q_data_in[255]
  PIN g_front_2_u_front__q_data_in[256]
    DIRECTION INPUT ;
    USE SIGNAL ;
    PORT
      LAYER M5 ;
        RECT  72.828 0 72.852 0.192 ;
    END
  END g_front_2_u_front__q_data_in[256]
  PIN g_front_2_u_front__q_data_in[257]
    DIRECTION INPUT ;
    USE SIGNAL ;
    PORT
      LAYER M5 ;
        RECT  73.068 0 73.092 0.192 ;
    END
  END g_front_2_u_front__q_data_in[257]
  PIN g_front_2_u_front__q_data_in[258]
    DIRECTION INPUT ;
    USE SIGNAL ;
    PORT
      LAYER M5 ;
        RECT  73.308 0 73.332 0.192 ;
    END
  END g_front_2_u_front__q_data_in[258]
  PIN g_front_2_u_front__q_data_in[259]
    DIRECTION INPUT ;
    USE SIGNAL ;
    PORT
      LAYER M5 ;
        RECT  73.548 0 73.572 0.192 ;
    END
  END g_front_2_u_front__q_data_in[259]
  PIN g_front_2_u_front__q_data_in[25]
    DIRECTION INPUT ;
    USE SIGNAL ;
    PORT
      LAYER M5 ;
        RECT  17.772 0 17.796 0.192 ;
    END
  END g_front_2_u_front__q_data_in[25]
  PIN g_front_2_u_front__q_data_in[260]
    DIRECTION INPUT ;
    USE SIGNAL ;
    PORT
      LAYER M5 ;
        RECT  73.788 0 73.812 0.192 ;
    END
  END g_front_2_u_front__q_data_in[260]
  PIN g_front_2_u_front__q_data_in[261]
    DIRECTION INPUT ;
    USE SIGNAL ;
    PORT
      LAYER M5 ;
        RECT  74.028 0 74.052 0.192 ;
    END
  END g_front_2_u_front__q_data_in[261]
  PIN g_front_2_u_front__q_data_in[262]
    DIRECTION INPUT ;
    USE SIGNAL ;
    PORT
      LAYER M5 ;
        RECT  74.268 0 74.292 0.192 ;
    END
  END g_front_2_u_front__q_data_in[262]
  PIN g_front_2_u_front__q_data_in[263]
    DIRECTION INPUT ;
    USE SIGNAL ;
    PORT
      LAYER M5 ;
        RECT  74.508 0 74.532 0.192 ;
    END
  END g_front_2_u_front__q_data_in[263]
  PIN g_front_2_u_front__q_data_in[264]
    DIRECTION INPUT ;
    USE SIGNAL ;
    PORT
      LAYER M5 ;
        RECT  74.748 0 74.772 0.192 ;
    END
  END g_front_2_u_front__q_data_in[264]
  PIN g_front_2_u_front__q_data_in[265]
    DIRECTION INPUT ;
    USE SIGNAL ;
    PORT
      LAYER M5 ;
        RECT  74.988 0 75.012 0.192 ;
    END
  END g_front_2_u_front__q_data_in[265]
  PIN g_front_2_u_front__q_data_in[266]
    DIRECTION INPUT ;
    USE SIGNAL ;
    PORT
      LAYER M5 ;
        RECT  75.228 0 75.252 0.192 ;
    END
  END g_front_2_u_front__q_data_in[266]
  PIN g_front_2_u_front__q_data_in[267]
    DIRECTION INPUT ;
    USE SIGNAL ;
    PORT
      LAYER M5 ;
        RECT  75.468 0 75.492 0.192 ;
    END
  END g_front_2_u_front__q_data_in[267]
  PIN g_front_2_u_front__q_data_in[268]
    DIRECTION INPUT ;
    USE SIGNAL ;
    PORT
      LAYER M5 ;
        RECT  75.708 0 75.732 0.192 ;
    END
  END g_front_2_u_front__q_data_in[268]
  PIN g_front_2_u_front__q_data_in[269]
    DIRECTION INPUT ;
    USE SIGNAL ;
    PORT
      LAYER M5 ;
        RECT  75.948 0 75.972 0.192 ;
    END
  END g_front_2_u_front__q_data_in[269]
  PIN g_front_2_u_front__q_data_in[26]
    DIRECTION INPUT ;
    USE SIGNAL ;
    PORT
      LAYER M5 ;
        RECT  18.012 0 18.036 0.192 ;
    END
  END g_front_2_u_front__q_data_in[26]
  PIN g_front_2_u_front__q_data_in[270]
    DIRECTION INPUT ;
    USE SIGNAL ;
    PORT
      LAYER M5 ;
        RECT  76.188 0 76.212 0.192 ;
    END
  END g_front_2_u_front__q_data_in[270]
  PIN g_front_2_u_front__q_data_in[271]
    DIRECTION INPUT ;
    USE SIGNAL ;
    PORT
      LAYER M5 ;
        RECT  76.38 0 76.404 0.192 ;
    END
  END g_front_2_u_front__q_data_in[271]
  PIN g_front_2_u_front__q_data_in[272]
    DIRECTION INPUT ;
    USE SIGNAL ;
    PORT
      LAYER M5 ;
        RECT  76.62 0 76.644 0.192 ;
    END
  END g_front_2_u_front__q_data_in[272]
  PIN g_front_2_u_front__q_data_in[273]
    DIRECTION INPUT ;
    USE SIGNAL ;
    PORT
      LAYER M5 ;
        RECT  76.86 0 76.884 0.192 ;
    END
  END g_front_2_u_front__q_data_in[273]
  PIN g_front_2_u_front__q_data_in[274]
    DIRECTION INPUT ;
    USE SIGNAL ;
    PORT
      LAYER M5 ;
        RECT  77.1 0 77.124 0.192 ;
    END
  END g_front_2_u_front__q_data_in[274]
  PIN g_front_2_u_front__q_data_in[275]
    DIRECTION INPUT ;
    USE SIGNAL ;
    PORT
      LAYER M5 ;
        RECT  77.34 0 77.364 0.192 ;
    END
  END g_front_2_u_front__q_data_in[275]
  PIN g_front_2_u_front__q_data_in[276]
    DIRECTION INPUT ;
    USE SIGNAL ;
    PORT
      LAYER M5 ;
        RECT  77.58 0 77.604 0.192 ;
    END
  END g_front_2_u_front__q_data_in[276]
  PIN g_front_2_u_front__q_data_in[277]
    DIRECTION INPUT ;
    USE SIGNAL ;
    PORT
      LAYER M5 ;
        RECT  77.82 0 77.844 0.192 ;
    END
  END g_front_2_u_front__q_data_in[277]
  PIN g_front_2_u_front__q_data_in[278]
    DIRECTION INPUT ;
    USE SIGNAL ;
    PORT
      LAYER M5 ;
        RECT  78.06 0 78.084 0.192 ;
    END
  END g_front_2_u_front__q_data_in[278]
  PIN g_front_2_u_front__q_data_in[279]
    DIRECTION INPUT ;
    USE SIGNAL ;
    PORT
      LAYER M5 ;
        RECT  78.3 0 78.324 0.192 ;
    END
  END g_front_2_u_front__q_data_in[279]
  PIN g_front_2_u_front__q_data_in[27]
    DIRECTION INPUT ;
    USE SIGNAL ;
    PORT
      LAYER M5 ;
        RECT  18.252 0 18.276 0.192 ;
    END
  END g_front_2_u_front__q_data_in[27]
  PIN g_front_2_u_front__q_data_in[280]
    DIRECTION INPUT ;
    USE SIGNAL ;
    PORT
      LAYER M5 ;
        RECT  78.54 0 78.564 0.192 ;
    END
  END g_front_2_u_front__q_data_in[280]
  PIN g_front_2_u_front__q_data_in[281]
    DIRECTION INPUT ;
    USE SIGNAL ;
    PORT
      LAYER M5 ;
        RECT  78.78 0 78.804 0.192 ;
    END
  END g_front_2_u_front__q_data_in[281]
  PIN g_front_2_u_front__q_data_in[282]
    DIRECTION INPUT ;
    USE SIGNAL ;
    PORT
      LAYER M5 ;
        RECT  79.02 0 79.044 0.192 ;
    END
  END g_front_2_u_front__q_data_in[282]
  PIN g_front_2_u_front__q_data_in[283]
    DIRECTION INPUT ;
    USE SIGNAL ;
    PORT
      LAYER M5 ;
        RECT  79.26 0 79.284 0.192 ;
    END
  END g_front_2_u_front__q_data_in[283]
  PIN g_front_2_u_front__q_data_in[284]
    DIRECTION INPUT ;
    USE SIGNAL ;
    PORT
      LAYER M5 ;
        RECT  79.5 0 79.524 0.192 ;
    END
  END g_front_2_u_front__q_data_in[284]
  PIN g_front_2_u_front__q_data_in[285]
    DIRECTION INPUT ;
    USE SIGNAL ;
    PORT
      LAYER M5 ;
        RECT  79.74 0 79.764 0.192 ;
    END
  END g_front_2_u_front__q_data_in[285]
  PIN g_front_2_u_front__q_data_in[286]
    DIRECTION INPUT ;
    USE SIGNAL ;
    PORT
      LAYER M5 ;
        RECT  79.98 0 80.004 0.192 ;
    END
  END g_front_2_u_front__q_data_in[286]
  PIN g_front_2_u_front__q_data_in[287]
    DIRECTION INPUT ;
    USE SIGNAL ;
    PORT
      LAYER M5 ;
        RECT  80.22 0 80.244 0.192 ;
    END
  END g_front_2_u_front__q_data_in[287]
  PIN g_front_2_u_front__q_data_in[288]
    DIRECTION INPUT ;
    USE SIGNAL ;
    PORT
      LAYER M5 ;
        RECT  80.46 0 80.484 0.192 ;
    END
  END g_front_2_u_front__q_data_in[288]
  PIN g_front_2_u_front__q_data_in[289]
    DIRECTION INPUT ;
    USE SIGNAL ;
    PORT
      LAYER M5 ;
        RECT  80.7 0 80.724 0.192 ;
    END
  END g_front_2_u_front__q_data_in[289]
  PIN g_front_2_u_front__q_data_in[28]
    DIRECTION INPUT ;
    USE SIGNAL ;
    PORT
      LAYER M5 ;
        RECT  18.492 0 18.516 0.192 ;
    END
  END g_front_2_u_front__q_data_in[28]
  PIN g_front_2_u_front__q_data_in[290]
    DIRECTION INPUT ;
    USE SIGNAL ;
    PORT
      LAYER M5 ;
        RECT  80.94 0 80.964 0.192 ;
    END
  END g_front_2_u_front__q_data_in[290]
  PIN g_front_2_u_front__q_data_in[291]
    DIRECTION INPUT ;
    USE SIGNAL ;
    PORT
      LAYER M5 ;
        RECT  81.18 0 81.204 0.192 ;
    END
  END g_front_2_u_front__q_data_in[291]
  PIN g_front_2_u_front__q_data_in[292]
    DIRECTION INPUT ;
    USE SIGNAL ;
    PORT
      LAYER M5 ;
        RECT  81.42 0 81.444 0.192 ;
    END
  END g_front_2_u_front__q_data_in[292]
  PIN g_front_2_u_front__q_data_in[293]
    DIRECTION INPUT ;
    USE SIGNAL ;
    PORT
      LAYER M5 ;
        RECT  81.66 0 81.684 0.192 ;
    END
  END g_front_2_u_front__q_data_in[293]
  PIN g_front_2_u_front__q_data_in[294]
    DIRECTION INPUT ;
    USE SIGNAL ;
    PORT
      LAYER M5 ;
        RECT  81.9 0 81.924 0.192 ;
    END
  END g_front_2_u_front__q_data_in[294]
  PIN g_front_2_u_front__q_data_in[295]
    DIRECTION INPUT ;
    USE SIGNAL ;
    PORT
      LAYER M5 ;
        RECT  82.14 0 82.164 0.192 ;
    END
  END g_front_2_u_front__q_data_in[295]
  PIN g_front_2_u_front__q_data_in[296]
    DIRECTION INPUT ;
    USE SIGNAL ;
    PORT
      LAYER M5 ;
        RECT  82.38 0 82.404 0.192 ;
    END
  END g_front_2_u_front__q_data_in[296]
  PIN g_front_2_u_front__q_data_in[297]
    DIRECTION INPUT ;
    USE SIGNAL ;
    PORT
      LAYER M5 ;
        RECT  82.62 0 82.644 0.192 ;
    END
  END g_front_2_u_front__q_data_in[297]
  PIN g_front_2_u_front__q_data_in[298]
    DIRECTION INPUT ;
    USE SIGNAL ;
    PORT
      LAYER M5 ;
        RECT  82.86 0 82.884 0.192 ;
    END
  END g_front_2_u_front__q_data_in[298]
  PIN g_front_2_u_front__q_data_in[299]
    DIRECTION INPUT ;
    USE SIGNAL ;
    PORT
      LAYER M5 ;
        RECT  83.1 0 83.124 0.192 ;
    END
  END g_front_2_u_front__q_data_in[299]
  PIN g_front_2_u_front__q_data_in[29]
    DIRECTION INPUT ;
    USE SIGNAL ;
    PORT
      LAYER M5 ;
        RECT  18.732 0 18.756 0.192 ;
    END
  END g_front_2_u_front__q_data_in[29]
  PIN g_front_2_u_front__q_data_in[2]
    DIRECTION INPUT ;
    USE SIGNAL ;
    PORT
      LAYER M5 ;
        RECT  12.3 0 12.324 0.192 ;
    END
  END g_front_2_u_front__q_data_in[2]
  PIN g_front_2_u_front__q_data_in[300]
    DIRECTION INPUT ;
    USE SIGNAL ;
    PORT
      LAYER M5 ;
        RECT  83.292 0 83.316 0.192 ;
    END
  END g_front_2_u_front__q_data_in[300]
  PIN g_front_2_u_front__q_data_in[301]
    DIRECTION INPUT ;
    USE SIGNAL ;
    PORT
      LAYER M5 ;
        RECT  83.532 0 83.556 0.192 ;
    END
  END g_front_2_u_front__q_data_in[301]
  PIN g_front_2_u_front__q_data_in[302]
    DIRECTION INPUT ;
    USE SIGNAL ;
    PORT
      LAYER M5 ;
        RECT  83.772 0 83.796 0.192 ;
    END
  END g_front_2_u_front__q_data_in[302]
  PIN g_front_2_u_front__q_data_in[303]
    DIRECTION INPUT ;
    USE SIGNAL ;
    PORT
      LAYER M5 ;
        RECT  84.012 0 84.036 0.192 ;
    END
  END g_front_2_u_front__q_data_in[303]
  PIN g_front_2_u_front__q_data_in[304]
    DIRECTION INPUT ;
    USE SIGNAL ;
    PORT
      LAYER M5 ;
        RECT  84.252 0 84.276 0.192 ;
    END
  END g_front_2_u_front__q_data_in[304]
  PIN g_front_2_u_front__q_data_in[305]
    DIRECTION INPUT ;
    USE SIGNAL ;
    PORT
      LAYER M5 ;
        RECT  84.492 0 84.516 0.192 ;
    END
  END g_front_2_u_front__q_data_in[305]
  PIN g_front_2_u_front__q_data_in[306]
    DIRECTION INPUT ;
    USE SIGNAL ;
    PORT
      LAYER M5 ;
        RECT  84.732 0 84.756 0.192 ;
    END
  END g_front_2_u_front__q_data_in[306]
  PIN g_front_2_u_front__q_data_in[307]
    DIRECTION INPUT ;
    USE SIGNAL ;
    PORT
      LAYER M5 ;
        RECT  84.972 0 84.996 0.192 ;
    END
  END g_front_2_u_front__q_data_in[307]
  PIN g_front_2_u_front__q_data_in[308]
    DIRECTION INPUT ;
    USE SIGNAL ;
    PORT
      LAYER M5 ;
        RECT  85.212 0 85.236 0.192 ;
    END
  END g_front_2_u_front__q_data_in[308]
  PIN g_front_2_u_front__q_data_in[309]
    DIRECTION INPUT ;
    USE SIGNAL ;
    PORT
      LAYER M5 ;
        RECT  85.452 0 85.476 0.192 ;
    END
  END g_front_2_u_front__q_data_in[309]
  PIN g_front_2_u_front__q_data_in[30]
    DIRECTION INPUT ;
    USE SIGNAL ;
    PORT
      LAYER M5 ;
        RECT  18.972 0 18.996 0.192 ;
    END
  END g_front_2_u_front__q_data_in[30]
  PIN g_front_2_u_front__q_data_in[310]
    DIRECTION INPUT ;
    USE SIGNAL ;
    PORT
      LAYER M5 ;
        RECT  85.692 0 85.716 0.192 ;
    END
  END g_front_2_u_front__q_data_in[310]
  PIN g_front_2_u_front__q_data_in[311]
    DIRECTION INPUT ;
    USE SIGNAL ;
    PORT
      LAYER M5 ;
        RECT  85.932 0 85.956 0.192 ;
    END
  END g_front_2_u_front__q_data_in[311]
  PIN g_front_2_u_front__q_data_in[312]
    DIRECTION INPUT ;
    USE SIGNAL ;
    PORT
      LAYER M5 ;
        RECT  86.172 0 86.196 0.192 ;
    END
  END g_front_2_u_front__q_data_in[312]
  PIN g_front_2_u_front__q_data_in[313]
    DIRECTION INPUT ;
    USE SIGNAL ;
    PORT
      LAYER M5 ;
        RECT  86.412 0 86.436 0.192 ;
    END
  END g_front_2_u_front__q_data_in[313]
  PIN g_front_2_u_front__q_data_in[314]
    DIRECTION INPUT ;
    USE SIGNAL ;
    PORT
      LAYER M5 ;
        RECT  86.652 0 86.676 0.192 ;
    END
  END g_front_2_u_front__q_data_in[314]
  PIN g_front_2_u_front__q_data_in[315]
    DIRECTION INPUT ;
    USE SIGNAL ;
    PORT
      LAYER M5 ;
        RECT  86.892 0 86.916 0.192 ;
    END
  END g_front_2_u_front__q_data_in[315]
  PIN g_front_2_u_front__q_data_in[316]
    DIRECTION INPUT ;
    USE SIGNAL ;
    PORT
      LAYER M5 ;
        RECT  87.132 0 87.156 0.192 ;
    END
  END g_front_2_u_front__q_data_in[316]
  PIN g_front_2_u_front__q_data_in[317]
    DIRECTION INPUT ;
    USE SIGNAL ;
    PORT
      LAYER M5 ;
        RECT  87.372 0 87.396 0.192 ;
    END
  END g_front_2_u_front__q_data_in[317]
  PIN g_front_2_u_front__q_data_in[318]
    DIRECTION INPUT ;
    USE SIGNAL ;
    PORT
      LAYER M5 ;
        RECT  87.612 0 87.636 0.192 ;
    END
  END g_front_2_u_front__q_data_in[318]
  PIN g_front_2_u_front__q_data_in[319]
    DIRECTION INPUT ;
    USE SIGNAL ;
    PORT
      LAYER M5 ;
        RECT  87.852 0 87.876 0.192 ;
    END
  END g_front_2_u_front__q_data_in[319]
  PIN g_front_2_u_front__q_data_in[31]
    DIRECTION INPUT ;
    USE SIGNAL ;
    PORT
      LAYER M5 ;
        RECT  19.212 0 19.236 0.192 ;
    END
  END g_front_2_u_front__q_data_in[31]
  PIN g_front_2_u_front__q_data_in[320]
    DIRECTION INPUT ;
    USE SIGNAL ;
    PORT
      LAYER M5 ;
        RECT  88.092 0 88.116 0.192 ;
    END
  END g_front_2_u_front__q_data_in[320]
  PIN g_front_2_u_front__q_data_in[321]
    DIRECTION INPUT ;
    USE SIGNAL ;
    PORT
      LAYER M5 ;
        RECT  88.332 0 88.356 0.192 ;
    END
  END g_front_2_u_front__q_data_in[321]
  PIN g_front_2_u_front__q_data_in[322]
    DIRECTION INPUT ;
    USE SIGNAL ;
    PORT
      LAYER M5 ;
        RECT  88.572 0 88.596 0.192 ;
    END
  END g_front_2_u_front__q_data_in[322]
  PIN g_front_2_u_front__q_data_in[323]
    DIRECTION INPUT ;
    USE SIGNAL ;
    PORT
      LAYER M5 ;
        RECT  88.812 0 88.836 0.192 ;
    END
  END g_front_2_u_front__q_data_in[323]
  PIN g_front_2_u_front__q_data_in[324]
    DIRECTION INPUT ;
    USE SIGNAL ;
    PORT
      LAYER M5 ;
        RECT  89.052 0 89.076 0.192 ;
    END
  END g_front_2_u_front__q_data_in[324]
  PIN g_front_2_u_front__q_data_in[325]
    DIRECTION INPUT ;
    USE SIGNAL ;
    PORT
      LAYER M5 ;
        RECT  89.292 0 89.316 0.192 ;
    END
  END g_front_2_u_front__q_data_in[325]
  PIN g_front_2_u_front__q_data_in[326]
    DIRECTION INPUT ;
    USE SIGNAL ;
    PORT
      LAYER M5 ;
        RECT  89.532 0 89.556 0.192 ;
    END
  END g_front_2_u_front__q_data_in[326]
  PIN g_front_2_u_front__q_data_in[327]
    DIRECTION INPUT ;
    USE SIGNAL ;
    PORT
      LAYER M5 ;
        RECT  89.772 0 89.796 0.192 ;
    END
  END g_front_2_u_front__q_data_in[327]
  PIN g_front_2_u_front__q_data_in[328]
    DIRECTION INPUT ;
    USE SIGNAL ;
    PORT
      LAYER M5 ;
        RECT  90.012 0 90.036 0.192 ;
    END
  END g_front_2_u_front__q_data_in[328]
  PIN g_front_2_u_front__q_data_in[329]
    DIRECTION INPUT ;
    USE SIGNAL ;
    PORT
      LAYER M5 ;
        RECT  90.252 0 90.276 0.192 ;
    END
  END g_front_2_u_front__q_data_in[329]
  PIN g_front_2_u_front__q_data_in[32]
    DIRECTION INPUT ;
    USE SIGNAL ;
    PORT
      LAYER M5 ;
        RECT  19.452 0 19.476 0.192 ;
    END
  END g_front_2_u_front__q_data_in[32]
  PIN g_front_2_u_front__q_data_in[330]
    DIRECTION INPUT ;
    USE SIGNAL ;
    PORT
      LAYER M5 ;
        RECT  90.444 0 90.468 0.192 ;
    END
  END g_front_2_u_front__q_data_in[330]
  PIN g_front_2_u_front__q_data_in[331]
    DIRECTION INPUT ;
    USE SIGNAL ;
    PORT
      LAYER M5 ;
        RECT  90.684 0 90.708 0.192 ;
    END
  END g_front_2_u_front__q_data_in[331]
  PIN g_front_2_u_front__q_data_in[332]
    DIRECTION INPUT ;
    USE SIGNAL ;
    PORT
      LAYER M5 ;
        RECT  90.924 0 90.948 0.192 ;
    END
  END g_front_2_u_front__q_data_in[332]
  PIN g_front_2_u_front__q_data_in[333]
    DIRECTION INPUT ;
    USE SIGNAL ;
    PORT
      LAYER M5 ;
        RECT  91.164 0 91.188 0.192 ;
    END
  END g_front_2_u_front__q_data_in[333]
  PIN g_front_2_u_front__q_data_in[334]
    DIRECTION INPUT ;
    USE SIGNAL ;
    PORT
      LAYER M5 ;
        RECT  91.404 0 91.428 0.192 ;
    END
  END g_front_2_u_front__q_data_in[334]
  PIN g_front_2_u_front__q_data_in[335]
    DIRECTION INPUT ;
    USE SIGNAL ;
    PORT
      LAYER M5 ;
        RECT  91.644 0 91.668 0.192 ;
    END
  END g_front_2_u_front__q_data_in[335]
  PIN g_front_2_u_front__q_data_in[336]
    DIRECTION INPUT ;
    USE SIGNAL ;
    PORT
      LAYER M5 ;
        RECT  91.884 0 91.908 0.192 ;
    END
  END g_front_2_u_front__q_data_in[336]
  PIN g_front_2_u_front__q_data_in[337]
    DIRECTION INPUT ;
    USE SIGNAL ;
    PORT
      LAYER M5 ;
        RECT  92.124 0 92.148 0.192 ;
    END
  END g_front_2_u_front__q_data_in[337]
  PIN g_front_2_u_front__q_data_in[338]
    DIRECTION INPUT ;
    USE SIGNAL ;
    PORT
      LAYER M5 ;
        RECT  92.364 0 92.388 0.192 ;
    END
  END g_front_2_u_front__q_data_in[338]
  PIN g_front_2_u_front__q_data_in[339]
    DIRECTION INPUT ;
    USE SIGNAL ;
    PORT
      LAYER M5 ;
        RECT  92.604 0 92.628 0.192 ;
    END
  END g_front_2_u_front__q_data_in[339]
  PIN g_front_2_u_front__q_data_in[33]
    DIRECTION INPUT ;
    USE SIGNAL ;
    PORT
      LAYER M5 ;
        RECT  19.692 0 19.716 0.192 ;
    END
  END g_front_2_u_front__q_data_in[33]
  PIN g_front_2_u_front__q_data_in[340]
    DIRECTION INPUT ;
    USE SIGNAL ;
    PORT
      LAYER M5 ;
        RECT  92.844 0 92.868 0.192 ;
    END
  END g_front_2_u_front__q_data_in[340]
  PIN g_front_2_u_front__q_data_in[341]
    DIRECTION INPUT ;
    USE SIGNAL ;
    PORT
      LAYER M5 ;
        RECT  93.084 0 93.108 0.192 ;
    END
  END g_front_2_u_front__q_data_in[341]
  PIN g_front_2_u_front__q_data_in[342]
    DIRECTION INPUT ;
    USE SIGNAL ;
    PORT
      LAYER M5 ;
        RECT  93.324 0 93.348 0.192 ;
    END
  END g_front_2_u_front__q_data_in[342]
  PIN g_front_2_u_front__q_data_in[343]
    DIRECTION INPUT ;
    USE SIGNAL ;
    PORT
      LAYER M5 ;
        RECT  93.564 0 93.588 0.192 ;
    END
  END g_front_2_u_front__q_data_in[343]
  PIN g_front_2_u_front__q_data_in[344]
    DIRECTION INPUT ;
    USE SIGNAL ;
    PORT
      LAYER M5 ;
        RECT  93.804 0 93.828 0.192 ;
    END
  END g_front_2_u_front__q_data_in[344]
  PIN g_front_2_u_front__q_data_in[345]
    DIRECTION INPUT ;
    USE SIGNAL ;
    PORT
      LAYER M5 ;
        RECT  94.044 0 94.068 0.192 ;
    END
  END g_front_2_u_front__q_data_in[345]
  PIN g_front_2_u_front__q_data_in[346]
    DIRECTION INPUT ;
    USE SIGNAL ;
    PORT
      LAYER M5 ;
        RECT  94.284 0 94.308 0.192 ;
    END
  END g_front_2_u_front__q_data_in[346]
  PIN g_front_2_u_front__q_data_in[347]
    DIRECTION INPUT ;
    USE SIGNAL ;
    PORT
      LAYER M5 ;
        RECT  94.524 0 94.548 0.192 ;
    END
  END g_front_2_u_front__q_data_in[347]
  PIN g_front_2_u_front__q_data_in[348]
    DIRECTION INPUT ;
    USE SIGNAL ;
    PORT
      LAYER M5 ;
        RECT  94.764 0 94.788 0.192 ;
    END
  END g_front_2_u_front__q_data_in[348]
  PIN g_front_2_u_front__q_data_in[349]
    DIRECTION INPUT ;
    USE SIGNAL ;
    PORT
      LAYER M5 ;
        RECT  95.004 0 95.028 0.192 ;
    END
  END g_front_2_u_front__q_data_in[349]
  PIN g_front_2_u_front__q_data_in[34]
    DIRECTION INPUT ;
    USE SIGNAL ;
    PORT
      LAYER M5 ;
        RECT  19.884 0 19.908 0.192 ;
    END
  END g_front_2_u_front__q_data_in[34]
  PIN g_front_2_u_front__q_data_in[350]
    DIRECTION INPUT ;
    USE SIGNAL ;
    PORT
      LAYER M5 ;
        RECT  95.244 0 95.268 0.192 ;
    END
  END g_front_2_u_front__q_data_in[350]
  PIN g_front_2_u_front__q_data_in[351]
    DIRECTION INPUT ;
    USE SIGNAL ;
    PORT
      LAYER M5 ;
        RECT  95.484 0 95.508 0.192 ;
    END
  END g_front_2_u_front__q_data_in[351]
  PIN g_front_2_u_front__q_data_in[352]
    DIRECTION INPUT ;
    USE SIGNAL ;
    PORT
      LAYER M5 ;
        RECT  95.724 0 95.748 0.192 ;
    END
  END g_front_2_u_front__q_data_in[352]
  PIN g_front_2_u_front__q_data_in[353]
    DIRECTION INPUT ;
    USE SIGNAL ;
    PORT
      LAYER M5 ;
        RECT  95.964 0 95.988 0.192 ;
    END
  END g_front_2_u_front__q_data_in[353]
  PIN g_front_2_u_front__q_data_in[354]
    DIRECTION INPUT ;
    USE SIGNAL ;
    PORT
      LAYER M5 ;
        RECT  96.204 0 96.228 0.192 ;
    END
  END g_front_2_u_front__q_data_in[354]
  PIN g_front_2_u_front__q_data_in[355]
    DIRECTION INPUT ;
    USE SIGNAL ;
    PORT
      LAYER M5 ;
        RECT  96.444 0 96.468 0.192 ;
    END
  END g_front_2_u_front__q_data_in[355]
  PIN g_front_2_u_front__q_data_in[356]
    DIRECTION INPUT ;
    USE SIGNAL ;
    PORT
      LAYER M5 ;
        RECT  96.684 0 96.708 0.192 ;
    END
  END g_front_2_u_front__q_data_in[356]
  PIN g_front_2_u_front__q_data_in[357]
    DIRECTION INPUT ;
    USE SIGNAL ;
    PORT
      LAYER M5 ;
        RECT  96.924 0 96.948 0.192 ;
    END
  END g_front_2_u_front__q_data_in[357]
  PIN g_front_2_u_front__q_data_in[358]
    DIRECTION INPUT ;
    USE SIGNAL ;
    PORT
      LAYER M5 ;
        RECT  97.164 0 97.188 0.192 ;
    END
  END g_front_2_u_front__q_data_in[358]
  PIN g_front_2_u_front__q_data_in[359]
    DIRECTION INPUT ;
    USE SIGNAL ;
    PORT
      LAYER M5 ;
        RECT  97.404 0 97.428 0.192 ;
    END
  END g_front_2_u_front__q_data_in[359]
  PIN g_front_2_u_front__q_data_in[35]
    DIRECTION INPUT ;
    USE SIGNAL ;
    PORT
      LAYER M5 ;
        RECT  20.124 0 20.148 0.192 ;
    END
  END g_front_2_u_front__q_data_in[35]
  PIN g_front_2_u_front__q_data_in[360]
    DIRECTION INPUT ;
    USE SIGNAL ;
    PORT
      LAYER M5 ;
        RECT  97.596 0 97.62 0.192 ;
    END
  END g_front_2_u_front__q_data_in[360]
  PIN g_front_2_u_front__q_data_in[361]
    DIRECTION INPUT ;
    USE SIGNAL ;
    PORT
      LAYER M5 ;
        RECT  97.836 0 97.86 0.192 ;
    END
  END g_front_2_u_front__q_data_in[361]
  PIN g_front_2_u_front__q_data_in[362]
    DIRECTION INPUT ;
    USE SIGNAL ;
    PORT
      LAYER M5 ;
        RECT  98.076 0 98.1 0.192 ;
    END
  END g_front_2_u_front__q_data_in[362]
  PIN g_front_2_u_front__q_data_in[363]
    DIRECTION INPUT ;
    USE SIGNAL ;
    PORT
      LAYER M5 ;
        RECT  98.316 0 98.34 0.192 ;
    END
  END g_front_2_u_front__q_data_in[363]
  PIN g_front_2_u_front__q_data_in[364]
    DIRECTION INPUT ;
    USE SIGNAL ;
    PORT
      LAYER M5 ;
        RECT  98.556 0 98.58 0.192 ;
    END
  END g_front_2_u_front__q_data_in[364]
  PIN g_front_2_u_front__q_data_in[365]
    DIRECTION INPUT ;
    USE SIGNAL ;
    PORT
      LAYER M5 ;
        RECT  98.796 0 98.82 0.192 ;
    END
  END g_front_2_u_front__q_data_in[365]
  PIN g_front_2_u_front__q_data_in[366]
    DIRECTION INPUT ;
    USE SIGNAL ;
    PORT
      LAYER M5 ;
        RECT  99.036 0 99.06 0.192 ;
    END
  END g_front_2_u_front__q_data_in[366]
  PIN g_front_2_u_front__q_data_in[367]
    DIRECTION INPUT ;
    USE SIGNAL ;
    PORT
      LAYER M5 ;
        RECT  99.276 0 99.3 0.192 ;
    END
  END g_front_2_u_front__q_data_in[367]
  PIN g_front_2_u_front__q_data_in[368]
    DIRECTION INPUT ;
    USE SIGNAL ;
    PORT
      LAYER M5 ;
        RECT  99.516 0 99.54 0.192 ;
    END
  END g_front_2_u_front__q_data_in[368]
  PIN g_front_2_u_front__q_data_in[369]
    DIRECTION INPUT ;
    USE SIGNAL ;
    PORT
      LAYER M5 ;
        RECT  99.756 0 99.78 0.192 ;
    END
  END g_front_2_u_front__q_data_in[369]
  PIN g_front_2_u_front__q_data_in[36]
    DIRECTION INPUT ;
    USE SIGNAL ;
    PORT
      LAYER M5 ;
        RECT  20.364 0 20.388 0.192 ;
    END
  END g_front_2_u_front__q_data_in[36]
  PIN g_front_2_u_front__q_data_in[370]
    DIRECTION INPUT ;
    USE SIGNAL ;
    PORT
      LAYER M5 ;
        RECT  99.996 0 100.02 0.192 ;
    END
  END g_front_2_u_front__q_data_in[370]
  PIN g_front_2_u_front__q_data_in[371]
    DIRECTION INPUT ;
    USE SIGNAL ;
    PORT
      LAYER M5 ;
        RECT  100.236 0 100.26 0.192 ;
    END
  END g_front_2_u_front__q_data_in[371]
  PIN g_front_2_u_front__q_data_in[372]
    DIRECTION INPUT ;
    USE SIGNAL ;
    PORT
      LAYER M5 ;
        RECT  100.476 0 100.5 0.192 ;
    END
  END g_front_2_u_front__q_data_in[372]
  PIN g_front_2_u_front__q_data_in[373]
    DIRECTION INPUT ;
    USE SIGNAL ;
    PORT
      LAYER M5 ;
        RECT  100.716 0 100.74 0.192 ;
    END
  END g_front_2_u_front__q_data_in[373]
  PIN g_front_2_u_front__q_data_in[374]
    DIRECTION INPUT ;
    USE SIGNAL ;
    PORT
      LAYER M5 ;
        RECT  100.956 0 100.98 0.192 ;
    END
  END g_front_2_u_front__q_data_in[374]
  PIN g_front_2_u_front__q_data_in[375]
    DIRECTION INPUT ;
    USE SIGNAL ;
    PORT
      LAYER M5 ;
        RECT  101.196 0 101.22 0.192 ;
    END
  END g_front_2_u_front__q_data_in[375]
  PIN g_front_2_u_front__q_data_in[376]
    DIRECTION INPUT ;
    USE SIGNAL ;
    PORT
      LAYER M5 ;
        RECT  101.436 0 101.46 0.192 ;
    END
  END g_front_2_u_front__q_data_in[376]
  PIN g_front_2_u_front__q_data_in[377]
    DIRECTION INPUT ;
    USE SIGNAL ;
    PORT
      LAYER M5 ;
        RECT  101.676 0 101.7 0.192 ;
    END
  END g_front_2_u_front__q_data_in[377]
  PIN g_front_2_u_front__q_data_in[378]
    DIRECTION INPUT ;
    USE SIGNAL ;
    PORT
      LAYER M5 ;
        RECT  101.916 0 101.94 0.192 ;
    END
  END g_front_2_u_front__q_data_in[378]
  PIN g_front_2_u_front__q_data_in[379]
    DIRECTION INPUT ;
    USE SIGNAL ;
    PORT
      LAYER M5 ;
        RECT  102.156 0 102.18 0.192 ;
    END
  END g_front_2_u_front__q_data_in[379]
  PIN g_front_2_u_front__q_data_in[37]
    DIRECTION INPUT ;
    USE SIGNAL ;
    PORT
      LAYER M5 ;
        RECT  20.604 0 20.628 0.192 ;
    END
  END g_front_2_u_front__q_data_in[37]
  PIN g_front_2_u_front__q_data_in[380]
    DIRECTION INPUT ;
    USE SIGNAL ;
    PORT
      LAYER M5 ;
        RECT  102.396 0 102.42 0.192 ;
    END
  END g_front_2_u_front__q_data_in[380]
  PIN g_front_2_u_front__q_data_in[381]
    DIRECTION INPUT ;
    USE SIGNAL ;
    PORT
      LAYER M5 ;
        RECT  102.636 0 102.66 0.192 ;
    END
  END g_front_2_u_front__q_data_in[381]
  PIN g_front_2_u_front__q_data_in[382]
    DIRECTION INPUT ;
    USE SIGNAL ;
    PORT
      LAYER M5 ;
        RECT  102.876 0 102.9 0.192 ;
    END
  END g_front_2_u_front__q_data_in[382]
  PIN g_front_2_u_front__q_data_in[383]
    DIRECTION INPUT ;
    USE SIGNAL ;
    PORT
      LAYER M5 ;
        RECT  103.116 0 103.14 0.192 ;
    END
  END g_front_2_u_front__q_data_in[383]
  PIN g_front_2_u_front__q_data_in[384]
    DIRECTION INPUT ;
    USE SIGNAL ;
    PORT
      LAYER M5 ;
        RECT  103.356 0 103.38 0.192 ;
    END
  END g_front_2_u_front__q_data_in[384]
  PIN g_front_2_u_front__q_data_in[385]
    DIRECTION INPUT ;
    USE SIGNAL ;
    PORT
      LAYER M5 ;
        RECT  103.596 0 103.62 0.192 ;
    END
  END g_front_2_u_front__q_data_in[385]
  PIN g_front_2_u_front__q_data_in[386]
    DIRECTION INPUT ;
    USE SIGNAL ;
    PORT
      LAYER M5 ;
        RECT  103.836 0 103.86 0.192 ;
    END
  END g_front_2_u_front__q_data_in[386]
  PIN g_front_2_u_front__q_data_in[387]
    DIRECTION INPUT ;
    USE SIGNAL ;
    PORT
      LAYER M5 ;
        RECT  104.076 0 104.1 0.192 ;
    END
  END g_front_2_u_front__q_data_in[387]
  PIN g_front_2_u_front__q_data_in[388]
    DIRECTION INPUT ;
    USE SIGNAL ;
    PORT
      LAYER M5 ;
        RECT  104.316 0 104.34 0.192 ;
    END
  END g_front_2_u_front__q_data_in[388]
  PIN g_front_2_u_front__q_data_in[389]
    DIRECTION INPUT ;
    USE SIGNAL ;
    PORT
      LAYER M5 ;
        RECT  104.508 0 104.532 0.192 ;
    END
  END g_front_2_u_front__q_data_in[389]
  PIN g_front_2_u_front__q_data_in[38]
    DIRECTION INPUT ;
    USE SIGNAL ;
    PORT
      LAYER M5 ;
        RECT  20.844 0 20.868 0.192 ;
    END
  END g_front_2_u_front__q_data_in[38]
  PIN g_front_2_u_front__q_data_in[390]
    DIRECTION INPUT ;
    USE SIGNAL ;
    PORT
      LAYER M5 ;
        RECT  104.748 0 104.772 0.192 ;
    END
  END g_front_2_u_front__q_data_in[390]
  PIN g_front_2_u_front__q_data_in[391]
    DIRECTION INPUT ;
    USE SIGNAL ;
    PORT
      LAYER M5 ;
        RECT  104.988 0 105.012 0.192 ;
    END
  END g_front_2_u_front__q_data_in[391]
  PIN g_front_2_u_front__q_data_in[392]
    DIRECTION INPUT ;
    USE SIGNAL ;
    PORT
      LAYER M5 ;
        RECT  105.228 0 105.252 0.192 ;
    END
  END g_front_2_u_front__q_data_in[392]
  PIN g_front_2_u_front__q_data_in[393]
    DIRECTION INPUT ;
    USE SIGNAL ;
    PORT
      LAYER M5 ;
        RECT  105.468 0 105.492 0.192 ;
    END
  END g_front_2_u_front__q_data_in[393]
  PIN g_front_2_u_front__q_data_in[394]
    DIRECTION INPUT ;
    USE SIGNAL ;
    PORT
      LAYER M5 ;
        RECT  105.708 0 105.732 0.192 ;
    END
  END g_front_2_u_front__q_data_in[394]
  PIN g_front_2_u_front__q_data_in[395]
    DIRECTION INPUT ;
    USE SIGNAL ;
    PORT
      LAYER M5 ;
        RECT  105.948 0 105.972 0.192 ;
    END
  END g_front_2_u_front__q_data_in[395]
  PIN g_front_2_u_front__q_data_in[396]
    DIRECTION INPUT ;
    USE SIGNAL ;
    PORT
      LAYER M5 ;
        RECT  106.188 0 106.212 0.192 ;
    END
  END g_front_2_u_front__q_data_in[396]
  PIN g_front_2_u_front__q_data_in[397]
    DIRECTION INPUT ;
    USE SIGNAL ;
    PORT
      LAYER M5 ;
        RECT  106.428 0 106.452 0.192 ;
    END
  END g_front_2_u_front__q_data_in[397]
  PIN g_front_2_u_front__q_data_in[398]
    DIRECTION INPUT ;
    USE SIGNAL ;
    PORT
      LAYER M5 ;
        RECT  106.668 0 106.692 0.192 ;
    END
  END g_front_2_u_front__q_data_in[398]
  PIN g_front_2_u_front__q_data_in[399]
    DIRECTION INPUT ;
    USE SIGNAL ;
    PORT
      LAYER M5 ;
        RECT  106.908 0 106.932 0.192 ;
    END
  END g_front_2_u_front__q_data_in[399]
  PIN g_front_2_u_front__q_data_in[39]
    DIRECTION INPUT ;
    USE SIGNAL ;
    PORT
      LAYER M5 ;
        RECT  21.084 0 21.108 0.192 ;
    END
  END g_front_2_u_front__q_data_in[39]
  PIN g_front_2_u_front__q_data_in[3]
    DIRECTION INPUT ;
    USE SIGNAL ;
    PORT
      LAYER M5 ;
        RECT  12.54 0 12.564 0.192 ;
    END
  END g_front_2_u_front__q_data_in[3]
  PIN g_front_2_u_front__q_data_in[400]
    DIRECTION INPUT ;
    USE SIGNAL ;
    PORT
      LAYER M5 ;
        RECT  107.148 0 107.172 0.192 ;
    END
  END g_front_2_u_front__q_data_in[400]
  PIN g_front_2_u_front__q_data_in[401]
    DIRECTION INPUT ;
    USE SIGNAL ;
    PORT
      LAYER M5 ;
        RECT  107.388 0 107.412 0.192 ;
    END
  END g_front_2_u_front__q_data_in[401]
  PIN g_front_2_u_front__q_data_in[402]
    DIRECTION INPUT ;
    USE SIGNAL ;
    PORT
      LAYER M5 ;
        RECT  107.628 0 107.652 0.192 ;
    END
  END g_front_2_u_front__q_data_in[402]
  PIN g_front_2_u_front__q_data_in[403]
    DIRECTION INPUT ;
    USE SIGNAL ;
    PORT
      LAYER M5 ;
        RECT  107.868 0 107.892 0.192 ;
    END
  END g_front_2_u_front__q_data_in[403]
  PIN g_front_2_u_front__q_data_in[404]
    DIRECTION INPUT ;
    USE SIGNAL ;
    PORT
      LAYER M5 ;
        RECT  108.108 0 108.132 0.192 ;
    END
  END g_front_2_u_front__q_data_in[404]
  PIN g_front_2_u_front__q_data_in[405]
    DIRECTION INPUT ;
    USE SIGNAL ;
    PORT
      LAYER M5 ;
        RECT  108.348 0 108.372 0.192 ;
    END
  END g_front_2_u_front__q_data_in[405]
  PIN g_front_2_u_front__q_data_in[406]
    DIRECTION INPUT ;
    USE SIGNAL ;
    PORT
      LAYER M5 ;
        RECT  108.588 0 108.612 0.192 ;
    END
  END g_front_2_u_front__q_data_in[406]
  PIN g_front_2_u_front__q_data_in[407]
    DIRECTION INPUT ;
    USE SIGNAL ;
    PORT
      LAYER M5 ;
        RECT  108.828 0 108.852 0.192 ;
    END
  END g_front_2_u_front__q_data_in[407]
  PIN g_front_2_u_front__q_data_in[408]
    DIRECTION INPUT ;
    USE SIGNAL ;
    PORT
      LAYER M5 ;
        RECT  109.068 0 109.092 0.192 ;
    END
  END g_front_2_u_front__q_data_in[408]
  PIN g_front_2_u_front__q_data_in[409]
    DIRECTION INPUT ;
    USE SIGNAL ;
    PORT
      LAYER M5 ;
        RECT  109.308 0 109.332 0.192 ;
    END
  END g_front_2_u_front__q_data_in[409]
  PIN g_front_2_u_front__q_data_in[40]
    DIRECTION INPUT ;
    USE SIGNAL ;
    PORT
      LAYER M5 ;
        RECT  21.324 0 21.348 0.192 ;
    END
  END g_front_2_u_front__q_data_in[40]
  PIN g_front_2_u_front__q_data_in[410]
    DIRECTION INPUT ;
    USE SIGNAL ;
    PORT
      LAYER M5 ;
        RECT  109.548 0 109.572 0.192 ;
    END
  END g_front_2_u_front__q_data_in[410]
  PIN g_front_2_u_front__q_data_in[411]
    DIRECTION INPUT ;
    USE SIGNAL ;
    PORT
      LAYER M5 ;
        RECT  109.788 0 109.812 0.192 ;
    END
  END g_front_2_u_front__q_data_in[411]
  PIN g_front_2_u_front__q_data_in[412]
    DIRECTION INPUT ;
    USE SIGNAL ;
    PORT
      LAYER M5 ;
        RECT  110.028 0 110.052 0.192 ;
    END
  END g_front_2_u_front__q_data_in[412]
  PIN g_front_2_u_front__q_data_in[413]
    DIRECTION INPUT ;
    USE SIGNAL ;
    PORT
      LAYER M5 ;
        RECT  110.268 0 110.292 0.192 ;
    END
  END g_front_2_u_front__q_data_in[413]
  PIN g_front_2_u_front__q_data_in[414]
    DIRECTION INPUT ;
    USE SIGNAL ;
    PORT
      LAYER M5 ;
        RECT  110.508 0 110.532 0.192 ;
    END
  END g_front_2_u_front__q_data_in[414]
  PIN g_front_2_u_front__q_data_in[415]
    DIRECTION INPUT ;
    USE SIGNAL ;
    PORT
      LAYER M5 ;
        RECT  110.748 0 110.772 0.192 ;
    END
  END g_front_2_u_front__q_data_in[415]
  PIN g_front_2_u_front__q_data_in[416]
    DIRECTION INPUT ;
    USE SIGNAL ;
    PORT
      LAYER M5 ;
        RECT  110.988 0 111.012 0.192 ;
    END
  END g_front_2_u_front__q_data_in[416]
  PIN g_front_2_u_front__q_data_in[417]
    DIRECTION INPUT ;
    USE SIGNAL ;
    PORT
      LAYER M5 ;
        RECT  111.228 0 111.252 0.192 ;
    END
  END g_front_2_u_front__q_data_in[417]
  PIN g_front_2_u_front__q_data_in[418]
    DIRECTION INPUT ;
    USE SIGNAL ;
    PORT
      LAYER M5 ;
        RECT  111.468 0 111.492 0.192 ;
    END
  END g_front_2_u_front__q_data_in[418]
  PIN g_front_2_u_front__q_data_in[419]
    DIRECTION INPUT ;
    USE SIGNAL ;
    PORT
      LAYER M5 ;
        RECT  111.66 0 111.684 0.192 ;
    END
  END g_front_2_u_front__q_data_in[419]
  PIN g_front_2_u_front__q_data_in[41]
    DIRECTION INPUT ;
    USE SIGNAL ;
    PORT
      LAYER M5 ;
        RECT  21.564 0 21.588 0.192 ;
    END
  END g_front_2_u_front__q_data_in[41]
  PIN g_front_2_u_front__q_data_in[420]
    DIRECTION INPUT ;
    USE SIGNAL ;
    PORT
      LAYER M5 ;
        RECT  111.9 0 111.924 0.192 ;
    END
  END g_front_2_u_front__q_data_in[420]
  PIN g_front_2_u_front__q_data_in[421]
    DIRECTION INPUT ;
    USE SIGNAL ;
    PORT
      LAYER M5 ;
        RECT  112.14 0 112.164 0.192 ;
    END
  END g_front_2_u_front__q_data_in[421]
  PIN g_front_2_u_front__q_data_in[422]
    DIRECTION INPUT ;
    USE SIGNAL ;
    PORT
      LAYER M5 ;
        RECT  112.38 0 112.404 0.192 ;
    END
  END g_front_2_u_front__q_data_in[422]
  PIN g_front_2_u_front__q_data_in[423]
    DIRECTION INPUT ;
    USE SIGNAL ;
    PORT
      LAYER M5 ;
        RECT  112.62 0 112.644 0.192 ;
    END
  END g_front_2_u_front__q_data_in[423]
  PIN g_front_2_u_front__q_data_in[424]
    DIRECTION INPUT ;
    USE SIGNAL ;
    PORT
      LAYER M5 ;
        RECT  112.86 0 112.884 0.192 ;
    END
  END g_front_2_u_front__q_data_in[424]
  PIN g_front_2_u_front__q_data_in[425]
    DIRECTION INPUT ;
    USE SIGNAL ;
    PORT
      LAYER M5 ;
        RECT  113.1 0 113.124 0.192 ;
    END
  END g_front_2_u_front__q_data_in[425]
  PIN g_front_2_u_front__q_data_in[426]
    DIRECTION INPUT ;
    USE SIGNAL ;
    PORT
      LAYER M5 ;
        RECT  113.34 0 113.364 0.192 ;
    END
  END g_front_2_u_front__q_data_in[426]
  PIN g_front_2_u_front__q_data_in[427]
    DIRECTION INPUT ;
    USE SIGNAL ;
    PORT
      LAYER M5 ;
        RECT  113.58 0 113.604 0.192 ;
    END
  END g_front_2_u_front__q_data_in[427]
  PIN g_front_2_u_front__q_data_in[428]
    DIRECTION INPUT ;
    USE SIGNAL ;
    PORT
      LAYER M5 ;
        RECT  113.82 0 113.844 0.192 ;
    END
  END g_front_2_u_front__q_data_in[428]
  PIN g_front_2_u_front__q_data_in[429]
    DIRECTION INPUT ;
    USE SIGNAL ;
    PORT
      LAYER M5 ;
        RECT  114.06 0 114.084 0.192 ;
    END
  END g_front_2_u_front__q_data_in[429]
  PIN g_front_2_u_front__q_data_in[42]
    DIRECTION INPUT ;
    USE SIGNAL ;
    PORT
      LAYER M5 ;
        RECT  21.804 0 21.828 0.192 ;
    END
  END g_front_2_u_front__q_data_in[42]
  PIN g_front_2_u_front__q_data_in[430]
    DIRECTION INPUT ;
    USE SIGNAL ;
    PORT
      LAYER M5 ;
        RECT  114.3 0 114.324 0.192 ;
    END
  END g_front_2_u_front__q_data_in[430]
  PIN g_front_2_u_front__q_data_in[431]
    DIRECTION INPUT ;
    USE SIGNAL ;
    PORT
      LAYER M5 ;
        RECT  114.54 0 114.564 0.192 ;
    END
  END g_front_2_u_front__q_data_in[431]
  PIN g_front_2_u_front__q_data_in[432]
    DIRECTION INPUT ;
    USE SIGNAL ;
    PORT
      LAYER M5 ;
        RECT  114.78 0 114.804 0.192 ;
    END
  END g_front_2_u_front__q_data_in[432]
  PIN g_front_2_u_front__q_data_in[433]
    DIRECTION INPUT ;
    USE SIGNAL ;
    PORT
      LAYER M5 ;
        RECT  115.02 0 115.044 0.192 ;
    END
  END g_front_2_u_front__q_data_in[433]
  PIN g_front_2_u_front__q_data_in[434]
    DIRECTION INPUT ;
    USE SIGNAL ;
    PORT
      LAYER M5 ;
        RECT  115.26 0 115.284 0.192 ;
    END
  END g_front_2_u_front__q_data_in[434]
  PIN g_front_2_u_front__q_data_in[435]
    DIRECTION INPUT ;
    USE SIGNAL ;
    PORT
      LAYER M5 ;
        RECT  115.5 0 115.524 0.192 ;
    END
  END g_front_2_u_front__q_data_in[435]
  PIN g_front_2_u_front__q_data_in[436]
    DIRECTION INPUT ;
    USE SIGNAL ;
    PORT
      LAYER M5 ;
        RECT  115.74 0 115.764 0.192 ;
    END
  END g_front_2_u_front__q_data_in[436]
  PIN g_front_2_u_front__q_data_in[437]
    DIRECTION INPUT ;
    USE SIGNAL ;
    PORT
      LAYER M5 ;
        RECT  115.98 0 116.004 0.192 ;
    END
  END g_front_2_u_front__q_data_in[437]
  PIN g_front_2_u_front__q_data_in[438]
    DIRECTION INPUT ;
    USE SIGNAL ;
    PORT
      LAYER M5 ;
        RECT  116.22 0 116.244 0.192 ;
    END
  END g_front_2_u_front__q_data_in[438]
  PIN g_front_2_u_front__q_data_in[439]
    DIRECTION INPUT ;
    USE SIGNAL ;
    PORT
      LAYER M5 ;
        RECT  116.46 0 116.484 0.192 ;
    END
  END g_front_2_u_front__q_data_in[439]
  PIN g_front_2_u_front__q_data_in[43]
    DIRECTION INPUT ;
    USE SIGNAL ;
    PORT
      LAYER M5 ;
        RECT  22.044 0 22.068 0.192 ;
    END
  END g_front_2_u_front__q_data_in[43]
  PIN g_front_2_u_front__q_data_in[440]
    DIRECTION INPUT ;
    USE SIGNAL ;
    PORT
      LAYER M5 ;
        RECT  116.7 0 116.724 0.192 ;
    END
  END g_front_2_u_front__q_data_in[440]
  PIN g_front_2_u_front__q_data_in[441]
    DIRECTION INPUT ;
    USE SIGNAL ;
    PORT
      LAYER M5 ;
        RECT  116.94 0 116.964 0.192 ;
    END
  END g_front_2_u_front__q_data_in[441]
  PIN g_front_2_u_front__q_data_in[442]
    DIRECTION INPUT ;
    USE SIGNAL ;
    PORT
      LAYER M5 ;
        RECT  117.18 0 117.204 0.192 ;
    END
  END g_front_2_u_front__q_data_in[442]
  PIN g_front_2_u_front__q_data_in[443]
    DIRECTION INPUT ;
    USE SIGNAL ;
    PORT
      LAYER M5 ;
        RECT  117.42 0 117.444 0.192 ;
    END
  END g_front_2_u_front__q_data_in[443]
  PIN g_front_2_u_front__q_data_in[444]
    DIRECTION INPUT ;
    USE SIGNAL ;
    PORT
      LAYER M5 ;
        RECT  117.66 0 117.684 0.192 ;
    END
  END g_front_2_u_front__q_data_in[444]
  PIN g_front_2_u_front__q_data_in[445]
    DIRECTION INPUT ;
    USE SIGNAL ;
    PORT
      LAYER M5 ;
        RECT  117.9 0 117.924 0.192 ;
    END
  END g_front_2_u_front__q_data_in[445]
  PIN g_front_2_u_front__q_data_in[446]
    DIRECTION INPUT ;
    USE SIGNAL ;
    PORT
      LAYER M5 ;
        RECT  118.14 0 118.164 0.192 ;
    END
  END g_front_2_u_front__q_data_in[446]
  PIN g_front_2_u_front__q_data_in[447]
    DIRECTION INPUT ;
    USE SIGNAL ;
    PORT
      LAYER M5 ;
        RECT  118.38 0 118.404 0.192 ;
    END
  END g_front_2_u_front__q_data_in[447]
  PIN g_front_2_u_front__q_data_in[448]
    DIRECTION INPUT ;
    USE SIGNAL ;
    PORT
      LAYER M5 ;
        RECT  118.572 0 118.596 0.192 ;
    END
  END g_front_2_u_front__q_data_in[448]
  PIN g_front_2_u_front__q_data_in[449]
    DIRECTION INPUT ;
    USE SIGNAL ;
    PORT
      LAYER M5 ;
        RECT  118.812 0 118.836 0.192 ;
    END
  END g_front_2_u_front__q_data_in[449]
  PIN g_front_2_u_front__q_data_in[44]
    DIRECTION INPUT ;
    USE SIGNAL ;
    PORT
      LAYER M5 ;
        RECT  22.284 0 22.308 0.192 ;
    END
  END g_front_2_u_front__q_data_in[44]
  PIN g_front_2_u_front__q_data_in[450]
    DIRECTION INPUT ;
    USE SIGNAL ;
    PORT
      LAYER M5 ;
        RECT  119.052 0 119.076 0.192 ;
    END
  END g_front_2_u_front__q_data_in[450]
  PIN g_front_2_u_front__q_data_in[451]
    DIRECTION INPUT ;
    USE SIGNAL ;
    PORT
      LAYER M5 ;
        RECT  119.292 0 119.316 0.192 ;
    END
  END g_front_2_u_front__q_data_in[451]
  PIN g_front_2_u_front__q_data_in[452]
    DIRECTION INPUT ;
    USE SIGNAL ;
    PORT
      LAYER M5 ;
        RECT  119.532 0 119.556 0.192 ;
    END
  END g_front_2_u_front__q_data_in[452]
  PIN g_front_2_u_front__q_data_in[453]
    DIRECTION INPUT ;
    USE SIGNAL ;
    PORT
      LAYER M5 ;
        RECT  119.772 0 119.796 0.192 ;
    END
  END g_front_2_u_front__q_data_in[453]
  PIN g_front_2_u_front__q_data_in[454]
    DIRECTION INPUT ;
    USE SIGNAL ;
    PORT
      LAYER M5 ;
        RECT  120.012 0 120.036 0.192 ;
    END
  END g_front_2_u_front__q_data_in[454]
  PIN g_front_2_u_front__q_data_in[455]
    DIRECTION INPUT ;
    USE SIGNAL ;
    PORT
      LAYER M5 ;
        RECT  120.252 0 120.276 0.192 ;
    END
  END g_front_2_u_front__q_data_in[455]
  PIN g_front_2_u_front__q_data_in[456]
    DIRECTION INPUT ;
    USE SIGNAL ;
    PORT
      LAYER M5 ;
        RECT  120.492 0 120.516 0.192 ;
    END
  END g_front_2_u_front__q_data_in[456]
  PIN g_front_2_u_front__q_data_in[457]
    DIRECTION INPUT ;
    USE SIGNAL ;
    PORT
      LAYER M5 ;
        RECT  120.732 0 120.756 0.192 ;
    END
  END g_front_2_u_front__q_data_in[457]
  PIN g_front_2_u_front__q_data_in[458]
    DIRECTION INPUT ;
    USE SIGNAL ;
    PORT
      LAYER M5 ;
        RECT  120.972 0 120.996 0.192 ;
    END
  END g_front_2_u_front__q_data_in[458]
  PIN g_front_2_u_front__q_data_in[459]
    DIRECTION INPUT ;
    USE SIGNAL ;
    PORT
      LAYER M5 ;
        RECT  121.212 0 121.236 0.192 ;
    END
  END g_front_2_u_front__q_data_in[459]
  PIN g_front_2_u_front__q_data_in[45]
    DIRECTION INPUT ;
    USE SIGNAL ;
    PORT
      LAYER M5 ;
        RECT  22.524 0 22.548 0.192 ;
    END
  END g_front_2_u_front__q_data_in[45]
  PIN g_front_2_u_front__q_data_in[460]
    DIRECTION INPUT ;
    USE SIGNAL ;
    PORT
      LAYER M5 ;
        RECT  121.452 0 121.476 0.192 ;
    END
  END g_front_2_u_front__q_data_in[460]
  PIN g_front_2_u_front__q_data_in[461]
    DIRECTION INPUT ;
    USE SIGNAL ;
    PORT
      LAYER M5 ;
        RECT  121.692 0 121.716 0.192 ;
    END
  END g_front_2_u_front__q_data_in[461]
  PIN g_front_2_u_front__q_data_in[462]
    DIRECTION INPUT ;
    USE SIGNAL ;
    PORT
      LAYER M5 ;
        RECT  121.932 0 121.956 0.192 ;
    END
  END g_front_2_u_front__q_data_in[462]
  PIN g_front_2_u_front__q_data_in[463]
    DIRECTION INPUT ;
    USE SIGNAL ;
    PORT
      LAYER M5 ;
        RECT  122.172 0 122.196 0.192 ;
    END
  END g_front_2_u_front__q_data_in[463]
  PIN g_front_2_u_front__q_data_in[464]
    DIRECTION INPUT ;
    USE SIGNAL ;
    PORT
      LAYER M5 ;
        RECT  122.412 0 122.436 0.192 ;
    END
  END g_front_2_u_front__q_data_in[464]
  PIN g_front_2_u_front__q_data_in[465]
    DIRECTION INPUT ;
    USE SIGNAL ;
    PORT
      LAYER M5 ;
        RECT  122.652 0 122.676 0.192 ;
    END
  END g_front_2_u_front__q_data_in[465]
  PIN g_front_2_u_front__q_data_in[466]
    DIRECTION INPUT ;
    USE SIGNAL ;
    PORT
      LAYER M5 ;
        RECT  122.892 0 122.916 0.192 ;
    END
  END g_front_2_u_front__q_data_in[466]
  PIN g_front_2_u_front__q_data_in[467]
    DIRECTION INPUT ;
    USE SIGNAL ;
    PORT
      LAYER M5 ;
        RECT  123.132 0 123.156 0.192 ;
    END
  END g_front_2_u_front__q_data_in[467]
  PIN g_front_2_u_front__q_data_in[468]
    DIRECTION INPUT ;
    USE SIGNAL ;
    PORT
      LAYER M5 ;
        RECT  123.372 0 123.396 0.192 ;
    END
  END g_front_2_u_front__q_data_in[468]
  PIN g_front_2_u_front__q_data_in[469]
    DIRECTION INPUT ;
    USE SIGNAL ;
    PORT
      LAYER M5 ;
        RECT  123.612 0 123.636 0.192 ;
    END
  END g_front_2_u_front__q_data_in[469]
  PIN g_front_2_u_front__q_data_in[46]
    DIRECTION INPUT ;
    USE SIGNAL ;
    PORT
      LAYER M5 ;
        RECT  22.764 0 22.788 0.192 ;
    END
  END g_front_2_u_front__q_data_in[46]
  PIN g_front_2_u_front__q_data_in[470]
    DIRECTION INPUT ;
    USE SIGNAL ;
    PORT
      LAYER M5 ;
        RECT  123.852 0 123.876 0.192 ;
    END
  END g_front_2_u_front__q_data_in[470]
  PIN g_front_2_u_front__q_data_in[471]
    DIRECTION INPUT ;
    USE SIGNAL ;
    PORT
      LAYER M5 ;
        RECT  124.092 0 124.116 0.192 ;
    END
  END g_front_2_u_front__q_data_in[471]
  PIN g_front_2_u_front__q_data_in[472]
    DIRECTION INPUT ;
    USE SIGNAL ;
    PORT
      LAYER M5 ;
        RECT  124.332 0 124.356 0.192 ;
    END
  END g_front_2_u_front__q_data_in[472]
  PIN g_front_2_u_front__q_data_in[473]
    DIRECTION INPUT ;
    USE SIGNAL ;
    PORT
      LAYER M5 ;
        RECT  124.572 0 124.596 0.192 ;
    END
  END g_front_2_u_front__q_data_in[473]
  PIN g_front_2_u_front__q_data_in[474]
    DIRECTION INPUT ;
    USE SIGNAL ;
    PORT
      LAYER M5 ;
        RECT  124.812 0 124.836 0.192 ;
    END
  END g_front_2_u_front__q_data_in[474]
  PIN g_front_2_u_front__q_data_in[475]
    DIRECTION INPUT ;
    USE SIGNAL ;
    PORT
      LAYER M5 ;
        RECT  125.052 0 125.076 0.192 ;
    END
  END g_front_2_u_front__q_data_in[475]
  PIN g_front_2_u_front__q_data_in[476]
    DIRECTION INPUT ;
    USE SIGNAL ;
    PORT
      LAYER M5 ;
        RECT  125.292 0 125.316 0.192 ;
    END
  END g_front_2_u_front__q_data_in[476]
  PIN g_front_2_u_front__q_data_in[477]
    DIRECTION INPUT ;
    USE SIGNAL ;
    PORT
      LAYER M5 ;
        RECT  125.532 0 125.556 0.192 ;
    END
  END g_front_2_u_front__q_data_in[477]
  PIN g_front_2_u_front__q_data_in[478]
    DIRECTION INPUT ;
    USE SIGNAL ;
    PORT
      LAYER M5 ;
        RECT  125.724 0 125.748 0.192 ;
    END
  END g_front_2_u_front__q_data_in[478]
  PIN g_front_2_u_front__q_data_in[479]
    DIRECTION INPUT ;
    USE SIGNAL ;
    PORT
      LAYER M5 ;
        RECT  125.964 0 125.988 0.192 ;
    END
  END g_front_2_u_front__q_data_in[479]
  PIN g_front_2_u_front__q_data_in[47]
    DIRECTION INPUT ;
    USE SIGNAL ;
    PORT
      LAYER M5 ;
        RECT  23.004 0 23.028 0.192 ;
    END
  END g_front_2_u_front__q_data_in[47]
  PIN g_front_2_u_front__q_data_in[480]
    DIRECTION INPUT ;
    USE SIGNAL ;
    PORT
      LAYER M5 ;
        RECT  126.204 0 126.228 0.192 ;
    END
  END g_front_2_u_front__q_data_in[480]
  PIN g_front_2_u_front__q_data_in[481]
    DIRECTION INPUT ;
    USE SIGNAL ;
    PORT
      LAYER M5 ;
        RECT  126.444 0 126.468 0.192 ;
    END
  END g_front_2_u_front__q_data_in[481]
  PIN g_front_2_u_front__q_data_in[482]
    DIRECTION INPUT ;
    USE SIGNAL ;
    PORT
      LAYER M5 ;
        RECT  126.684 0 126.708 0.192 ;
    END
  END g_front_2_u_front__q_data_in[482]
  PIN g_front_2_u_front__q_data_in[483]
    DIRECTION INPUT ;
    USE SIGNAL ;
    PORT
      LAYER M5 ;
        RECT  126.924 0 126.948 0.192 ;
    END
  END g_front_2_u_front__q_data_in[483]
  PIN g_front_2_u_front__q_data_in[484]
    DIRECTION INPUT ;
    USE SIGNAL ;
    PORT
      LAYER M5 ;
        RECT  127.164 0 127.188 0.192 ;
    END
  END g_front_2_u_front__q_data_in[484]
  PIN g_front_2_u_front__q_data_in[485]
    DIRECTION INPUT ;
    USE SIGNAL ;
    PORT
      LAYER M5 ;
        RECT  127.404 0 127.428 0.192 ;
    END
  END g_front_2_u_front__q_data_in[485]
  PIN g_front_2_u_front__q_data_in[486]
    DIRECTION INPUT ;
    USE SIGNAL ;
    PORT
      LAYER M5 ;
        RECT  127.644 0 127.668 0.192 ;
    END
  END g_front_2_u_front__q_data_in[486]
  PIN g_front_2_u_front__q_data_in[487]
    DIRECTION INPUT ;
    USE SIGNAL ;
    PORT
      LAYER M5 ;
        RECT  127.884 0 127.908 0.192 ;
    END
  END g_front_2_u_front__q_data_in[487]
  PIN g_front_2_u_front__q_data_in[488]
    DIRECTION INPUT ;
    USE SIGNAL ;
    PORT
      LAYER M5 ;
        RECT  128.124 0 128.148 0.192 ;
    END
  END g_front_2_u_front__q_data_in[488]
  PIN g_front_2_u_front__q_data_in[489]
    DIRECTION INPUT ;
    USE SIGNAL ;
    PORT
      LAYER M5 ;
        RECT  128.364 0 128.388 0.192 ;
    END
  END g_front_2_u_front__q_data_in[489]
  PIN g_front_2_u_front__q_data_in[48]
    DIRECTION INPUT ;
    USE SIGNAL ;
    PORT
      LAYER M5 ;
        RECT  23.244 0 23.268 0.192 ;
    END
  END g_front_2_u_front__q_data_in[48]
  PIN g_front_2_u_front__q_data_in[490]
    DIRECTION INPUT ;
    USE SIGNAL ;
    PORT
      LAYER M5 ;
        RECT  128.604 0 128.628 0.192 ;
    END
  END g_front_2_u_front__q_data_in[490]
  PIN g_front_2_u_front__q_data_in[491]
    DIRECTION INPUT ;
    USE SIGNAL ;
    PORT
      LAYER M5 ;
        RECT  128.844 0 128.868 0.192 ;
    END
  END g_front_2_u_front__q_data_in[491]
  PIN g_front_2_u_front__q_data_in[492]
    DIRECTION INPUT ;
    USE SIGNAL ;
    PORT
      LAYER M5 ;
        RECT  129.084 0 129.108 0.192 ;
    END
  END g_front_2_u_front__q_data_in[492]
  PIN g_front_2_u_front__q_data_in[493]
    DIRECTION INPUT ;
    USE SIGNAL ;
    PORT
      LAYER M5 ;
        RECT  129.324 0 129.348 0.192 ;
    END
  END g_front_2_u_front__q_data_in[493]
  PIN g_front_2_u_front__q_data_in[494]
    DIRECTION INPUT ;
    USE SIGNAL ;
    PORT
      LAYER M5 ;
        RECT  129.564 0 129.588 0.192 ;
    END
  END g_front_2_u_front__q_data_in[494]
  PIN g_front_2_u_front__q_data_in[495]
    DIRECTION INPUT ;
    USE SIGNAL ;
    PORT
      LAYER M5 ;
        RECT  129.804 0 129.828 0.192 ;
    END
  END g_front_2_u_front__q_data_in[495]
  PIN g_front_2_u_front__q_data_in[496]
    DIRECTION INPUT ;
    USE SIGNAL ;
    PORT
      LAYER M5 ;
        RECT  130.044 0 130.068 0.192 ;
    END
  END g_front_2_u_front__q_data_in[496]
  PIN g_front_2_u_front__q_data_in[497]
    DIRECTION INPUT ;
    USE SIGNAL ;
    PORT
      LAYER M5 ;
        RECT  130.284 0 130.308 0.192 ;
    END
  END g_front_2_u_front__q_data_in[497]
  PIN g_front_2_u_front__q_data_in[498]
    DIRECTION INPUT ;
    USE SIGNAL ;
    PORT
      LAYER M5 ;
        RECT  130.524 0 130.548 0.192 ;
    END
  END g_front_2_u_front__q_data_in[498]
  PIN g_front_2_u_front__q_data_in[499]
    DIRECTION INPUT ;
    USE SIGNAL ;
    PORT
      LAYER M5 ;
        RECT  130.764 0 130.788 0.192 ;
    END
  END g_front_2_u_front__q_data_in[499]
  PIN g_front_2_u_front__q_data_in[49]
    DIRECTION INPUT ;
    USE SIGNAL ;
    PORT
      LAYER M5 ;
        RECT  23.484 0 23.508 0.192 ;
    END
  END g_front_2_u_front__q_data_in[49]
  PIN g_front_2_u_front__q_data_in[4]
    DIRECTION INPUT ;
    USE SIGNAL ;
    PORT
      LAYER M5 ;
        RECT  12.732 0 12.756 0.192 ;
    END
  END g_front_2_u_front__q_data_in[4]
  PIN g_front_2_u_front__q_data_in[500]
    DIRECTION INPUT ;
    USE SIGNAL ;
    PORT
      LAYER M5 ;
        RECT  131.004 0 131.028 0.192 ;
    END
  END g_front_2_u_front__q_data_in[500]
  PIN g_front_2_u_front__q_data_in[501]
    DIRECTION INPUT ;
    USE SIGNAL ;
    PORT
      LAYER M5 ;
        RECT  131.244 0 131.268 0.192 ;
    END
  END g_front_2_u_front__q_data_in[501]
  PIN g_front_2_u_front__q_data_in[502]
    DIRECTION INPUT ;
    USE SIGNAL ;
    PORT
      LAYER M5 ;
        RECT  131.484 0 131.508 0.192 ;
    END
  END g_front_2_u_front__q_data_in[502]
  PIN g_front_2_u_front__q_data_in[503]
    DIRECTION INPUT ;
    USE SIGNAL ;
    PORT
      LAYER M5 ;
        RECT  131.724 0 131.748 0.192 ;
    END
  END g_front_2_u_front__q_data_in[503]
  PIN g_front_2_u_front__q_data_in[504]
    DIRECTION INPUT ;
    USE SIGNAL ;
    PORT
      LAYER M5 ;
        RECT  131.964 0 131.988 0.192 ;
    END
  END g_front_2_u_front__q_data_in[504]
  PIN g_front_2_u_front__q_data_in[505]
    DIRECTION INPUT ;
    USE SIGNAL ;
    PORT
      LAYER M5 ;
        RECT  132.204 0 132.228 0.192 ;
    END
  END g_front_2_u_front__q_data_in[505]
  PIN g_front_2_u_front__q_data_in[506]
    DIRECTION INPUT ;
    USE SIGNAL ;
    PORT
      LAYER M5 ;
        RECT  132.444 0 132.468 0.192 ;
    END
  END g_front_2_u_front__q_data_in[506]
  PIN g_front_2_u_front__q_data_in[507]
    DIRECTION INPUT ;
    USE SIGNAL ;
    PORT
      LAYER M5 ;
        RECT  132.684 0 132.708 0.192 ;
    END
  END g_front_2_u_front__q_data_in[507]
  PIN g_front_2_u_front__q_data_in[508]
    DIRECTION INPUT ;
    USE SIGNAL ;
    PORT
      LAYER M5 ;
        RECT  132.876 0 132.9 0.192 ;
    END
  END g_front_2_u_front__q_data_in[508]
  PIN g_front_2_u_front__q_data_in[509]
    DIRECTION INPUT ;
    USE SIGNAL ;
    PORT
      LAYER M5 ;
        RECT  133.116 0 133.14 0.192 ;
    END
  END g_front_2_u_front__q_data_in[509]
  PIN g_front_2_u_front__q_data_in[50]
    DIRECTION INPUT ;
    USE SIGNAL ;
    PORT
      LAYER M5 ;
        RECT  23.724 0 23.748 0.192 ;
    END
  END g_front_2_u_front__q_data_in[50]
  PIN g_front_2_u_front__q_data_in[510]
    DIRECTION INPUT ;
    USE SIGNAL ;
    PORT
      LAYER M5 ;
        RECT  133.356 0 133.38 0.192 ;
    END
  END g_front_2_u_front__q_data_in[510]
  PIN g_front_2_u_front__q_data_in[511]
    DIRECTION INPUT ;
    USE SIGNAL ;
    PORT
      LAYER M5 ;
        RECT  133.596 0 133.62 0.192 ;
    END
  END g_front_2_u_front__q_data_in[511]
  PIN g_front_2_u_front__q_data_in[51]
    DIRECTION INPUT ;
    USE SIGNAL ;
    PORT
      LAYER M5 ;
        RECT  23.964 0 23.988 0.192 ;
    END
  END g_front_2_u_front__q_data_in[51]
  PIN g_front_2_u_front__q_data_in[52]
    DIRECTION INPUT ;
    USE SIGNAL ;
    PORT
      LAYER M5 ;
        RECT  24.204 0 24.228 0.192 ;
    END
  END g_front_2_u_front__q_data_in[52]
  PIN g_front_2_u_front__q_data_in[53]
    DIRECTION INPUT ;
    USE SIGNAL ;
    PORT
      LAYER M5 ;
        RECT  24.444 0 24.468 0.192 ;
    END
  END g_front_2_u_front__q_data_in[53]
  PIN g_front_2_u_front__q_data_in[54]
    DIRECTION INPUT ;
    USE SIGNAL ;
    PORT
      LAYER M5 ;
        RECT  24.684 0 24.708 0.192 ;
    END
  END g_front_2_u_front__q_data_in[54]
  PIN g_front_2_u_front__q_data_in[55]
    DIRECTION INPUT ;
    USE SIGNAL ;
    PORT
      LAYER M5 ;
        RECT  24.924 0 24.948 0.192 ;
    END
  END g_front_2_u_front__q_data_in[55]
  PIN g_front_2_u_front__q_data_in[56]
    DIRECTION INPUT ;
    USE SIGNAL ;
    PORT
      LAYER M5 ;
        RECT  25.164 0 25.188 0.192 ;
    END
  END g_front_2_u_front__q_data_in[56]
  PIN g_front_2_u_front__q_data_in[57]
    DIRECTION INPUT ;
    USE SIGNAL ;
    PORT
      LAYER M5 ;
        RECT  25.404 0 25.428 0.192 ;
    END
  END g_front_2_u_front__q_data_in[57]
  PIN g_front_2_u_front__q_data_in[58]
    DIRECTION INPUT ;
    USE SIGNAL ;
    PORT
      LAYER M5 ;
        RECT  25.644 0 25.668 0.192 ;
    END
  END g_front_2_u_front__q_data_in[58]
  PIN g_front_2_u_front__q_data_in[59]
    DIRECTION INPUT ;
    USE SIGNAL ;
    PORT
      LAYER M5 ;
        RECT  25.884 0 25.908 0.192 ;
    END
  END g_front_2_u_front__q_data_in[59]
  PIN g_front_2_u_front__q_data_in[5]
    DIRECTION INPUT ;
    USE SIGNAL ;
    PORT
      LAYER M5 ;
        RECT  12.972 0 12.996 0.192 ;
    END
  END g_front_2_u_front__q_data_in[5]
  PIN g_front_2_u_front__q_data_in[60]
    DIRECTION INPUT ;
    USE SIGNAL ;
    PORT
      LAYER M5 ;
        RECT  26.124 0 26.148 0.192 ;
    END
  END g_front_2_u_front__q_data_in[60]
  PIN g_front_2_u_front__q_data_in[61]
    DIRECTION INPUT ;
    USE SIGNAL ;
    PORT
      LAYER M5 ;
        RECT  26.364 0 26.388 0.192 ;
    END
  END g_front_2_u_front__q_data_in[61]
  PIN g_front_2_u_front__q_data_in[62]
    DIRECTION INPUT ;
    USE SIGNAL ;
    PORT
      LAYER M5 ;
        RECT  26.604 0 26.628 0.192 ;
    END
  END g_front_2_u_front__q_data_in[62]
  PIN g_front_2_u_front__q_data_in[63]
    DIRECTION INPUT ;
    USE SIGNAL ;
    PORT
      LAYER M5 ;
        RECT  26.844 0 26.868 0.192 ;
    END
  END g_front_2_u_front__q_data_in[63]
  PIN g_front_2_u_front__q_data_in[64]
    DIRECTION INPUT ;
    USE SIGNAL ;
    PORT
      LAYER M5 ;
        RECT  27.036 0 27.06 0.192 ;
    END
  END g_front_2_u_front__q_data_in[64]
  PIN g_front_2_u_front__q_data_in[65]
    DIRECTION INPUT ;
    USE SIGNAL ;
    PORT
      LAYER M5 ;
        RECT  27.276 0 27.3 0.192 ;
    END
  END g_front_2_u_front__q_data_in[65]
  PIN g_front_2_u_front__q_data_in[66]
    DIRECTION INPUT ;
    USE SIGNAL ;
    PORT
      LAYER M5 ;
        RECT  27.516 0 27.54 0.192 ;
    END
  END g_front_2_u_front__q_data_in[66]
  PIN g_front_2_u_front__q_data_in[67]
    DIRECTION INPUT ;
    USE SIGNAL ;
    PORT
      LAYER M5 ;
        RECT  27.756 0 27.78 0.192 ;
    END
  END g_front_2_u_front__q_data_in[67]
  PIN g_front_2_u_front__q_data_in[68]
    DIRECTION INPUT ;
    USE SIGNAL ;
    PORT
      LAYER M5 ;
        RECT  27.996 0 28.02 0.192 ;
    END
  END g_front_2_u_front__q_data_in[68]
  PIN g_front_2_u_front__q_data_in[69]
    DIRECTION INPUT ;
    USE SIGNAL ;
    PORT
      LAYER M5 ;
        RECT  28.236 0 28.26 0.192 ;
    END
  END g_front_2_u_front__q_data_in[69]
  PIN g_front_2_u_front__q_data_in[6]
    DIRECTION INPUT ;
    USE SIGNAL ;
    PORT
      LAYER M5 ;
        RECT  13.212 0 13.236 0.192 ;
    END
  END g_front_2_u_front__q_data_in[6]
  PIN g_front_2_u_front__q_data_in[70]
    DIRECTION INPUT ;
    USE SIGNAL ;
    PORT
      LAYER M5 ;
        RECT  28.476 0 28.5 0.192 ;
    END
  END g_front_2_u_front__q_data_in[70]
  PIN g_front_2_u_front__q_data_in[71]
    DIRECTION INPUT ;
    USE SIGNAL ;
    PORT
      LAYER M5 ;
        RECT  28.716 0 28.74 0.192 ;
    END
  END g_front_2_u_front__q_data_in[71]
  PIN g_front_2_u_front__q_data_in[72]
    DIRECTION INPUT ;
    USE SIGNAL ;
    PORT
      LAYER M5 ;
        RECT  28.956 0 28.98 0.192 ;
    END
  END g_front_2_u_front__q_data_in[72]
  PIN g_front_2_u_front__q_data_in[73]
    DIRECTION INPUT ;
    USE SIGNAL ;
    PORT
      LAYER M5 ;
        RECT  29.196 0 29.22 0.192 ;
    END
  END g_front_2_u_front__q_data_in[73]
  PIN g_front_2_u_front__q_data_in[74]
    DIRECTION INPUT ;
    USE SIGNAL ;
    PORT
      LAYER M5 ;
        RECT  29.436 0 29.46 0.192 ;
    END
  END g_front_2_u_front__q_data_in[74]
  PIN g_front_2_u_front__q_data_in[75]
    DIRECTION INPUT ;
    USE SIGNAL ;
    PORT
      LAYER M5 ;
        RECT  29.676 0 29.7 0.192 ;
    END
  END g_front_2_u_front__q_data_in[75]
  PIN g_front_2_u_front__q_data_in[76]
    DIRECTION INPUT ;
    USE SIGNAL ;
    PORT
      LAYER M5 ;
        RECT  29.916 0 29.94 0.192 ;
    END
  END g_front_2_u_front__q_data_in[76]
  PIN g_front_2_u_front__q_data_in[77]
    DIRECTION INPUT ;
    USE SIGNAL ;
    PORT
      LAYER M5 ;
        RECT  30.156 0 30.18 0.192 ;
    END
  END g_front_2_u_front__q_data_in[77]
  PIN g_front_2_u_front__q_data_in[78]
    DIRECTION INPUT ;
    USE SIGNAL ;
    PORT
      LAYER M5 ;
        RECT  30.396 0 30.42 0.192 ;
    END
  END g_front_2_u_front__q_data_in[78]
  PIN g_front_2_u_front__q_data_in[79]
    DIRECTION INPUT ;
    USE SIGNAL ;
    PORT
      LAYER M5 ;
        RECT  30.636 0 30.66 0.192 ;
    END
  END g_front_2_u_front__q_data_in[79]
  PIN g_front_2_u_front__q_data_in[7]
    DIRECTION INPUT ;
    USE SIGNAL ;
    PORT
      LAYER M5 ;
        RECT  13.452 0 13.476 0.192 ;
    END
  END g_front_2_u_front__q_data_in[7]
  PIN g_front_2_u_front__q_data_in[80]
    DIRECTION INPUT ;
    USE SIGNAL ;
    PORT
      LAYER M5 ;
        RECT  30.876 0 30.9 0.192 ;
    END
  END g_front_2_u_front__q_data_in[80]
  PIN g_front_2_u_front__q_data_in[81]
    DIRECTION INPUT ;
    USE SIGNAL ;
    PORT
      LAYER M5 ;
        RECT  31.116 0 31.14 0.192 ;
    END
  END g_front_2_u_front__q_data_in[81]
  PIN g_front_2_u_front__q_data_in[82]
    DIRECTION INPUT ;
    USE SIGNAL ;
    PORT
      LAYER M5 ;
        RECT  31.356 0 31.38 0.192 ;
    END
  END g_front_2_u_front__q_data_in[82]
  PIN g_front_2_u_front__q_data_in[83]
    DIRECTION INPUT ;
    USE SIGNAL ;
    PORT
      LAYER M5 ;
        RECT  31.596 0 31.62 0.192 ;
    END
  END g_front_2_u_front__q_data_in[83]
  PIN g_front_2_u_front__q_data_in[84]
    DIRECTION INPUT ;
    USE SIGNAL ;
    PORT
      LAYER M5 ;
        RECT  31.836 0 31.86 0.192 ;
    END
  END g_front_2_u_front__q_data_in[84]
  PIN g_front_2_u_front__q_data_in[85]
    DIRECTION INPUT ;
    USE SIGNAL ;
    PORT
      LAYER M5 ;
        RECT  32.076 0 32.1 0.192 ;
    END
  END g_front_2_u_front__q_data_in[85]
  PIN g_front_2_u_front__q_data_in[86]
    DIRECTION INPUT ;
    USE SIGNAL ;
    PORT
      LAYER M5 ;
        RECT  32.316 0 32.34 0.192 ;
    END
  END g_front_2_u_front__q_data_in[86]
  PIN g_front_2_u_front__q_data_in[87]
    DIRECTION INPUT ;
    USE SIGNAL ;
    PORT
      LAYER M5 ;
        RECT  32.556 0 32.58 0.192 ;
    END
  END g_front_2_u_front__q_data_in[87]
  PIN g_front_2_u_front__q_data_in[88]
    DIRECTION INPUT ;
    USE SIGNAL ;
    PORT
      LAYER M5 ;
        RECT  32.796 0 32.82 0.192 ;
    END
  END g_front_2_u_front__q_data_in[88]
  PIN g_front_2_u_front__q_data_in[89]
    DIRECTION INPUT ;
    USE SIGNAL ;
    PORT
      LAYER M5 ;
        RECT  33.036 0 33.06 0.192 ;
    END
  END g_front_2_u_front__q_data_in[89]
  PIN g_front_2_u_front__q_data_in[8]
    DIRECTION INPUT ;
    USE SIGNAL ;
    PORT
      LAYER M5 ;
        RECT  13.692 0 13.716 0.192 ;
    END
  END g_front_2_u_front__q_data_in[8]
  PIN g_front_2_u_front__q_data_in[90]
    DIRECTION INPUT ;
    USE SIGNAL ;
    PORT
      LAYER M5 ;
        RECT  33.276 0 33.3 0.192 ;
    END
  END g_front_2_u_front__q_data_in[90]
  PIN g_front_2_u_front__q_data_in[91]
    DIRECTION INPUT ;
    USE SIGNAL ;
    PORT
      LAYER M5 ;
        RECT  33.516 0 33.54 0.192 ;
    END
  END g_front_2_u_front__q_data_in[91]
  PIN g_front_2_u_front__q_data_in[92]
    DIRECTION INPUT ;
    USE SIGNAL ;
    PORT
      LAYER M5 ;
        RECT  33.756 0 33.78 0.192 ;
    END
  END g_front_2_u_front__q_data_in[92]
  PIN g_front_2_u_front__q_data_in[93]
    DIRECTION INPUT ;
    USE SIGNAL ;
    PORT
      LAYER M5 ;
        RECT  33.948 0 33.972 0.192 ;
    END
  END g_front_2_u_front__q_data_in[93]
  PIN g_front_2_u_front__q_data_in[94]
    DIRECTION INPUT ;
    USE SIGNAL ;
    PORT
      LAYER M5 ;
        RECT  34.188 0 34.212 0.192 ;
    END
  END g_front_2_u_front__q_data_in[94]
  PIN g_front_2_u_front__q_data_in[95]
    DIRECTION INPUT ;
    USE SIGNAL ;
    PORT
      LAYER M5 ;
        RECT  34.428 0 34.452 0.192 ;
    END
  END g_front_2_u_front__q_data_in[95]
  PIN g_front_2_u_front__q_data_in[96]
    DIRECTION INPUT ;
    USE SIGNAL ;
    PORT
      LAYER M5 ;
        RECT  34.668 0 34.692 0.192 ;
    END
  END g_front_2_u_front__q_data_in[96]
  PIN g_front_2_u_front__q_data_in[97]
    DIRECTION INPUT ;
    USE SIGNAL ;
    PORT
      LAYER M5 ;
        RECT  34.908 0 34.932 0.192 ;
    END
  END g_front_2_u_front__q_data_in[97]
  PIN g_front_2_u_front__q_data_in[98]
    DIRECTION INPUT ;
    USE SIGNAL ;
    PORT
      LAYER M5 ;
        RECT  35.148 0 35.172 0.192 ;
    END
  END g_front_2_u_front__q_data_in[98]
  PIN g_front_2_u_front__q_data_in[99]
    DIRECTION INPUT ;
    USE SIGNAL ;
    PORT
      LAYER M5 ;
        RECT  35.388 0 35.412 0.192 ;
    END
  END g_front_2_u_front__q_data_in[99]
  PIN g_front_2_u_front__q_data_in[9]
    DIRECTION INPUT ;
    USE SIGNAL ;
    PORT
      LAYER M5 ;
        RECT  13.932 0 13.956 0.192 ;
    END
  END g_front_2_u_front__q_data_in[9]
  PIN g_front_2_u_front__q_valid_in[0]
    DIRECTION INPUT ;
    USE SIGNAL ;
    PORT
      LAYER M5 ;
        RECT  133.836 0 133.86 0.192 ;
    END
  END g_front_2_u_front__q_valid_in[0]
  PIN g_front_2_u_front__row_in[0]
    DIRECTION INPUT ;
    USE SIGNAL ;
    PORT
      LAYER M5 ;
        RECT  134.076 0 134.1 0.192 ;
    END
  END g_front_2_u_front__row_in[0]
  PIN g_front_2_u_front__row_in[100]
    DIRECTION INPUT ;
    USE SIGNAL ;
    PORT
      LAYER M5 ;
        RECT  157.932 0 157.956 0.192 ;
    END
  END g_front_2_u_front__row_in[100]
  PIN g_front_2_u_front__row_in[101]
    DIRECTION INPUT ;
    USE SIGNAL ;
    PORT
      LAYER M5 ;
        RECT  158.172 0 158.196 0.192 ;
    END
  END g_front_2_u_front__row_in[101]
  PIN g_front_2_u_front__row_in[102]
    DIRECTION INPUT ;
    USE SIGNAL ;
    PORT
      LAYER M5 ;
        RECT  158.412 0 158.436 0.192 ;
    END
  END g_front_2_u_front__row_in[102]
  PIN g_front_2_u_front__row_in[103]
    DIRECTION INPUT ;
    USE SIGNAL ;
    PORT
      LAYER M5 ;
        RECT  158.652 0 158.676 0.192 ;
    END
  END g_front_2_u_front__row_in[103]
  PIN g_front_2_u_front__row_in[104]
    DIRECTION INPUT ;
    USE SIGNAL ;
    PORT
      LAYER M5 ;
        RECT  158.892 0 158.916 0.192 ;
    END
  END g_front_2_u_front__row_in[104]
  PIN g_front_2_u_front__row_in[105]
    DIRECTION INPUT ;
    USE SIGNAL ;
    PORT
      LAYER M5 ;
        RECT  159.132 0 159.156 0.192 ;
    END
  END g_front_2_u_front__row_in[105]
  PIN g_front_2_u_front__row_in[106]
    DIRECTION INPUT ;
    USE SIGNAL ;
    PORT
      LAYER M5 ;
        RECT  159.372 0 159.396 0.192 ;
    END
  END g_front_2_u_front__row_in[106]
  PIN g_front_2_u_front__row_in[107]
    DIRECTION INPUT ;
    USE SIGNAL ;
    PORT
      LAYER M5 ;
        RECT  159.612 0 159.636 0.192 ;
    END
  END g_front_2_u_front__row_in[107]
  PIN g_front_2_u_front__row_in[108]
    DIRECTION INPUT ;
    USE SIGNAL ;
    PORT
      LAYER M5 ;
        RECT  159.852 0 159.876 0.192 ;
    END
  END g_front_2_u_front__row_in[108]
  PIN g_front_2_u_front__row_in[109]
    DIRECTION INPUT ;
    USE SIGNAL ;
    PORT
      LAYER M5 ;
        RECT  160.092 0 160.116 0.192 ;
    END
  END g_front_2_u_front__row_in[109]
  PIN g_front_2_u_front__row_in[10]
    DIRECTION INPUT ;
    USE SIGNAL ;
    PORT
      LAYER M5 ;
        RECT  136.476 0 136.5 0.192 ;
    END
  END g_front_2_u_front__row_in[10]
  PIN g_front_2_u_front__row_in[110]
    DIRECTION INPUT ;
    USE SIGNAL ;
    PORT
      LAYER M5 ;
        RECT  160.332 0 160.356 0.192 ;
    END
  END g_front_2_u_front__row_in[110]
  PIN g_front_2_u_front__row_in[111]
    DIRECTION INPUT ;
    USE SIGNAL ;
    PORT
      LAYER M5 ;
        RECT  160.572 0 160.596 0.192 ;
    END
  END g_front_2_u_front__row_in[111]
  PIN g_front_2_u_front__row_in[112]
    DIRECTION INPUT ;
    USE SIGNAL ;
    PORT
      LAYER M5 ;
        RECT  160.812 0 160.836 0.192 ;
    END
  END g_front_2_u_front__row_in[112]
  PIN g_front_2_u_front__row_in[113]
    DIRECTION INPUT ;
    USE SIGNAL ;
    PORT
      LAYER M5 ;
        RECT  161.004 0 161.028 0.192 ;
    END
  END g_front_2_u_front__row_in[113]
  PIN g_front_2_u_front__row_in[114]
    DIRECTION INPUT ;
    USE SIGNAL ;
    PORT
      LAYER M5 ;
        RECT  161.244 0 161.268 0.192 ;
    END
  END g_front_2_u_front__row_in[114]
  PIN g_front_2_u_front__row_in[115]
    DIRECTION INPUT ;
    USE SIGNAL ;
    PORT
      LAYER M5 ;
        RECT  161.484 0 161.508 0.192 ;
    END
  END g_front_2_u_front__row_in[115]
  PIN g_front_2_u_front__row_in[116]
    DIRECTION INPUT ;
    USE SIGNAL ;
    PORT
      LAYER M5 ;
        RECT  161.724 0 161.748 0.192 ;
    END
  END g_front_2_u_front__row_in[116]
  PIN g_front_2_u_front__row_in[117]
    DIRECTION INPUT ;
    USE SIGNAL ;
    PORT
      LAYER M5 ;
        RECT  161.964 0 161.988 0.192 ;
    END
  END g_front_2_u_front__row_in[117]
  PIN g_front_2_u_front__row_in[118]
    DIRECTION INPUT ;
    USE SIGNAL ;
    PORT
      LAYER M5 ;
        RECT  162.204 0 162.228 0.192 ;
    END
  END g_front_2_u_front__row_in[118]
  PIN g_front_2_u_front__row_in[119]
    DIRECTION INPUT ;
    USE SIGNAL ;
    PORT
      LAYER M5 ;
        RECT  162.444 0 162.468 0.192 ;
    END
  END g_front_2_u_front__row_in[119]
  PIN g_front_2_u_front__row_in[11]
    DIRECTION INPUT ;
    USE SIGNAL ;
    PORT
      LAYER M5 ;
        RECT  136.716 0 136.74 0.192 ;
    END
  END g_front_2_u_front__row_in[11]
  PIN g_front_2_u_front__row_in[120]
    DIRECTION INPUT ;
    USE SIGNAL ;
    PORT
      LAYER M5 ;
        RECT  162.684 0 162.708 0.192 ;
    END
  END g_front_2_u_front__row_in[120]
  PIN g_front_2_u_front__row_in[121]
    DIRECTION INPUT ;
    USE SIGNAL ;
    PORT
      LAYER M5 ;
        RECT  162.924 0 162.948 0.192 ;
    END
  END g_front_2_u_front__row_in[121]
  PIN g_front_2_u_front__row_in[122]
    DIRECTION INPUT ;
    USE SIGNAL ;
    PORT
      LAYER M5 ;
        RECT  163.164 0 163.188 0.192 ;
    END
  END g_front_2_u_front__row_in[122]
  PIN g_front_2_u_front__row_in[123]
    DIRECTION INPUT ;
    USE SIGNAL ;
    PORT
      LAYER M5 ;
        RECT  163.404 0 163.428 0.192 ;
    END
  END g_front_2_u_front__row_in[123]
  PIN g_front_2_u_front__row_in[124]
    DIRECTION INPUT ;
    USE SIGNAL ;
    PORT
      LAYER M5 ;
        RECT  163.644 0 163.668 0.192 ;
    END
  END g_front_2_u_front__row_in[124]
  PIN g_front_2_u_front__row_in[125]
    DIRECTION INPUT ;
    USE SIGNAL ;
    PORT
      LAYER M5 ;
        RECT  163.884 0 163.908 0.192 ;
    END
  END g_front_2_u_front__row_in[125]
  PIN g_front_2_u_front__row_in[126]
    DIRECTION INPUT ;
    USE SIGNAL ;
    PORT
      LAYER M5 ;
        RECT  164.124 0 164.148 0.192 ;
    END
  END g_front_2_u_front__row_in[126]
  PIN g_front_2_u_front__row_in[127]
    DIRECTION INPUT ;
    USE SIGNAL ;
    PORT
      LAYER M5 ;
        RECT  164.364 0 164.388 0.192 ;
    END
  END g_front_2_u_front__row_in[127]
  PIN g_front_2_u_front__row_in[128]
    DIRECTION INPUT ;
    USE SIGNAL ;
    PORT
      LAYER M5 ;
        RECT  164.604 0 164.628 0.192 ;
    END
  END g_front_2_u_front__row_in[128]
  PIN g_front_2_u_front__row_in[129]
    DIRECTION INPUT ;
    USE SIGNAL ;
    PORT
      LAYER M5 ;
        RECT  164.844 0 164.868 0.192 ;
    END
  END g_front_2_u_front__row_in[129]
  PIN g_front_2_u_front__row_in[12]
    DIRECTION INPUT ;
    USE SIGNAL ;
    PORT
      LAYER M5 ;
        RECT  136.956 0 136.98 0.192 ;
    END
  END g_front_2_u_front__row_in[12]
  PIN g_front_2_u_front__row_in[130]
    DIRECTION INPUT ;
    USE SIGNAL ;
    PORT
      LAYER M5 ;
        RECT  165.084 0 165.108 0.192 ;
    END
  END g_front_2_u_front__row_in[130]
  PIN g_front_2_u_front__row_in[131]
    DIRECTION INPUT ;
    USE SIGNAL ;
    PORT
      LAYER M5 ;
        RECT  165.324 0 165.348 0.192 ;
    END
  END g_front_2_u_front__row_in[131]
  PIN g_front_2_u_front__row_in[132]
    DIRECTION INPUT ;
    USE SIGNAL ;
    PORT
      LAYER M5 ;
        RECT  165.564 0 165.588 0.192 ;
    END
  END g_front_2_u_front__row_in[132]
  PIN g_front_2_u_front__row_in[133]
    DIRECTION INPUT ;
    USE SIGNAL ;
    PORT
      LAYER M5 ;
        RECT  165.804 0 165.828 0.192 ;
    END
  END g_front_2_u_front__row_in[133]
  PIN g_front_2_u_front__row_in[134]
    DIRECTION INPUT ;
    USE SIGNAL ;
    PORT
      LAYER M5 ;
        RECT  166.044 0 166.068 0.192 ;
    END
  END g_front_2_u_front__row_in[134]
  PIN g_front_2_u_front__row_in[135]
    DIRECTION INPUT ;
    USE SIGNAL ;
    PORT
      LAYER M5 ;
        RECT  166.284 0 166.308 0.192 ;
    END
  END g_front_2_u_front__row_in[135]
  PIN g_front_2_u_front__row_in[136]
    DIRECTION INPUT ;
    USE SIGNAL ;
    PORT
      LAYER M5 ;
        RECT  166.524 0 166.548 0.192 ;
    END
  END g_front_2_u_front__row_in[136]
  PIN g_front_2_u_front__row_in[137]
    DIRECTION INPUT ;
    USE SIGNAL ;
    PORT
      LAYER M5 ;
        RECT  166.764 0 166.788 0.192 ;
    END
  END g_front_2_u_front__row_in[137]
  PIN g_front_2_u_front__row_in[138]
    DIRECTION INPUT ;
    USE SIGNAL ;
    PORT
      LAYER M5 ;
        RECT  167.004 0 167.028 0.192 ;
    END
  END g_front_2_u_front__row_in[138]
  PIN g_front_2_u_front__row_in[139]
    DIRECTION INPUT ;
    USE SIGNAL ;
    PORT
      LAYER M5 ;
        RECT  167.244 0 167.268 0.192 ;
    END
  END g_front_2_u_front__row_in[139]
  PIN g_front_2_u_front__row_in[13]
    DIRECTION INPUT ;
    USE SIGNAL ;
    PORT
      LAYER M5 ;
        RECT  137.196 0 137.22 0.192 ;
    END
  END g_front_2_u_front__row_in[13]
  PIN g_front_2_u_front__row_in[140]
    DIRECTION INPUT ;
    USE SIGNAL ;
    PORT
      LAYER M5 ;
        RECT  167.484 0 167.508 0.192 ;
    END
  END g_front_2_u_front__row_in[140]
  PIN g_front_2_u_front__row_in[141]
    DIRECTION INPUT ;
    USE SIGNAL ;
    PORT
      LAYER M5 ;
        RECT  167.724 0 167.748 0.192 ;
    END
  END g_front_2_u_front__row_in[141]
  PIN g_front_2_u_front__row_in[142]
    DIRECTION INPUT ;
    USE SIGNAL ;
    PORT
      LAYER M5 ;
        RECT  167.964 0 167.988 0.192 ;
    END
  END g_front_2_u_front__row_in[142]
  PIN g_front_2_u_front__row_in[143]
    DIRECTION INPUT ;
    USE SIGNAL ;
    PORT
      LAYER M5 ;
        RECT  168.156 0 168.18 0.192 ;
    END
  END g_front_2_u_front__row_in[143]
  PIN g_front_2_u_front__row_in[144]
    DIRECTION INPUT ;
    USE SIGNAL ;
    PORT
      LAYER M5 ;
        RECT  168.396 0 168.42 0.192 ;
    END
  END g_front_2_u_front__row_in[144]
  PIN g_front_2_u_front__row_in[145]
    DIRECTION INPUT ;
    USE SIGNAL ;
    PORT
      LAYER M5 ;
        RECT  168.636 0 168.66 0.192 ;
    END
  END g_front_2_u_front__row_in[145]
  PIN g_front_2_u_front__row_in[146]
    DIRECTION INPUT ;
    USE SIGNAL ;
    PORT
      LAYER M5 ;
        RECT  168.876 0 168.9 0.192 ;
    END
  END g_front_2_u_front__row_in[146]
  PIN g_front_2_u_front__row_in[147]
    DIRECTION INPUT ;
    USE SIGNAL ;
    PORT
      LAYER M5 ;
        RECT  169.116 0 169.14 0.192 ;
    END
  END g_front_2_u_front__row_in[147]
  PIN g_front_2_u_front__row_in[148]
    DIRECTION INPUT ;
    USE SIGNAL ;
    PORT
      LAYER M5 ;
        RECT  169.356 0 169.38 0.192 ;
    END
  END g_front_2_u_front__row_in[148]
  PIN g_front_2_u_front__row_in[149]
    DIRECTION INPUT ;
    USE SIGNAL ;
    PORT
      LAYER M5 ;
        RECT  169.596 0 169.62 0.192 ;
    END
  END g_front_2_u_front__row_in[149]
  PIN g_front_2_u_front__row_in[14]
    DIRECTION INPUT ;
    USE SIGNAL ;
    PORT
      LAYER M5 ;
        RECT  137.436 0 137.46 0.192 ;
    END
  END g_front_2_u_front__row_in[14]
  PIN g_front_2_u_front__row_in[150]
    DIRECTION INPUT ;
    USE SIGNAL ;
    PORT
      LAYER M5 ;
        RECT  169.836 0 169.86 0.192 ;
    END
  END g_front_2_u_front__row_in[150]
  PIN g_front_2_u_front__row_in[151]
    DIRECTION INPUT ;
    USE SIGNAL ;
    PORT
      LAYER M5 ;
        RECT  170.076 0 170.1 0.192 ;
    END
  END g_front_2_u_front__row_in[151]
  PIN g_front_2_u_front__row_in[152]
    DIRECTION INPUT ;
    USE SIGNAL ;
    PORT
      LAYER M5 ;
        RECT  170.316 0 170.34 0.192 ;
    END
  END g_front_2_u_front__row_in[152]
  PIN g_front_2_u_front__row_in[153]
    DIRECTION INPUT ;
    USE SIGNAL ;
    PORT
      LAYER M5 ;
        RECT  170.556 0 170.58 0.192 ;
    END
  END g_front_2_u_front__row_in[153]
  PIN g_front_2_u_front__row_in[154]
    DIRECTION INPUT ;
    USE SIGNAL ;
    PORT
      LAYER M5 ;
        RECT  170.796 0 170.82 0.192 ;
    END
  END g_front_2_u_front__row_in[154]
  PIN g_front_2_u_front__row_in[155]
    DIRECTION INPUT ;
    USE SIGNAL ;
    PORT
      LAYER M5 ;
        RECT  171.036 0 171.06 0.192 ;
    END
  END g_front_2_u_front__row_in[155]
  PIN g_front_2_u_front__row_in[156]
    DIRECTION INPUT ;
    USE SIGNAL ;
    PORT
      LAYER M5 ;
        RECT  171.276 0 171.3 0.192 ;
    END
  END g_front_2_u_front__row_in[156]
  PIN g_front_2_u_front__row_in[157]
    DIRECTION INPUT ;
    USE SIGNAL ;
    PORT
      LAYER M5 ;
        RECT  171.516 0 171.54 0.192 ;
    END
  END g_front_2_u_front__row_in[157]
  PIN g_front_2_u_front__row_in[158]
    DIRECTION INPUT ;
    USE SIGNAL ;
    PORT
      LAYER M5 ;
        RECT  171.756 0 171.78 0.192 ;
    END
  END g_front_2_u_front__row_in[158]
  PIN g_front_2_u_front__row_in[159]
    DIRECTION INPUT ;
    USE SIGNAL ;
    PORT
      LAYER M5 ;
        RECT  171.996 0 172.02 0.192 ;
    END
  END g_front_2_u_front__row_in[159]
  PIN g_front_2_u_front__row_in[15]
    DIRECTION INPUT ;
    USE SIGNAL ;
    PORT
      LAYER M5 ;
        RECT  137.676 0 137.7 0.192 ;
    END
  END g_front_2_u_front__row_in[15]
  PIN g_front_2_u_front__row_in[160]
    DIRECTION INPUT ;
    USE SIGNAL ;
    PORT
      LAYER M5 ;
        RECT  172.236 0 172.26 0.192 ;
    END
  END g_front_2_u_front__row_in[160]
  PIN g_front_2_u_front__row_in[161]
    DIRECTION INPUT ;
    USE SIGNAL ;
    PORT
      LAYER M5 ;
        RECT  172.476 0 172.5 0.192 ;
    END
  END g_front_2_u_front__row_in[161]
  PIN g_front_2_u_front__row_in[162]
    DIRECTION INPUT ;
    USE SIGNAL ;
    PORT
      LAYER M5 ;
        RECT  172.716 0 172.74 0.192 ;
    END
  END g_front_2_u_front__row_in[162]
  PIN g_front_2_u_front__row_in[163]
    DIRECTION INPUT ;
    USE SIGNAL ;
    PORT
      LAYER M5 ;
        RECT  172.956 0 172.98 0.192 ;
    END
  END g_front_2_u_front__row_in[163]
  PIN g_front_2_u_front__row_in[164]
    DIRECTION INPUT ;
    USE SIGNAL ;
    PORT
      LAYER M5 ;
        RECT  173.196 0 173.22 0.192 ;
    END
  END g_front_2_u_front__row_in[164]
  PIN g_front_2_u_front__row_in[165]
    DIRECTION INPUT ;
    USE SIGNAL ;
    PORT
      LAYER M5 ;
        RECT  173.436 0 173.46 0.192 ;
    END
  END g_front_2_u_front__row_in[165]
  PIN g_front_2_u_front__row_in[166]
    DIRECTION INPUT ;
    USE SIGNAL ;
    PORT
      LAYER M5 ;
        RECT  173.676 0 173.7 0.192 ;
    END
  END g_front_2_u_front__row_in[166]
  PIN g_front_2_u_front__row_in[167]
    DIRECTION INPUT ;
    USE SIGNAL ;
    PORT
      LAYER M5 ;
        RECT  173.916 0 173.94 0.192 ;
    END
  END g_front_2_u_front__row_in[167]
  PIN g_front_2_u_front__row_in[168]
    DIRECTION INPUT ;
    USE SIGNAL ;
    PORT
      LAYER M5 ;
        RECT  174.156 0 174.18 0.192 ;
    END
  END g_front_2_u_front__row_in[168]
  PIN g_front_2_u_front__row_in[169]
    DIRECTION INPUT ;
    USE SIGNAL ;
    PORT
      LAYER M5 ;
        RECT  174.396 0 174.42 0.192 ;
    END
  END g_front_2_u_front__row_in[169]
  PIN g_front_2_u_front__row_in[16]
    DIRECTION INPUT ;
    USE SIGNAL ;
    PORT
      LAYER M5 ;
        RECT  137.916 0 137.94 0.192 ;
    END
  END g_front_2_u_front__row_in[16]
  PIN g_front_2_u_front__row_in[170]
    DIRECTION INPUT ;
    USE SIGNAL ;
    PORT
      LAYER M5 ;
        RECT  174.636 0 174.66 0.192 ;
    END
  END g_front_2_u_front__row_in[170]
  PIN g_front_2_u_front__row_in[171]
    DIRECTION INPUT ;
    USE SIGNAL ;
    PORT
      LAYER M5 ;
        RECT  174.876 0 174.9 0.192 ;
    END
  END g_front_2_u_front__row_in[171]
  PIN g_front_2_u_front__row_in[172]
    DIRECTION INPUT ;
    USE SIGNAL ;
    PORT
      LAYER M5 ;
        RECT  175.068 0 175.092 0.192 ;
    END
  END g_front_2_u_front__row_in[172]
  PIN g_front_2_u_front__row_in[173]
    DIRECTION INPUT ;
    USE SIGNAL ;
    PORT
      LAYER M5 ;
        RECT  175.308 0 175.332 0.192 ;
    END
  END g_front_2_u_front__row_in[173]
  PIN g_front_2_u_front__row_in[174]
    DIRECTION INPUT ;
    USE SIGNAL ;
    PORT
      LAYER M5 ;
        RECT  175.548 0 175.572 0.192 ;
    END
  END g_front_2_u_front__row_in[174]
  PIN g_front_2_u_front__row_in[175]
    DIRECTION INPUT ;
    USE SIGNAL ;
    PORT
      LAYER M5 ;
        RECT  175.788 0 175.812 0.192 ;
    END
  END g_front_2_u_front__row_in[175]
  PIN g_front_2_u_front__row_in[176]
    DIRECTION INPUT ;
    USE SIGNAL ;
    PORT
      LAYER M5 ;
        RECT  176.028 0 176.052 0.192 ;
    END
  END g_front_2_u_front__row_in[176]
  PIN g_front_2_u_front__row_in[177]
    DIRECTION INPUT ;
    USE SIGNAL ;
    PORT
      LAYER M5 ;
        RECT  176.268 0 176.292 0.192 ;
    END
  END g_front_2_u_front__row_in[177]
  PIN g_front_2_u_front__row_in[178]
    DIRECTION INPUT ;
    USE SIGNAL ;
    PORT
      LAYER M5 ;
        RECT  176.508 0 176.532 0.192 ;
    END
  END g_front_2_u_front__row_in[178]
  PIN g_front_2_u_front__row_in[179]
    DIRECTION INPUT ;
    USE SIGNAL ;
    PORT
      LAYER M5 ;
        RECT  176.748 0 176.772 0.192 ;
    END
  END g_front_2_u_front__row_in[179]
  PIN g_front_2_u_front__row_in[17]
    DIRECTION INPUT ;
    USE SIGNAL ;
    PORT
      LAYER M5 ;
        RECT  138.156 0 138.18 0.192 ;
    END
  END g_front_2_u_front__row_in[17]
  PIN g_front_2_u_front__row_in[180]
    DIRECTION INPUT ;
    USE SIGNAL ;
    PORT
      LAYER M5 ;
        RECT  176.988 0 177.012 0.192 ;
    END
  END g_front_2_u_front__row_in[180]
  PIN g_front_2_u_front__row_in[181]
    DIRECTION INPUT ;
    USE SIGNAL ;
    PORT
      LAYER M5 ;
        RECT  177.228 0 177.252 0.192 ;
    END
  END g_front_2_u_front__row_in[181]
  PIN g_front_2_u_front__row_in[182]
    DIRECTION INPUT ;
    USE SIGNAL ;
    PORT
      LAYER M5 ;
        RECT  177.468 0 177.492 0.192 ;
    END
  END g_front_2_u_front__row_in[182]
  PIN g_front_2_u_front__row_in[183]
    DIRECTION INPUT ;
    USE SIGNAL ;
    PORT
      LAYER M5 ;
        RECT  177.708 0 177.732 0.192 ;
    END
  END g_front_2_u_front__row_in[183]
  PIN g_front_2_u_front__row_in[184]
    DIRECTION INPUT ;
    USE SIGNAL ;
    PORT
      LAYER M5 ;
        RECT  177.948 0 177.972 0.192 ;
    END
  END g_front_2_u_front__row_in[184]
  PIN g_front_2_u_front__row_in[185]
    DIRECTION INPUT ;
    USE SIGNAL ;
    PORT
      LAYER M5 ;
        RECT  178.188 0 178.212 0.192 ;
    END
  END g_front_2_u_front__row_in[185]
  PIN g_front_2_u_front__row_in[186]
    DIRECTION INPUT ;
    USE SIGNAL ;
    PORT
      LAYER M5 ;
        RECT  178.428 0 178.452 0.192 ;
    END
  END g_front_2_u_front__row_in[186]
  PIN g_front_2_u_front__row_in[187]
    DIRECTION INPUT ;
    USE SIGNAL ;
    PORT
      LAYER M5 ;
        RECT  178.668 0 178.692 0.192 ;
    END
  END g_front_2_u_front__row_in[187]
  PIN g_front_2_u_front__row_in[188]
    DIRECTION INPUT ;
    USE SIGNAL ;
    PORT
      LAYER M5 ;
        RECT  178.908 0 178.932 0.192 ;
    END
  END g_front_2_u_front__row_in[188]
  PIN g_front_2_u_front__row_in[189]
    DIRECTION INPUT ;
    USE SIGNAL ;
    PORT
      LAYER M5 ;
        RECT  179.148 0 179.172 0.192 ;
    END
  END g_front_2_u_front__row_in[189]
  PIN g_front_2_u_front__row_in[18]
    DIRECTION INPUT ;
    USE SIGNAL ;
    PORT
      LAYER M5 ;
        RECT  138.396 0 138.42 0.192 ;
    END
  END g_front_2_u_front__row_in[18]
  PIN g_front_2_u_front__row_in[190]
    DIRECTION INPUT ;
    USE SIGNAL ;
    PORT
      LAYER M5 ;
        RECT  179.388 0 179.412 0.192 ;
    END
  END g_front_2_u_front__row_in[190]
  PIN g_front_2_u_front__row_in[191]
    DIRECTION INPUT ;
    USE SIGNAL ;
    PORT
      LAYER M5 ;
        RECT  179.628 0 179.652 0.192 ;
    END
  END g_front_2_u_front__row_in[191]
  PIN g_front_2_u_front__row_in[192]
    DIRECTION INPUT ;
    USE SIGNAL ;
    PORT
      LAYER M5 ;
        RECT  179.868 0 179.892 0.192 ;
    END
  END g_front_2_u_front__row_in[192]
  PIN g_front_2_u_front__row_in[193]
    DIRECTION INPUT ;
    USE SIGNAL ;
    PORT
      LAYER M5 ;
        RECT  180.108 0 180.132 0.192 ;
    END
  END g_front_2_u_front__row_in[193]
  PIN g_front_2_u_front__row_in[194]
    DIRECTION INPUT ;
    USE SIGNAL ;
    PORT
      LAYER M5 ;
        RECT  180.348 0 180.372 0.192 ;
    END
  END g_front_2_u_front__row_in[194]
  PIN g_front_2_u_front__row_in[195]
    DIRECTION INPUT ;
    USE SIGNAL ;
    PORT
      LAYER M5 ;
        RECT  180.588 0 180.612 0.192 ;
    END
  END g_front_2_u_front__row_in[195]
  PIN g_front_2_u_front__row_in[196]
    DIRECTION INPUT ;
    USE SIGNAL ;
    PORT
      LAYER M5 ;
        RECT  180.828 0 180.852 0.192 ;
    END
  END g_front_2_u_front__row_in[196]
  PIN g_front_2_u_front__row_in[197]
    DIRECTION INPUT ;
    USE SIGNAL ;
    PORT
      LAYER M5 ;
        RECT  181.068 0 181.092 0.192 ;
    END
  END g_front_2_u_front__row_in[197]
  PIN g_front_2_u_front__row_in[198]
    DIRECTION INPUT ;
    USE SIGNAL ;
    PORT
      LAYER M5 ;
        RECT  181.308 0 181.332 0.192 ;
    END
  END g_front_2_u_front__row_in[198]
  PIN g_front_2_u_front__row_in[199]
    DIRECTION INPUT ;
    USE SIGNAL ;
    PORT
      LAYER M5 ;
        RECT  181.548 0 181.572 0.192 ;
    END
  END g_front_2_u_front__row_in[199]
  PIN g_front_2_u_front__row_in[19]
    DIRECTION INPUT ;
    USE SIGNAL ;
    PORT
      LAYER M5 ;
        RECT  138.636 0 138.66 0.192 ;
    END
  END g_front_2_u_front__row_in[19]
  PIN g_front_2_u_front__row_in[1]
    DIRECTION INPUT ;
    USE SIGNAL ;
    PORT
      LAYER M5 ;
        RECT  134.316 0 134.34 0.192 ;
    END
  END g_front_2_u_front__row_in[1]
  PIN g_front_2_u_front__row_in[200]
    DIRECTION INPUT ;
    USE SIGNAL ;
    PORT
      LAYER M5 ;
        RECT  181.788 0 181.812 0.192 ;
    END
  END g_front_2_u_front__row_in[200]
  PIN g_front_2_u_front__row_in[201]
    DIRECTION INPUT ;
    USE SIGNAL ;
    PORT
      LAYER M5 ;
        RECT  182.028 0 182.052 0.192 ;
    END
  END g_front_2_u_front__row_in[201]
  PIN g_front_2_u_front__row_in[202]
    DIRECTION INPUT ;
    USE SIGNAL ;
    PORT
      LAYER M5 ;
        RECT  182.22 0 182.244 0.192 ;
    END
  END g_front_2_u_front__row_in[202]
  PIN g_front_2_u_front__row_in[203]
    DIRECTION INPUT ;
    USE SIGNAL ;
    PORT
      LAYER M5 ;
        RECT  182.46 0 182.484 0.192 ;
    END
  END g_front_2_u_front__row_in[203]
  PIN g_front_2_u_front__row_in[204]
    DIRECTION INPUT ;
    USE SIGNAL ;
    PORT
      LAYER M5 ;
        RECT  182.7 0 182.724 0.192 ;
    END
  END g_front_2_u_front__row_in[204]
  PIN g_front_2_u_front__row_in[205]
    DIRECTION INPUT ;
    USE SIGNAL ;
    PORT
      LAYER M5 ;
        RECT  182.94 0 182.964 0.192 ;
    END
  END g_front_2_u_front__row_in[205]
  PIN g_front_2_u_front__row_in[206]
    DIRECTION INPUT ;
    USE SIGNAL ;
    PORT
      LAYER M5 ;
        RECT  183.18 0 183.204 0.192 ;
    END
  END g_front_2_u_front__row_in[206]
  PIN g_front_2_u_front__row_in[207]
    DIRECTION INPUT ;
    USE SIGNAL ;
    PORT
      LAYER M5 ;
        RECT  183.42 0 183.444 0.192 ;
    END
  END g_front_2_u_front__row_in[207]
  PIN g_front_2_u_front__row_in[208]
    DIRECTION INPUT ;
    USE SIGNAL ;
    PORT
      LAYER M5 ;
        RECT  183.66 0 183.684 0.192 ;
    END
  END g_front_2_u_front__row_in[208]
  PIN g_front_2_u_front__row_in[209]
    DIRECTION INPUT ;
    USE SIGNAL ;
    PORT
      LAYER M5 ;
        RECT  183.9 0 183.924 0.192 ;
    END
  END g_front_2_u_front__row_in[209]
  PIN g_front_2_u_front__row_in[20]
    DIRECTION INPUT ;
    USE SIGNAL ;
    PORT
      LAYER M5 ;
        RECT  138.876 0 138.9 0.192 ;
    END
  END g_front_2_u_front__row_in[20]
  PIN g_front_2_u_front__row_in[210]
    DIRECTION INPUT ;
    USE SIGNAL ;
    PORT
      LAYER M5 ;
        RECT  184.14 0 184.164 0.192 ;
    END
  END g_front_2_u_front__row_in[210]
  PIN g_front_2_u_front__row_in[211]
    DIRECTION INPUT ;
    USE SIGNAL ;
    PORT
      LAYER M5 ;
        RECT  184.38 0 184.404 0.192 ;
    END
  END g_front_2_u_front__row_in[211]
  PIN g_front_2_u_front__row_in[212]
    DIRECTION INPUT ;
    USE SIGNAL ;
    PORT
      LAYER M5 ;
        RECT  184.62 0 184.644 0.192 ;
    END
  END g_front_2_u_front__row_in[212]
  PIN g_front_2_u_front__row_in[213]
    DIRECTION INPUT ;
    USE SIGNAL ;
    PORT
      LAYER M5 ;
        RECT  184.86 0 184.884 0.192 ;
    END
  END g_front_2_u_front__row_in[213]
  PIN g_front_2_u_front__row_in[214]
    DIRECTION INPUT ;
    USE SIGNAL ;
    PORT
      LAYER M5 ;
        RECT  185.1 0 185.124 0.192 ;
    END
  END g_front_2_u_front__row_in[214]
  PIN g_front_2_u_front__row_in[215]
    DIRECTION INPUT ;
    USE SIGNAL ;
    PORT
      LAYER M5 ;
        RECT  185.34 0 185.364 0.192 ;
    END
  END g_front_2_u_front__row_in[215]
  PIN g_front_2_u_front__row_in[216]
    DIRECTION INPUT ;
    USE SIGNAL ;
    PORT
      LAYER M5 ;
        RECT  185.58 0 185.604 0.192 ;
    END
  END g_front_2_u_front__row_in[216]
  PIN g_front_2_u_front__row_in[217]
    DIRECTION INPUT ;
    USE SIGNAL ;
    PORT
      LAYER M5 ;
        RECT  185.82 0 185.844 0.192 ;
    END
  END g_front_2_u_front__row_in[217]
  PIN g_front_2_u_front__row_in[218]
    DIRECTION INPUT ;
    USE SIGNAL ;
    PORT
      LAYER M5 ;
        RECT  186.06 0 186.084 0.192 ;
    END
  END g_front_2_u_front__row_in[218]
  PIN g_front_2_u_front__row_in[219]
    DIRECTION INPUT ;
    USE SIGNAL ;
    PORT
      LAYER M5 ;
        RECT  186.3 0 186.324 0.192 ;
    END
  END g_front_2_u_front__row_in[219]
  PIN g_front_2_u_front__row_in[21]
    DIRECTION INPUT ;
    USE SIGNAL ;
    PORT
      LAYER M5 ;
        RECT  139.116 0 139.14 0.192 ;
    END
  END g_front_2_u_front__row_in[21]
  PIN g_front_2_u_front__row_in[220]
    DIRECTION INPUT ;
    USE SIGNAL ;
    PORT
      LAYER M5 ;
        RECT  186.54 0 186.564 0.192 ;
    END
  END g_front_2_u_front__row_in[220]
  PIN g_front_2_u_front__row_in[221]
    DIRECTION INPUT ;
    USE SIGNAL ;
    PORT
      LAYER M5 ;
        RECT  186.78 0 186.804 0.192 ;
    END
  END g_front_2_u_front__row_in[221]
  PIN g_front_2_u_front__row_in[222]
    DIRECTION INPUT ;
    USE SIGNAL ;
    PORT
      LAYER M5 ;
        RECT  187.02 0 187.044 0.192 ;
    END
  END g_front_2_u_front__row_in[222]
  PIN g_front_2_u_front__row_in[223]
    DIRECTION INPUT ;
    USE SIGNAL ;
    PORT
      LAYER M5 ;
        RECT  187.26 0 187.284 0.192 ;
    END
  END g_front_2_u_front__row_in[223]
  PIN g_front_2_u_front__row_in[224]
    DIRECTION INPUT ;
    USE SIGNAL ;
    PORT
      LAYER M5 ;
        RECT  187.5 0 187.524 0.192 ;
    END
  END g_front_2_u_front__row_in[224]
  PIN g_front_2_u_front__row_in[225]
    DIRECTION INPUT ;
    USE SIGNAL ;
    PORT
      LAYER M5 ;
        RECT  187.74 0 187.764 0.192 ;
    END
  END g_front_2_u_front__row_in[225]
  PIN g_front_2_u_front__row_in[226]
    DIRECTION INPUT ;
    USE SIGNAL ;
    PORT
      LAYER M5 ;
        RECT  187.98 0 188.004 0.192 ;
    END
  END g_front_2_u_front__row_in[226]
  PIN g_front_2_u_front__row_in[227]
    DIRECTION INPUT ;
    USE SIGNAL ;
    PORT
      LAYER M5 ;
        RECT  188.22 0 188.244 0.192 ;
    END
  END g_front_2_u_front__row_in[227]
  PIN g_front_2_u_front__row_in[228]
    DIRECTION INPUT ;
    USE SIGNAL ;
    PORT
      LAYER M5 ;
        RECT  188.46 0 188.484 0.192 ;
    END
  END g_front_2_u_front__row_in[228]
  PIN g_front_2_u_front__row_in[229]
    DIRECTION INPUT ;
    USE SIGNAL ;
    PORT
      LAYER M5 ;
        RECT  188.7 0 188.724 0.192 ;
    END
  END g_front_2_u_front__row_in[229]
  PIN g_front_2_u_front__row_in[22]
    DIRECTION INPUT ;
    USE SIGNAL ;
    PORT
      LAYER M5 ;
        RECT  139.356 0 139.38 0.192 ;
    END
  END g_front_2_u_front__row_in[22]
  PIN g_front_2_u_front__row_in[230]
    DIRECTION INPUT ;
    USE SIGNAL ;
    PORT
      LAYER M5 ;
        RECT  188.94 0 188.964 0.192 ;
    END
  END g_front_2_u_front__row_in[230]
  PIN g_front_2_u_front__row_in[231]
    DIRECTION INPUT ;
    USE SIGNAL ;
    PORT
      LAYER M5 ;
        RECT  189.132 0 189.156 0.192 ;
    END
  END g_front_2_u_front__row_in[231]
  PIN g_front_2_u_front__row_in[232]
    DIRECTION INPUT ;
    USE SIGNAL ;
    PORT
      LAYER M5 ;
        RECT  189.372 0 189.396 0.192 ;
    END
  END g_front_2_u_front__row_in[232]
  PIN g_front_2_u_front__row_in[233]
    DIRECTION INPUT ;
    USE SIGNAL ;
    PORT
      LAYER M5 ;
        RECT  189.612 0 189.636 0.192 ;
    END
  END g_front_2_u_front__row_in[233]
  PIN g_front_2_u_front__row_in[234]
    DIRECTION INPUT ;
    USE SIGNAL ;
    PORT
      LAYER M5 ;
        RECT  189.852 0 189.876 0.192 ;
    END
  END g_front_2_u_front__row_in[234]
  PIN g_front_2_u_front__row_in[235]
    DIRECTION INPUT ;
    USE SIGNAL ;
    PORT
      LAYER M5 ;
        RECT  190.092 0 190.116 0.192 ;
    END
  END g_front_2_u_front__row_in[235]
  PIN g_front_2_u_front__row_in[236]
    DIRECTION INPUT ;
    USE SIGNAL ;
    PORT
      LAYER M5 ;
        RECT  190.332 0 190.356 0.192 ;
    END
  END g_front_2_u_front__row_in[236]
  PIN g_front_2_u_front__row_in[237]
    DIRECTION INPUT ;
    USE SIGNAL ;
    PORT
      LAYER M5 ;
        RECT  190.572 0 190.596 0.192 ;
    END
  END g_front_2_u_front__row_in[237]
  PIN g_front_2_u_front__row_in[238]
    DIRECTION INPUT ;
    USE SIGNAL ;
    PORT
      LAYER M5 ;
        RECT  190.812 0 190.836 0.192 ;
    END
  END g_front_2_u_front__row_in[238]
  PIN g_front_2_u_front__row_in[239]
    DIRECTION INPUT ;
    USE SIGNAL ;
    PORT
      LAYER M5 ;
        RECT  191.052 0 191.076 0.192 ;
    END
  END g_front_2_u_front__row_in[239]
  PIN g_front_2_u_front__row_in[23]
    DIRECTION INPUT ;
    USE SIGNAL ;
    PORT
      LAYER M5 ;
        RECT  139.596 0 139.62 0.192 ;
    END
  END g_front_2_u_front__row_in[23]
  PIN g_front_2_u_front__row_in[240]
    DIRECTION INPUT ;
    USE SIGNAL ;
    PORT
      LAYER M5 ;
        RECT  191.292 0 191.316 0.192 ;
    END
  END g_front_2_u_front__row_in[240]
  PIN g_front_2_u_front__row_in[241]
    DIRECTION INPUT ;
    USE SIGNAL ;
    PORT
      LAYER M5 ;
        RECT  191.532 0 191.556 0.192 ;
    END
  END g_front_2_u_front__row_in[241]
  PIN g_front_2_u_front__row_in[242]
    DIRECTION INPUT ;
    USE SIGNAL ;
    PORT
      LAYER M5 ;
        RECT  191.772 0 191.796 0.192 ;
    END
  END g_front_2_u_front__row_in[242]
  PIN g_front_2_u_front__row_in[243]
    DIRECTION INPUT ;
    USE SIGNAL ;
    PORT
      LAYER M5 ;
        RECT  192.012 0 192.036 0.192 ;
    END
  END g_front_2_u_front__row_in[243]
  PIN g_front_2_u_front__row_in[244]
    DIRECTION INPUT ;
    USE SIGNAL ;
    PORT
      LAYER M5 ;
        RECT  192.252 0 192.276 0.192 ;
    END
  END g_front_2_u_front__row_in[244]
  PIN g_front_2_u_front__row_in[245]
    DIRECTION INPUT ;
    USE SIGNAL ;
    PORT
      LAYER M5 ;
        RECT  192.492 0 192.516 0.192 ;
    END
  END g_front_2_u_front__row_in[245]
  PIN g_front_2_u_front__row_in[246]
    DIRECTION INPUT ;
    USE SIGNAL ;
    PORT
      LAYER M5 ;
        RECT  192.732 0 192.756 0.192 ;
    END
  END g_front_2_u_front__row_in[246]
  PIN g_front_2_u_front__row_in[247]
    DIRECTION INPUT ;
    USE SIGNAL ;
    PORT
      LAYER M5 ;
        RECT  192.972 0 192.996 0.192 ;
    END
  END g_front_2_u_front__row_in[247]
  PIN g_front_2_u_front__row_in[248]
    DIRECTION INPUT ;
    USE SIGNAL ;
    PORT
      LAYER M5 ;
        RECT  193.212 0 193.236 0.192 ;
    END
  END g_front_2_u_front__row_in[248]
  PIN g_front_2_u_front__row_in[249]
    DIRECTION INPUT ;
    USE SIGNAL ;
    PORT
      LAYER M5 ;
        RECT  193.452 0 193.476 0.192 ;
    END
  END g_front_2_u_front__row_in[249]
  PIN g_front_2_u_front__row_in[24]
    DIRECTION INPUT ;
    USE SIGNAL ;
    PORT
      LAYER M5 ;
        RECT  139.788 0 139.812 0.192 ;
    END
  END g_front_2_u_front__row_in[24]
  PIN g_front_2_u_front__row_in[250]
    DIRECTION INPUT ;
    USE SIGNAL ;
    PORT
      LAYER M5 ;
        RECT  193.692 0 193.716 0.192 ;
    END
  END g_front_2_u_front__row_in[250]
  PIN g_front_2_u_front__row_in[251]
    DIRECTION INPUT ;
    USE SIGNAL ;
    PORT
      LAYER M5 ;
        RECT  193.932 0 193.956 0.192 ;
    END
  END g_front_2_u_front__row_in[251]
  PIN g_front_2_u_front__row_in[252]
    DIRECTION INPUT ;
    USE SIGNAL ;
    PORT
      LAYER M5 ;
        RECT  194.172 0 194.196 0.192 ;
    END
  END g_front_2_u_front__row_in[252]
  PIN g_front_2_u_front__row_in[253]
    DIRECTION INPUT ;
    USE SIGNAL ;
    PORT
      LAYER M5 ;
        RECT  194.412 0 194.436 0.192 ;
    END
  END g_front_2_u_front__row_in[253]
  PIN g_front_2_u_front__row_in[254]
    DIRECTION INPUT ;
    USE SIGNAL ;
    PORT
      LAYER M5 ;
        RECT  194.652 0 194.676 0.192 ;
    END
  END g_front_2_u_front__row_in[254]
  PIN g_front_2_u_front__row_in[255]
    DIRECTION INPUT ;
    USE SIGNAL ;
    PORT
      LAYER M5 ;
        RECT  194.892 0 194.916 0.192 ;
    END
  END g_front_2_u_front__row_in[255]
  PIN g_front_2_u_front__row_in[25]
    DIRECTION INPUT ;
    USE SIGNAL ;
    PORT
      LAYER M5 ;
        RECT  140.028 0 140.052 0.192 ;
    END
  END g_front_2_u_front__row_in[25]
  PIN g_front_2_u_front__row_in[26]
    DIRECTION INPUT ;
    USE SIGNAL ;
    PORT
      LAYER M5 ;
        RECT  140.268 0 140.292 0.192 ;
    END
  END g_front_2_u_front__row_in[26]
  PIN g_front_2_u_front__row_in[27]
    DIRECTION INPUT ;
    USE SIGNAL ;
    PORT
      LAYER M5 ;
        RECT  140.508 0 140.532 0.192 ;
    END
  END g_front_2_u_front__row_in[27]
  PIN g_front_2_u_front__row_in[28]
    DIRECTION INPUT ;
    USE SIGNAL ;
    PORT
      LAYER M5 ;
        RECT  140.748 0 140.772 0.192 ;
    END
  END g_front_2_u_front__row_in[28]
  PIN g_front_2_u_front__row_in[29]
    DIRECTION INPUT ;
    USE SIGNAL ;
    PORT
      LAYER M5 ;
        RECT  140.988 0 141.012 0.192 ;
    END
  END g_front_2_u_front__row_in[29]
  PIN g_front_2_u_front__row_in[2]
    DIRECTION INPUT ;
    USE SIGNAL ;
    PORT
      LAYER M5 ;
        RECT  134.556 0 134.58 0.192 ;
    END
  END g_front_2_u_front__row_in[2]
  PIN g_front_2_u_front__row_in[30]
    DIRECTION INPUT ;
    USE SIGNAL ;
    PORT
      LAYER M5 ;
        RECT  141.228 0 141.252 0.192 ;
    END
  END g_front_2_u_front__row_in[30]
  PIN g_front_2_u_front__row_in[31]
    DIRECTION INPUT ;
    USE SIGNAL ;
    PORT
      LAYER M5 ;
        RECT  141.468 0 141.492 0.192 ;
    END
  END g_front_2_u_front__row_in[31]
  PIN g_front_2_u_front__row_in[32]
    DIRECTION INPUT ;
    USE SIGNAL ;
    PORT
      LAYER M5 ;
        RECT  141.708 0 141.732 0.192 ;
    END
  END g_front_2_u_front__row_in[32]
  PIN g_front_2_u_front__row_in[33]
    DIRECTION INPUT ;
    USE SIGNAL ;
    PORT
      LAYER M5 ;
        RECT  141.948 0 141.972 0.192 ;
    END
  END g_front_2_u_front__row_in[33]
  PIN g_front_2_u_front__row_in[34]
    DIRECTION INPUT ;
    USE SIGNAL ;
    PORT
      LAYER M5 ;
        RECT  142.188 0 142.212 0.192 ;
    END
  END g_front_2_u_front__row_in[34]
  PIN g_front_2_u_front__row_in[35]
    DIRECTION INPUT ;
    USE SIGNAL ;
    PORT
      LAYER M5 ;
        RECT  142.428 0 142.452 0.192 ;
    END
  END g_front_2_u_front__row_in[35]
  PIN g_front_2_u_front__row_in[36]
    DIRECTION INPUT ;
    USE SIGNAL ;
    PORT
      LAYER M5 ;
        RECT  142.668 0 142.692 0.192 ;
    END
  END g_front_2_u_front__row_in[36]
  PIN g_front_2_u_front__row_in[37]
    DIRECTION INPUT ;
    USE SIGNAL ;
    PORT
      LAYER M5 ;
        RECT  142.908 0 142.932 0.192 ;
    END
  END g_front_2_u_front__row_in[37]
  PIN g_front_2_u_front__row_in[38]
    DIRECTION INPUT ;
    USE SIGNAL ;
    PORT
      LAYER M5 ;
        RECT  143.148 0 143.172 0.192 ;
    END
  END g_front_2_u_front__row_in[38]
  PIN g_front_2_u_front__row_in[39]
    DIRECTION INPUT ;
    USE SIGNAL ;
    PORT
      LAYER M5 ;
        RECT  143.388 0 143.412 0.192 ;
    END
  END g_front_2_u_front__row_in[39]
  PIN g_front_2_u_front__row_in[3]
    DIRECTION INPUT ;
    USE SIGNAL ;
    PORT
      LAYER M5 ;
        RECT  134.796 0 134.82 0.192 ;
    END
  END g_front_2_u_front__row_in[3]
  PIN g_front_2_u_front__row_in[40]
    DIRECTION INPUT ;
    USE SIGNAL ;
    PORT
      LAYER M5 ;
        RECT  143.628 0 143.652 0.192 ;
    END
  END g_front_2_u_front__row_in[40]
  PIN g_front_2_u_front__row_in[41]
    DIRECTION INPUT ;
    USE SIGNAL ;
    PORT
      LAYER M5 ;
        RECT  143.868 0 143.892 0.192 ;
    END
  END g_front_2_u_front__row_in[41]
  PIN g_front_2_u_front__row_in[42]
    DIRECTION INPUT ;
    USE SIGNAL ;
    PORT
      LAYER M5 ;
        RECT  144.108 0 144.132 0.192 ;
    END
  END g_front_2_u_front__row_in[42]
  PIN g_front_2_u_front__row_in[43]
    DIRECTION INPUT ;
    USE SIGNAL ;
    PORT
      LAYER M5 ;
        RECT  144.348 0 144.372 0.192 ;
    END
  END g_front_2_u_front__row_in[43]
  PIN g_front_2_u_front__row_in[44]
    DIRECTION INPUT ;
    USE SIGNAL ;
    PORT
      LAYER M5 ;
        RECT  144.588 0 144.612 0.192 ;
    END
  END g_front_2_u_front__row_in[44]
  PIN g_front_2_u_front__row_in[45]
    DIRECTION INPUT ;
    USE SIGNAL ;
    PORT
      LAYER M5 ;
        RECT  144.828 0 144.852 0.192 ;
    END
  END g_front_2_u_front__row_in[45]
  PIN g_front_2_u_front__row_in[46]
    DIRECTION INPUT ;
    USE SIGNAL ;
    PORT
      LAYER M5 ;
        RECT  145.068 0 145.092 0.192 ;
    END
  END g_front_2_u_front__row_in[46]
  PIN g_front_2_u_front__row_in[47]
    DIRECTION INPUT ;
    USE SIGNAL ;
    PORT
      LAYER M5 ;
        RECT  145.308 0 145.332 0.192 ;
    END
  END g_front_2_u_front__row_in[47]
  PIN g_front_2_u_front__row_in[48]
    DIRECTION INPUT ;
    USE SIGNAL ;
    PORT
      LAYER M5 ;
        RECT  145.548 0 145.572 0.192 ;
    END
  END g_front_2_u_front__row_in[48]
  PIN g_front_2_u_front__row_in[49]
    DIRECTION INPUT ;
    USE SIGNAL ;
    PORT
      LAYER M5 ;
        RECT  145.788 0 145.812 0.192 ;
    END
  END g_front_2_u_front__row_in[49]
  PIN g_front_2_u_front__row_in[4]
    DIRECTION INPUT ;
    USE SIGNAL ;
    PORT
      LAYER M5 ;
        RECT  135.036 0 135.06 0.192 ;
    END
  END g_front_2_u_front__row_in[4]
  PIN g_front_2_u_front__row_in[50]
    DIRECTION INPUT ;
    USE SIGNAL ;
    PORT
      LAYER M5 ;
        RECT  146.028 0 146.052 0.192 ;
    END
  END g_front_2_u_front__row_in[50]
  PIN g_front_2_u_front__row_in[51]
    DIRECTION INPUT ;
    USE SIGNAL ;
    PORT
      LAYER M5 ;
        RECT  146.268 0 146.292 0.192 ;
    END
  END g_front_2_u_front__row_in[51]
  PIN g_front_2_u_front__row_in[52]
    DIRECTION INPUT ;
    USE SIGNAL ;
    PORT
      LAYER M5 ;
        RECT  146.508 0 146.532 0.192 ;
    END
  END g_front_2_u_front__row_in[52]
  PIN g_front_2_u_front__row_in[53]
    DIRECTION INPUT ;
    USE SIGNAL ;
    PORT
      LAYER M5 ;
        RECT  146.748 0 146.772 0.192 ;
    END
  END g_front_2_u_front__row_in[53]
  PIN g_front_2_u_front__row_in[54]
    DIRECTION INPUT ;
    USE SIGNAL ;
    PORT
      LAYER M5 ;
        RECT  146.94 0 146.964 0.192 ;
    END
  END g_front_2_u_front__row_in[54]
  PIN g_front_2_u_front__row_in[55]
    DIRECTION INPUT ;
    USE SIGNAL ;
    PORT
      LAYER M5 ;
        RECT  147.18 0 147.204 0.192 ;
    END
  END g_front_2_u_front__row_in[55]
  PIN g_front_2_u_front__row_in[56]
    DIRECTION INPUT ;
    USE SIGNAL ;
    PORT
      LAYER M5 ;
        RECT  147.42 0 147.444 0.192 ;
    END
  END g_front_2_u_front__row_in[56]
  PIN g_front_2_u_front__row_in[57]
    DIRECTION INPUT ;
    USE SIGNAL ;
    PORT
      LAYER M5 ;
        RECT  147.66 0 147.684 0.192 ;
    END
  END g_front_2_u_front__row_in[57]
  PIN g_front_2_u_front__row_in[58]
    DIRECTION INPUT ;
    USE SIGNAL ;
    PORT
      LAYER M5 ;
        RECT  147.9 0 147.924 0.192 ;
    END
  END g_front_2_u_front__row_in[58]
  PIN g_front_2_u_front__row_in[59]
    DIRECTION INPUT ;
    USE SIGNAL ;
    PORT
      LAYER M5 ;
        RECT  148.14 0 148.164 0.192 ;
    END
  END g_front_2_u_front__row_in[59]
  PIN g_front_2_u_front__row_in[5]
    DIRECTION INPUT ;
    USE SIGNAL ;
    PORT
      LAYER M5 ;
        RECT  135.276 0 135.3 0.192 ;
    END
  END g_front_2_u_front__row_in[5]
  PIN g_front_2_u_front__row_in[60]
    DIRECTION INPUT ;
    USE SIGNAL ;
    PORT
      LAYER M5 ;
        RECT  148.38 0 148.404 0.192 ;
    END
  END g_front_2_u_front__row_in[60]
  PIN g_front_2_u_front__row_in[61]
    DIRECTION INPUT ;
    USE SIGNAL ;
    PORT
      LAYER M5 ;
        RECT  148.62 0 148.644 0.192 ;
    END
  END g_front_2_u_front__row_in[61]
  PIN g_front_2_u_front__row_in[62]
    DIRECTION INPUT ;
    USE SIGNAL ;
    PORT
      LAYER M5 ;
        RECT  148.86 0 148.884 0.192 ;
    END
  END g_front_2_u_front__row_in[62]
  PIN g_front_2_u_front__row_in[63]
    DIRECTION INPUT ;
    USE SIGNAL ;
    PORT
      LAYER M5 ;
        RECT  149.1 0 149.124 0.192 ;
    END
  END g_front_2_u_front__row_in[63]
  PIN g_front_2_u_front__row_in[64]
    DIRECTION INPUT ;
    USE SIGNAL ;
    PORT
      LAYER M5 ;
        RECT  149.34 0 149.364 0.192 ;
    END
  END g_front_2_u_front__row_in[64]
  PIN g_front_2_u_front__row_in[65]
    DIRECTION INPUT ;
    USE SIGNAL ;
    PORT
      LAYER M5 ;
        RECT  149.58 0 149.604 0.192 ;
    END
  END g_front_2_u_front__row_in[65]
  PIN g_front_2_u_front__row_in[66]
    DIRECTION INPUT ;
    USE SIGNAL ;
    PORT
      LAYER M5 ;
        RECT  149.82 0 149.844 0.192 ;
    END
  END g_front_2_u_front__row_in[66]
  PIN g_front_2_u_front__row_in[67]
    DIRECTION INPUT ;
    USE SIGNAL ;
    PORT
      LAYER M5 ;
        RECT  150.06 0 150.084 0.192 ;
    END
  END g_front_2_u_front__row_in[67]
  PIN g_front_2_u_front__row_in[68]
    DIRECTION INPUT ;
    USE SIGNAL ;
    PORT
      LAYER M5 ;
        RECT  150.3 0 150.324 0.192 ;
    END
  END g_front_2_u_front__row_in[68]
  PIN g_front_2_u_front__row_in[69]
    DIRECTION INPUT ;
    USE SIGNAL ;
    PORT
      LAYER M5 ;
        RECT  150.54 0 150.564 0.192 ;
    END
  END g_front_2_u_front__row_in[69]
  PIN g_front_2_u_front__row_in[6]
    DIRECTION INPUT ;
    USE SIGNAL ;
    PORT
      LAYER M5 ;
        RECT  135.516 0 135.54 0.192 ;
    END
  END g_front_2_u_front__row_in[6]
  PIN g_front_2_u_front__row_in[70]
    DIRECTION INPUT ;
    USE SIGNAL ;
    PORT
      LAYER M5 ;
        RECT  150.78 0 150.804 0.192 ;
    END
  END g_front_2_u_front__row_in[70]
  PIN g_front_2_u_front__row_in[71]
    DIRECTION INPUT ;
    USE SIGNAL ;
    PORT
      LAYER M5 ;
        RECT  151.02 0 151.044 0.192 ;
    END
  END g_front_2_u_front__row_in[71]
  PIN g_front_2_u_front__row_in[72]
    DIRECTION INPUT ;
    USE SIGNAL ;
    PORT
      LAYER M5 ;
        RECT  151.26 0 151.284 0.192 ;
    END
  END g_front_2_u_front__row_in[72]
  PIN g_front_2_u_front__row_in[73]
    DIRECTION INPUT ;
    USE SIGNAL ;
    PORT
      LAYER M5 ;
        RECT  151.5 0 151.524 0.192 ;
    END
  END g_front_2_u_front__row_in[73]
  PIN g_front_2_u_front__row_in[74]
    DIRECTION INPUT ;
    USE SIGNAL ;
    PORT
      LAYER M5 ;
        RECT  151.74 0 151.764 0.192 ;
    END
  END g_front_2_u_front__row_in[74]
  PIN g_front_2_u_front__row_in[75]
    DIRECTION INPUT ;
    USE SIGNAL ;
    PORT
      LAYER M5 ;
        RECT  151.98 0 152.004 0.192 ;
    END
  END g_front_2_u_front__row_in[75]
  PIN g_front_2_u_front__row_in[76]
    DIRECTION INPUT ;
    USE SIGNAL ;
    PORT
      LAYER M5 ;
        RECT  152.22 0 152.244 0.192 ;
    END
  END g_front_2_u_front__row_in[76]
  PIN g_front_2_u_front__row_in[77]
    DIRECTION INPUT ;
    USE SIGNAL ;
    PORT
      LAYER M5 ;
        RECT  152.46 0 152.484 0.192 ;
    END
  END g_front_2_u_front__row_in[77]
  PIN g_front_2_u_front__row_in[78]
    DIRECTION INPUT ;
    USE SIGNAL ;
    PORT
      LAYER M5 ;
        RECT  152.7 0 152.724 0.192 ;
    END
  END g_front_2_u_front__row_in[78]
  PIN g_front_2_u_front__row_in[79]
    DIRECTION INPUT ;
    USE SIGNAL ;
    PORT
      LAYER M5 ;
        RECT  152.94 0 152.964 0.192 ;
    END
  END g_front_2_u_front__row_in[79]
  PIN g_front_2_u_front__row_in[7]
    DIRECTION INPUT ;
    USE SIGNAL ;
    PORT
      LAYER M5 ;
        RECT  135.756 0 135.78 0.192 ;
    END
  END g_front_2_u_front__row_in[7]
  PIN g_front_2_u_front__row_in[80]
    DIRECTION INPUT ;
    USE SIGNAL ;
    PORT
      LAYER M5 ;
        RECT  153.18 0 153.204 0.192 ;
    END
  END g_front_2_u_front__row_in[80]
  PIN g_front_2_u_front__row_in[81]
    DIRECTION INPUT ;
    USE SIGNAL ;
    PORT
      LAYER M5 ;
        RECT  153.42 0 153.444 0.192 ;
    END
  END g_front_2_u_front__row_in[81]
  PIN g_front_2_u_front__row_in[82]
    DIRECTION INPUT ;
    USE SIGNAL ;
    PORT
      LAYER M5 ;
        RECT  153.66 0 153.684 0.192 ;
    END
  END g_front_2_u_front__row_in[82]
  PIN g_front_2_u_front__row_in[83]
    DIRECTION INPUT ;
    USE SIGNAL ;
    PORT
      LAYER M5 ;
        RECT  153.852 0 153.876 0.192 ;
    END
  END g_front_2_u_front__row_in[83]
  PIN g_front_2_u_front__row_in[84]
    DIRECTION INPUT ;
    USE SIGNAL ;
    PORT
      LAYER M5 ;
        RECT  154.092 0 154.116 0.192 ;
    END
  END g_front_2_u_front__row_in[84]
  PIN g_front_2_u_front__row_in[85]
    DIRECTION INPUT ;
    USE SIGNAL ;
    PORT
      LAYER M5 ;
        RECT  154.332 0 154.356 0.192 ;
    END
  END g_front_2_u_front__row_in[85]
  PIN g_front_2_u_front__row_in[86]
    DIRECTION INPUT ;
    USE SIGNAL ;
    PORT
      LAYER M5 ;
        RECT  154.572 0 154.596 0.192 ;
    END
  END g_front_2_u_front__row_in[86]
  PIN g_front_2_u_front__row_in[87]
    DIRECTION INPUT ;
    USE SIGNAL ;
    PORT
      LAYER M5 ;
        RECT  154.812 0 154.836 0.192 ;
    END
  END g_front_2_u_front__row_in[87]
  PIN g_front_2_u_front__row_in[88]
    DIRECTION INPUT ;
    USE SIGNAL ;
    PORT
      LAYER M5 ;
        RECT  155.052 0 155.076 0.192 ;
    END
  END g_front_2_u_front__row_in[88]
  PIN g_front_2_u_front__row_in[89]
    DIRECTION INPUT ;
    USE SIGNAL ;
    PORT
      LAYER M5 ;
        RECT  155.292 0 155.316 0.192 ;
    END
  END g_front_2_u_front__row_in[89]
  PIN g_front_2_u_front__row_in[8]
    DIRECTION INPUT ;
    USE SIGNAL ;
    PORT
      LAYER M5 ;
        RECT  135.996 0 136.02 0.192 ;
    END
  END g_front_2_u_front__row_in[8]
  PIN g_front_2_u_front__row_in[90]
    DIRECTION INPUT ;
    USE SIGNAL ;
    PORT
      LAYER M5 ;
        RECT  155.532 0 155.556 0.192 ;
    END
  END g_front_2_u_front__row_in[90]
  PIN g_front_2_u_front__row_in[91]
    DIRECTION INPUT ;
    USE SIGNAL ;
    PORT
      LAYER M5 ;
        RECT  155.772 0 155.796 0.192 ;
    END
  END g_front_2_u_front__row_in[91]
  PIN g_front_2_u_front__row_in[92]
    DIRECTION INPUT ;
    USE SIGNAL ;
    PORT
      LAYER M5 ;
        RECT  156.012 0 156.036 0.192 ;
    END
  END g_front_2_u_front__row_in[92]
  PIN g_front_2_u_front__row_in[93]
    DIRECTION INPUT ;
    USE SIGNAL ;
    PORT
      LAYER M5 ;
        RECT  156.252 0 156.276 0.192 ;
    END
  END g_front_2_u_front__row_in[93]
  PIN g_front_2_u_front__row_in[94]
    DIRECTION INPUT ;
    USE SIGNAL ;
    PORT
      LAYER M5 ;
        RECT  156.492 0 156.516 0.192 ;
    END
  END g_front_2_u_front__row_in[94]
  PIN g_front_2_u_front__row_in[95]
    DIRECTION INPUT ;
    USE SIGNAL ;
    PORT
      LAYER M5 ;
        RECT  156.732 0 156.756 0.192 ;
    END
  END g_front_2_u_front__row_in[95]
  PIN g_front_2_u_front__row_in[96]
    DIRECTION INPUT ;
    USE SIGNAL ;
    PORT
      LAYER M5 ;
        RECT  156.972 0 156.996 0.192 ;
    END
  END g_front_2_u_front__row_in[96]
  PIN g_front_2_u_front__row_in[97]
    DIRECTION INPUT ;
    USE SIGNAL ;
    PORT
      LAYER M5 ;
        RECT  157.212 0 157.236 0.192 ;
    END
  END g_front_2_u_front__row_in[97]
  PIN g_front_2_u_front__row_in[98]
    DIRECTION INPUT ;
    USE SIGNAL ;
    PORT
      LAYER M5 ;
        RECT  157.452 0 157.476 0.192 ;
    END
  END g_front_2_u_front__row_in[98]
  PIN g_front_2_u_front__row_in[99]
    DIRECTION INPUT ;
    USE SIGNAL ;
    PORT
      LAYER M5 ;
        RECT  157.692 0 157.716 0.192 ;
    END
  END g_front_2_u_front__row_in[99]
  PIN g_front_2_u_front__row_in[9]
    DIRECTION INPUT ;
    USE SIGNAL ;
    PORT
      LAYER M5 ;
        RECT  136.236 0 136.26 0.192 ;
    END
  END g_front_2_u_front__row_in[9]
  PIN g_front_2_u_front__rst_n[0]
    DIRECTION INPUT ;
    USE SIGNAL ;
    PORT
      LAYER M5 ;
        RECT  195.132 0 195.156 0.192 ;
    END
  END g_front_2_u_front__rst_n[0]
  PIN g_t_8_u_l8__clk[0]
    DIRECTION INPUT ;
    USE SIGNAL ;
    PORT
      LAYER M5 ;
        RECT  195.372 0 195.396 0.192 ;
    END
  END g_t_8_u_l8__clk[0]
  PIN g_t_8_u_stin__clk[0]
    DIRECTION INPUT ;
    USE SIGNAL ;
    PORT
      LAYER M5 ;
        RECT  195.612 0 195.636 0.192 ;
    END
  END g_t_8_u_stin__clk[0]
  PIN g_t_8_u_stin__rst_n[0]
    DIRECTION INPUT ;
    USE SIGNAL ;
    PORT
      LAYER M5 ;
        RECT  195.852 0 195.876 0.192 ;
    END
  END g_t_8_u_stin__rst_n[0]
  PIN g_t_8_u_stk__clk[0]
    DIRECTION INPUT ;
    USE SIGNAL ;
    PORT
      LAYER M5 ;
        RECT  196.092 0 196.116 0.192 ;
    END
  END g_t_8_u_stk__clk[0]
  PIN g_t_8_u_stk__gf_o[0]
    DIRECTION OUTPUT ;
    USE SIGNAL ;
    PORT
      LAYER M5 ;
        RECT  196.284 0 196.308 0.192 ;
    END
  END g_t_8_u_stk__gf_o[0]
  PIN g_t_8_u_stk__kp_o[0]
    DIRECTION OUTPUT ;
    USE SIGNAL ;
    PORT
      LAYER M5 ;
        RECT  196.524 0 196.548 0.192 ;
    END
  END g_t_8_u_stk__kp_o[0]
  PIN g_t_8_u_stk__kp_o[10]
    DIRECTION OUTPUT ;
    USE SIGNAL ;
    PORT
      LAYER M5 ;
        RECT  198.924 0 198.948 0.192 ;
    END
  END g_t_8_u_stk__kp_o[10]
  PIN g_t_8_u_stk__kp_o[11]
    DIRECTION OUTPUT ;
    USE SIGNAL ;
    PORT
      LAYER M5 ;
        RECT  199.164 0 199.188 0.192 ;
    END
  END g_t_8_u_stk__kp_o[11]
  PIN g_t_8_u_stk__kp_o[12]
    DIRECTION OUTPUT ;
    USE SIGNAL ;
    PORT
      LAYER M5 ;
        RECT  199.404 0 199.428 0.192 ;
    END
  END g_t_8_u_stk__kp_o[12]
  PIN g_t_8_u_stk__kp_o[13]
    DIRECTION OUTPUT ;
    USE SIGNAL ;
    PORT
      LAYER M5 ;
        RECT  199.644 0 199.668 0.192 ;
    END
  END g_t_8_u_stk__kp_o[13]
  PIN g_t_8_u_stk__kp_o[14]
    DIRECTION OUTPUT ;
    USE SIGNAL ;
    PORT
      LAYER M5 ;
        RECT  199.884 0 199.908 0.192 ;
    END
  END g_t_8_u_stk__kp_o[14]
  PIN g_t_8_u_stk__kp_o[15]
    DIRECTION OUTPUT ;
    USE SIGNAL ;
    PORT
      LAYER M5 ;
        RECT  200.124 0 200.148 0.192 ;
    END
  END g_t_8_u_stk__kp_o[15]
  PIN g_t_8_u_stk__kp_o[16]
    DIRECTION OUTPUT ;
    USE SIGNAL ;
    PORT
      LAYER M5 ;
        RECT  200.364 0 200.388 0.192 ;
    END
  END g_t_8_u_stk__kp_o[16]
  PIN g_t_8_u_stk__kp_o[17]
    DIRECTION OUTPUT ;
    USE SIGNAL ;
    PORT
      LAYER M5 ;
        RECT  200.604 0 200.628 0.192 ;
    END
  END g_t_8_u_stk__kp_o[17]
  PIN g_t_8_u_stk__kp_o[18]
    DIRECTION OUTPUT ;
    USE SIGNAL ;
    PORT
      LAYER M5 ;
        RECT  200.844 0 200.868 0.192 ;
    END
  END g_t_8_u_stk__kp_o[18]
  PIN g_t_8_u_stk__kp_o[19]
    DIRECTION OUTPUT ;
    USE SIGNAL ;
    PORT
      LAYER M5 ;
        RECT  201.084 0 201.108 0.192 ;
    END
  END g_t_8_u_stk__kp_o[19]
  PIN g_t_8_u_stk__kp_o[1]
    DIRECTION OUTPUT ;
    USE SIGNAL ;
    PORT
      LAYER M5 ;
        RECT  196.764 0 196.788 0.192 ;
    END
  END g_t_8_u_stk__kp_o[1]
  PIN g_t_8_u_stk__kp_o[20]
    DIRECTION OUTPUT ;
    USE SIGNAL ;
    PORT
      LAYER M5 ;
        RECT  201.324 0 201.348 0.192 ;
    END
  END g_t_8_u_stk__kp_o[20]
  PIN g_t_8_u_stk__kp_o[21]
    DIRECTION OUTPUT ;
    USE SIGNAL ;
    PORT
      LAYER M5 ;
        RECT  201.564 0 201.588 0.192 ;
    END
  END g_t_8_u_stk__kp_o[21]
  PIN g_t_8_u_stk__kp_o[22]
    DIRECTION OUTPUT ;
    USE SIGNAL ;
    PORT
      LAYER M5 ;
        RECT  201.804 0 201.828 0.192 ;
    END
  END g_t_8_u_stk__kp_o[22]
  PIN g_t_8_u_stk__kp_o[23]
    DIRECTION OUTPUT ;
    USE SIGNAL ;
    PORT
      LAYER M5 ;
        RECT  202.044 0 202.068 0.192 ;
    END
  END g_t_8_u_stk__kp_o[23]
  PIN g_t_8_u_stk__kp_o[24]
    DIRECTION OUTPUT ;
    USE SIGNAL ;
    PORT
      LAYER M5 ;
        RECT  202.284 0 202.308 0.192 ;
    END
  END g_t_8_u_stk__kp_o[24]
  PIN g_t_8_u_stk__kp_o[25]
    DIRECTION OUTPUT ;
    USE SIGNAL ;
    PORT
      LAYER M5 ;
        RECT  202.524 0 202.548 0.192 ;
    END
  END g_t_8_u_stk__kp_o[25]
  PIN g_t_8_u_stk__kp_o[26]
    DIRECTION OUTPUT ;
    USE SIGNAL ;
    PORT
      LAYER M5 ;
        RECT  202.764 0 202.788 0.192 ;
    END
  END g_t_8_u_stk__kp_o[26]
  PIN g_t_8_u_stk__kp_o[27]
    DIRECTION OUTPUT ;
    USE SIGNAL ;
    PORT
      LAYER M5 ;
        RECT  203.004 0 203.028 0.192 ;
    END
  END g_t_8_u_stk__kp_o[27]
  PIN g_t_8_u_stk__kp_o[28]
    DIRECTION OUTPUT ;
    USE SIGNAL ;
    PORT
      LAYER M5 ;
        RECT  203.244 0 203.268 0.192 ;
    END
  END g_t_8_u_stk__kp_o[28]
  PIN g_t_8_u_stk__kp_o[29]
    DIRECTION OUTPUT ;
    USE SIGNAL ;
    PORT
      LAYER M5 ;
        RECT  203.436 0 203.46 0.192 ;
    END
  END g_t_8_u_stk__kp_o[29]
  PIN g_t_8_u_stk__kp_o[2]
    DIRECTION OUTPUT ;
    USE SIGNAL ;
    PORT
      LAYER M5 ;
        RECT  197.004 0 197.028 0.192 ;
    END
  END g_t_8_u_stk__kp_o[2]
  PIN g_t_8_u_stk__kp_o[30]
    DIRECTION OUTPUT ;
    USE SIGNAL ;
    PORT
      LAYER M5 ;
        RECT  203.676 0 203.7 0.192 ;
    END
  END g_t_8_u_stk__kp_o[30]
  PIN g_t_8_u_stk__kp_o[31]
    DIRECTION OUTPUT ;
    USE SIGNAL ;
    PORT
      LAYER M5 ;
        RECT  203.916 0 203.94 0.192 ;
    END
  END g_t_8_u_stk__kp_o[31]
  PIN g_t_8_u_stk__kp_o[3]
    DIRECTION OUTPUT ;
    USE SIGNAL ;
    PORT
      LAYER M5 ;
        RECT  197.244 0 197.268 0.192 ;
    END
  END g_t_8_u_stk__kp_o[3]
  PIN g_t_8_u_stk__kp_o[4]
    DIRECTION OUTPUT ;
    USE SIGNAL ;
    PORT
      LAYER M5 ;
        RECT  197.484 0 197.508 0.192 ;
    END
  END g_t_8_u_stk__kp_o[4]
  PIN g_t_8_u_stk__kp_o[5]
    DIRECTION OUTPUT ;
    USE SIGNAL ;
    PORT
      LAYER M5 ;
        RECT  197.724 0 197.748 0.192 ;
    END
  END g_t_8_u_stk__kp_o[5]
  PIN g_t_8_u_stk__kp_o[6]
    DIRECTION OUTPUT ;
    USE SIGNAL ;
    PORT
      LAYER M5 ;
        RECT  197.964 0 197.988 0.192 ;
    END
  END g_t_8_u_stk__kp_o[6]
  PIN g_t_8_u_stk__kp_o[7]
    DIRECTION OUTPUT ;
    USE SIGNAL ;
    PORT
      LAYER M5 ;
        RECT  198.204 0 198.228 0.192 ;
    END
  END g_t_8_u_stk__kp_o[7]
  PIN g_t_8_u_stk__kp_o[8]
    DIRECTION OUTPUT ;
    USE SIGNAL ;
    PORT
      LAYER M5 ;
        RECT  198.444 0 198.468 0.192 ;
    END
  END g_t_8_u_stk__kp_o[8]
  PIN g_t_8_u_stk__kp_o[9]
    DIRECTION OUTPUT ;
    USE SIGNAL ;
    PORT
      LAYER M5 ;
        RECT  198.684 0 198.708 0.192 ;
    END
  END g_t_8_u_stk__kp_o[9]
  PIN g_t_8_u_stk__kpv_o[0]
    DIRECTION OUTPUT ;
    USE SIGNAL ;
    PORT
      LAYER M5 ;
        RECT  204.156 0 204.18 0.192 ;
    END
  END g_t_8_u_stk__kpv_o[0]
  PIN g_t_8_u_stk__rst_n[0]
    DIRECTION INPUT ;
    USE SIGNAL ;
    PORT
      LAYER M5 ;
        RECT  204.396 0 204.42 0.192 ;
    END
  END g_t_8_u_stk__rst_n[0]
  PIN g_t_9_u_l8__clk[0]
    DIRECTION INPUT ;
    USE SIGNAL ;
    PORT
      LAYER M5 ;
        RECT  204.636 0 204.66 0.192 ;
    END
  END g_t_9_u_l8__clk[0]
  PIN g_t_9_u_stin__clk[0]
    DIRECTION INPUT ;
    USE SIGNAL ;
    PORT
      LAYER M5 ;
        RECT  204.876 0 204.9 0.192 ;
    END
  END g_t_9_u_stin__clk[0]
  PIN g_t_9_u_stin__rst_n[0]
    DIRECTION INPUT ;
    USE SIGNAL ;
    PORT
      LAYER M5 ;
        RECT  205.116 0 205.14 0.192 ;
    END
  END g_t_9_u_stin__rst_n[0]
  PIN g_t_9_u_stk__clk[0]
    DIRECTION INPUT ;
    USE SIGNAL ;
    PORT
      LAYER M5 ;
        RECT  205.356 0 205.38 0.192 ;
    END
  END g_t_9_u_stk__clk[0]
  PIN g_t_9_u_stk__gf_o[0]
    DIRECTION OUTPUT ;
    USE SIGNAL ;
    PORT
      LAYER M5 ;
        RECT  205.596 0 205.62 0.192 ;
    END
  END g_t_9_u_stk__gf_o[0]
  PIN g_t_9_u_stk__kp_o[0]
    DIRECTION OUTPUT ;
    USE SIGNAL ;
    PORT
      LAYER M5 ;
        RECT  205.836 0 205.86 0.192 ;
    END
  END g_t_9_u_stk__kp_o[0]
  PIN g_t_9_u_stk__kp_o[10]
    DIRECTION OUTPUT ;
    USE SIGNAL ;
    PORT
      LAYER M5 ;
        RECT  208.236 0 208.26 0.192 ;
    END
  END g_t_9_u_stk__kp_o[10]
  PIN g_t_9_u_stk__kp_o[11]
    DIRECTION OUTPUT ;
    USE SIGNAL ;
    PORT
      LAYER M5 ;
        RECT  208.476 0 208.5 0.192 ;
    END
  END g_t_9_u_stk__kp_o[11]
  PIN g_t_9_u_stk__kp_o[12]
    DIRECTION OUTPUT ;
    USE SIGNAL ;
    PORT
      LAYER M5 ;
        RECT  208.716 0 208.74 0.192 ;
    END
  END g_t_9_u_stk__kp_o[12]
  PIN g_t_9_u_stk__kp_o[13]
    DIRECTION OUTPUT ;
    USE SIGNAL ;
    PORT
      LAYER M5 ;
        RECT  208.956 0 208.98 0.192 ;
    END
  END g_t_9_u_stk__kp_o[13]
  PIN g_t_9_u_stk__kp_o[14]
    DIRECTION OUTPUT ;
    USE SIGNAL ;
    PORT
      LAYER M5 ;
        RECT  209.196 0 209.22 0.192 ;
    END
  END g_t_9_u_stk__kp_o[14]
  PIN g_t_9_u_stk__kp_o[15]
    DIRECTION OUTPUT ;
    USE SIGNAL ;
    PORT
      LAYER M5 ;
        RECT  209.436 0 209.46 0.192 ;
    END
  END g_t_9_u_stk__kp_o[15]
  PIN g_t_9_u_stk__kp_o[16]
    DIRECTION OUTPUT ;
    USE SIGNAL ;
    PORT
      LAYER M5 ;
        RECT  209.676 0 209.7 0.192 ;
    END
  END g_t_9_u_stk__kp_o[16]
  PIN g_t_9_u_stk__kp_o[17]
    DIRECTION OUTPUT ;
    USE SIGNAL ;
    PORT
      LAYER M5 ;
        RECT  209.916 0 209.94 0.192 ;
    END
  END g_t_9_u_stk__kp_o[17]
  PIN g_t_9_u_stk__kp_o[18]
    DIRECTION OUTPUT ;
    USE SIGNAL ;
    PORT
      LAYER M5 ;
        RECT  210.156 0 210.18 0.192 ;
    END
  END g_t_9_u_stk__kp_o[18]
  PIN g_t_9_u_stk__kp_o[19]
    DIRECTION OUTPUT ;
    USE SIGNAL ;
    PORT
      LAYER M5 ;
        RECT  210.348 0 210.372 0.192 ;
    END
  END g_t_9_u_stk__kp_o[19]
  PIN g_t_9_u_stk__kp_o[1]
    DIRECTION OUTPUT ;
    USE SIGNAL ;
    PORT
      LAYER M5 ;
        RECT  206.076 0 206.1 0.192 ;
    END
  END g_t_9_u_stk__kp_o[1]
  PIN g_t_9_u_stk__kp_o[20]
    DIRECTION OUTPUT ;
    USE SIGNAL ;
    PORT
      LAYER M5 ;
        RECT  210.588 0 210.612 0.192 ;
    END
  END g_t_9_u_stk__kp_o[20]
  PIN g_t_9_u_stk__kp_o[21]
    DIRECTION OUTPUT ;
    USE SIGNAL ;
    PORT
      LAYER M5 ;
        RECT  210.828 0 210.852 0.192 ;
    END
  END g_t_9_u_stk__kp_o[21]
  PIN g_t_9_u_stk__kp_o[22]
    DIRECTION OUTPUT ;
    USE SIGNAL ;
    PORT
      LAYER M5 ;
        RECT  211.068 0 211.092 0.192 ;
    END
  END g_t_9_u_stk__kp_o[22]
  PIN g_t_9_u_stk__kp_o[23]
    DIRECTION OUTPUT ;
    USE SIGNAL ;
    PORT
      LAYER M5 ;
        RECT  211.308 0 211.332 0.192 ;
    END
  END g_t_9_u_stk__kp_o[23]
  PIN g_t_9_u_stk__kp_o[24]
    DIRECTION OUTPUT ;
    USE SIGNAL ;
    PORT
      LAYER M5 ;
        RECT  211.548 0 211.572 0.192 ;
    END
  END g_t_9_u_stk__kp_o[24]
  PIN g_t_9_u_stk__kp_o[25]
    DIRECTION OUTPUT ;
    USE SIGNAL ;
    PORT
      LAYER M5 ;
        RECT  211.788 0 211.812 0.192 ;
    END
  END g_t_9_u_stk__kp_o[25]
  PIN g_t_9_u_stk__kp_o[26]
    DIRECTION OUTPUT ;
    USE SIGNAL ;
    PORT
      LAYER M5 ;
        RECT  212.028 0 212.052 0.192 ;
    END
  END g_t_9_u_stk__kp_o[26]
  PIN g_t_9_u_stk__kp_o[27]
    DIRECTION OUTPUT ;
    USE SIGNAL ;
    PORT
      LAYER M5 ;
        RECT  212.268 0 212.292 0.192 ;
    END
  END g_t_9_u_stk__kp_o[27]
  PIN g_t_9_u_stk__kp_o[28]
    DIRECTION OUTPUT ;
    USE SIGNAL ;
    PORT
      LAYER M5 ;
        RECT  212.508 0 212.532 0.192 ;
    END
  END g_t_9_u_stk__kp_o[28]
  PIN g_t_9_u_stk__kp_o[29]
    DIRECTION OUTPUT ;
    USE SIGNAL ;
    PORT
      LAYER M5 ;
        RECT  212.748 0 212.772 0.192 ;
    END
  END g_t_9_u_stk__kp_o[29]
  PIN g_t_9_u_stk__kp_o[2]
    DIRECTION OUTPUT ;
    USE SIGNAL ;
    PORT
      LAYER M5 ;
        RECT  206.316 0 206.34 0.192 ;
    END
  END g_t_9_u_stk__kp_o[2]
  PIN g_t_9_u_stk__kp_o[30]
    DIRECTION OUTPUT ;
    USE SIGNAL ;
    PORT
      LAYER M5 ;
        RECT  212.988 0 213.012 0.192 ;
    END
  END g_t_9_u_stk__kp_o[30]
  PIN g_t_9_u_stk__kp_o[31]
    DIRECTION OUTPUT ;
    USE SIGNAL ;
    PORT
      LAYER M5 ;
        RECT  213.228 0 213.252 0.192 ;
    END
  END g_t_9_u_stk__kp_o[31]
  PIN g_t_9_u_stk__kp_o[3]
    DIRECTION OUTPUT ;
    USE SIGNAL ;
    PORT
      LAYER M5 ;
        RECT  206.556 0 206.58 0.192 ;
    END
  END g_t_9_u_stk__kp_o[3]
  PIN g_t_9_u_stk__kp_o[4]
    DIRECTION OUTPUT ;
    USE SIGNAL ;
    PORT
      LAYER M5 ;
        RECT  206.796 0 206.82 0.192 ;
    END
  END g_t_9_u_stk__kp_o[4]
  PIN g_t_9_u_stk__kp_o[5]
    DIRECTION OUTPUT ;
    USE SIGNAL ;
    PORT
      LAYER M5 ;
        RECT  207.036 0 207.06 0.192 ;
    END
  END g_t_9_u_stk__kp_o[5]
  PIN g_t_9_u_stk__kp_o[6]
    DIRECTION OUTPUT ;
    USE SIGNAL ;
    PORT
      LAYER M5 ;
        RECT  207.276 0 207.3 0.192 ;
    END
  END g_t_9_u_stk__kp_o[6]
  PIN g_t_9_u_stk__kp_o[7]
    DIRECTION OUTPUT ;
    USE SIGNAL ;
    PORT
      LAYER M5 ;
        RECT  207.516 0 207.54 0.192 ;
    END
  END g_t_9_u_stk__kp_o[7]
  PIN g_t_9_u_stk__kp_o[8]
    DIRECTION OUTPUT ;
    USE SIGNAL ;
    PORT
      LAYER M5 ;
        RECT  207.756 0 207.78 0.192 ;
    END
  END g_t_9_u_stk__kp_o[8]
  PIN g_t_9_u_stk__kp_o[9]
    DIRECTION OUTPUT ;
    USE SIGNAL ;
    PORT
      LAYER M5 ;
        RECT  207.996 0 208.02 0.192 ;
    END
  END g_t_9_u_stk__kp_o[9]
  PIN g_t_9_u_stk__kpv_o[0]
    DIRECTION OUTPUT ;
    USE SIGNAL ;
    PORT
      LAYER M5 ;
        RECT  213.468 0 213.492 0.192 ;
    END
  END g_t_9_u_stk__kpv_o[0]
  PIN g_t_9_u_stk__rst_n[0]
    DIRECTION INPUT ;
    USE SIGNAL ;
    PORT
      LAYER M5 ;
        RECT  213.708 0 213.732 0.192 ;
    END
  END g_t_9_u_stk__rst_n[0]
  PIN VSS
    DIRECTION INOUT ;
    USE GROUND ;
    PORT
      LAYER M5 ;
        RECT  209.364 4.297 209.484 211.703 ;
        RECT  205.044 4.297 205.164 211.703 ;
        RECT  200.724 4.297 200.844 211.703 ;
        RECT  196.404 4.297 196.524 211.703 ;
        RECT  192.084 4.297 192.204 211.703 ;
        RECT  187.764 4.297 187.884 211.703 ;
        RECT  183.444 4.297 183.564 211.703 ;
        RECT  179.124 4.297 179.244 211.703 ;
        RECT  174.804 4.297 174.924 211.703 ;
        RECT  170.484 4.297 170.604 211.703 ;
        RECT  166.164 4.297 166.284 211.703 ;
        RECT  161.844 4.297 161.964 211.703 ;
        RECT  157.524 4.297 157.644 211.703 ;
        RECT  153.204 4.297 153.324 211.703 ;
        RECT  148.884 4.297 149.004 211.703 ;
        RECT  144.564 4.297 144.684 211.703 ;
        RECT  140.244 4.297 140.364 211.703 ;
        RECT  135.924 4.297 136.044 211.703 ;
        RECT  131.604 4.297 131.724 211.703 ;
        RECT  127.284 4.297 127.404 211.703 ;
        RECT  122.964 4.297 123.084 211.703 ;
        RECT  118.644 4.297 118.764 211.703 ;
        RECT  114.324 4.297 114.444 211.703 ;
        RECT  110.004 4.297 110.124 211.703 ;
        RECT  105.684 4.297 105.804 211.703 ;
        RECT  101.364 4.297 101.484 211.703 ;
        RECT  97.044 4.297 97.164 211.703 ;
        RECT  92.724 4.297 92.844 211.703 ;
        RECT  88.404 4.297 88.524 211.703 ;
        RECT  84.084 4.297 84.204 211.703 ;
        RECT  79.764 4.297 79.884 211.703 ;
        RECT  75.444 4.297 75.564 211.703 ;
        RECT  71.124 4.297 71.244 211.703 ;
        RECT  66.804 4.297 66.924 211.703 ;
        RECT  62.484 4.297 62.604 211.703 ;
        RECT  58.164 4.297 58.284 211.703 ;
        RECT  53.844 4.297 53.964 211.703 ;
        RECT  49.524 4.297 49.644 211.703 ;
        RECT  45.204 4.297 45.324 211.703 ;
        RECT  40.884 4.297 41.004 211.703 ;
        RECT  36.564 4.297 36.684 211.703 ;
        RECT  32.244 4.297 32.364 211.703 ;
        RECT  27.924 4.297 28.044 211.703 ;
        RECT  23.604 4.297 23.724 211.703 ;
        RECT  19.284 4.297 19.404 211.703 ;
        RECT  14.964 4.297 15.084 211.703 ;
        RECT  10.644 4.297 10.764 211.703 ;
        RECT  6.324 4.297 6.444 211.703 ;
    END
  END VSS
  PIN VDD
    DIRECTION INOUT ;
    USE POWER ;
    PORT
      LAYER M5 ;
        RECT  209.556 4.311 209.676 211.689 ;
        RECT  205.236 4.311 205.356 211.689 ;
        RECT  200.916 4.311 201.036 211.689 ;
        RECT  196.596 4.311 196.716 211.689 ;
        RECT  192.276 4.311 192.396 211.689 ;
        RECT  187.956 4.311 188.076 211.689 ;
        RECT  183.636 4.311 183.756 211.689 ;
        RECT  179.316 4.311 179.436 211.689 ;
        RECT  174.996 4.311 175.116 211.689 ;
        RECT  170.676 4.311 170.796 211.689 ;
        RECT  166.356 4.311 166.476 211.689 ;
        RECT  162.036 4.311 162.156 211.689 ;
        RECT  157.716 4.311 157.836 211.689 ;
        RECT  153.396 4.311 153.516 211.689 ;
        RECT  149.076 4.311 149.196 211.689 ;
        RECT  144.756 4.311 144.876 211.689 ;
        RECT  140.436 4.311 140.556 211.689 ;
        RECT  136.116 4.311 136.236 211.689 ;
        RECT  131.796 4.311 131.916 211.689 ;
        RECT  127.476 4.311 127.596 211.689 ;
        RECT  123.156 4.311 123.276 211.689 ;
        RECT  118.836 4.311 118.956 211.689 ;
        RECT  114.516 4.311 114.636 211.689 ;
        RECT  110.196 4.311 110.316 211.689 ;
        RECT  105.876 4.311 105.996 211.689 ;
        RECT  101.556 4.311 101.676 211.689 ;
        RECT  97.236 4.311 97.356 211.689 ;
        RECT  92.916 4.311 93.036 211.689 ;
        RECT  88.596 4.311 88.716 211.689 ;
        RECT  84.276 4.311 84.396 211.689 ;
        RECT  79.956 4.311 80.076 211.689 ;
        RECT  75.636 4.311 75.756 211.689 ;
        RECT  71.316 4.311 71.436 211.689 ;
        RECT  66.996 4.311 67.116 211.689 ;
        RECT  62.676 4.311 62.796 211.689 ;
        RECT  58.356 4.311 58.476 211.689 ;
        RECT  54.036 4.311 54.156 211.689 ;
        RECT  49.716 4.311 49.836 211.689 ;
        RECT  45.396 4.311 45.516 211.689 ;
        RECT  41.076 4.311 41.196 211.689 ;
        RECT  36.756 4.311 36.876 211.689 ;
        RECT  32.436 4.311 32.556 211.689 ;
        RECT  28.116 4.311 28.236 211.689 ;
        RECT  23.796 4.311 23.916 211.689 ;
        RECT  19.476 4.311 19.596 211.689 ;
        RECT  15.156 4.311 15.276 211.689 ;
        RECT  10.836 4.311 10.956 211.689 ;
        RECT  6.516 4.311 6.636 211.689 ;
    END
  END VDD
  OBS
    LAYER RVTN ;
     RECT  0 0 216 216 ;
    LAYER RVTP ;
     RECT  0 0 216 216 ;
    LAYER M1 ;
     RECT  0 0 216 216 ;
    LAYER M2 ;
     RECT  0 0 216 216 ;
    LAYER M3 ;
     RECT  0 0 216 216 ;
    LAYER M4 ;
     RECT  0 0 216 216 ;
    LAYER M5 ;
     RECT  0 0 216 216 ;
    LAYER M6 ;
     RECT  0 0 216 216 ;
    LAYER M7 ;
     RECT  0 0 216 216 ;
  END
END kv3_head_eighth_e4
END LIBRARY
